VERSION 5.8 ;
BUSBITCHARS "[]" ;
DIVIDERCHAR "/" ;

SITE IOSite
  CLASS       PAD ;
  SYMMETRY    X Y R90 ;
  SIZE        0.001 BY 119.500 ;
END IOSite

SITE CornerSite
  CLASS       PAD ;
  SYMMETRY    X Y R90 ;
  SIZE        119.500 BY 119.500 ;
END CornerSite

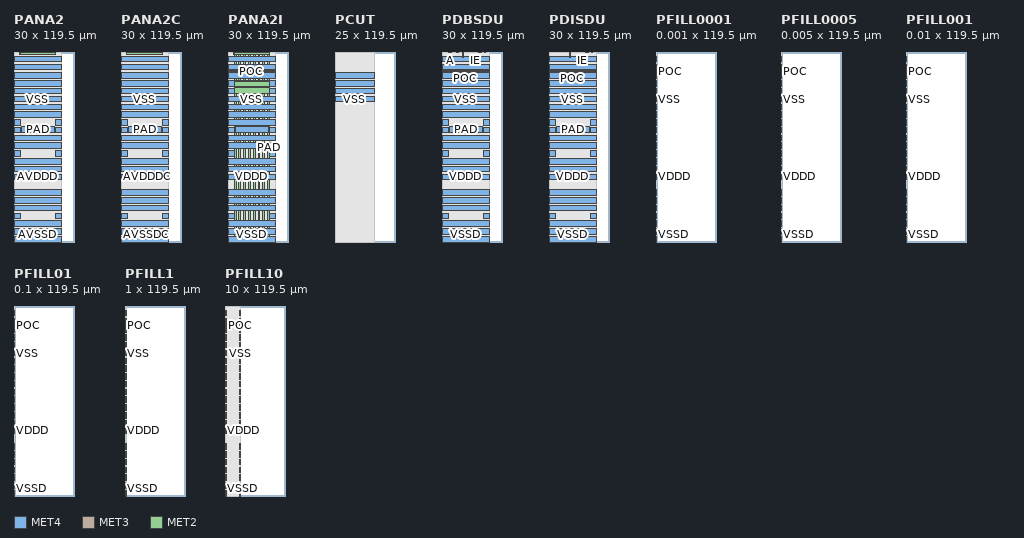
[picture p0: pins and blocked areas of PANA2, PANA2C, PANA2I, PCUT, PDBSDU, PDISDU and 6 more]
MACRO PANA2
  CLASS PAD ;
  ORIGIN 0 0 ;
  FOREIGN PANA2 0 0 ;
  SIZE 30 BY 119.5 ;
  SYMMETRY X Y R90 ;
  SITE IOSite ;
  PIN PAD
    DIRECTION INOUT ;
    USE SIGNAL ;
    ANTENNAPARTIALMETALAREA 1394.854 LAYER MET2 ;
    ANTENNAPARTIALMETALAREA 1394.854 LAYER MET3 ;
    ANTENNAPARTIALMETALAREA 319.515 LAYER MET4 ;
    ANTENNAPARTIALMETALSIDEAREA 395.8332 LAYER MET2 ;
    ANTENNAPARTIALMETALSIDEAREA 395.8332 LAYER MET3 ;
    ANTENNAPARTIALMETALSIDEAREA 41.6703 LAYER MET4 ;
    ANTENNAPARTIALCUTAREA 33.048 LAYER VIA3 ;
    ANTENNAPARTIALCUTAREA 249.2856 LAYER VIA2 ;
    ANTENNADIFFAREA 671.232 LAYER MET2 ;
    ANTENNADIFFAREA 671.232 LAYER MET3 ;
    ANTENNADIFFAREA 671.232 LAYER MET4 ;
    PORT
      LAYER MET4 ;
        RECT 3.76 117.8 26.24 119.5 ;
        RECT 4.5 68.6 25.5 72.415 ;
      LAYER MET3 ;
        RECT 3.79 117.8 26.21 119.5 ;
      LAYER MET2 ;
        RECT 3.79 117.8 26.21 119.5 ;
    END
  END PAD
  PIN AVDDD
    DIRECTION INOUT ;
    USE POWER ;
    PORT
      LAYER MET4 ;
        RECT 0 39.2 30 42.7 ;
        RECT 0 44.1 30 47.6 ;
        RECT 0 49 30 52.5 ;
        RECT 26 53.9 30 57.4 ;
        RECT 0 58.8 30 62.3 ;
        RECT 0 63.7 30 67.2 ;
        RECT 26 68.6 30 72.1 ;
        RECT 26 73.415 30 76.915 ;
        RECT 0 78.315 30 81.815 ;
        RECT 0 83.215 30 86.715 ;
        RECT 0 108.4 30 111.9 ;
        RECT 0 113.3 30 116.8 ;
        RECT 0 53.9 4 57.4 ;
        RECT 0 68.6 4 72.1 ;
        RECT 0 73.415 4 76.915 ;
    END
  END AVDDD
  PIN AVSSD
    DIRECTION INOUT ;
    USE GROUND ;
    PORT
      LAYER MET4 ;
        RECT 0 0 30 3.5 ;
        RECT 0 4.9 30 8.4 ;
        RECT 0 9.8 30 13.3 ;
        RECT 26 14.7 30 18.2 ;
        RECT 0 19.6 30 23.1 ;
        RECT 0 24.5 30 28 ;
        RECT 0 29.4 30 32.9 ;
        RECT 0 14.7 4 18.2 ;
    END
  END AVSSD
  PIN VSS
    DIRECTION INOUT ;
    USE GROUND ;
    PORT
      LAYER MET4 ;
        RECT 0 88.115 30 91.615 ;
        RECT 0 93.1 30 96.6 ;
        RECT 0 98 30 101.5 ;
        RECT 0 102.9 30 106.4 ;
    END
  END VSS
  OBS
    LAYER MET1 ;
      RECT 0 0 30 119.5 ;
    LAYER VIA1 ;
      RECT 0 0 30 119.5 ;
    LAYER MET2 ;
      RECT 0 0 30 119.5 ;
    LAYER VIA2 ;
      RECT 0 0 30 119.5 ;
    LAYER MET3 ;
      RECT 0 0 30 119.5 ;
    LAYER VIA3 ;
      RECT 0 0 30 119.5 ;
    LAYER MET4 ;
      RECT 0 0 30 119.5 ;
  END
END PANA2

MACRO PANA2C
  CLASS PAD ;
  ORIGIN 0 0 ;
  FOREIGN PANA2C 0 0 ;
  SIZE 30 BY 119.5 ;
  SYMMETRY X Y R90 ;
  SITE IOSite ;
  PIN PAD
    DIRECTION INOUT ;
    USE SIGNAL ;
    ANTENNAPARTIALMETALAREA 1394.752 LAYER MET2 ;
    ANTENNAPARTIALMETALAREA 1394.752 LAYER MET3 ;
    ANTENNAPARTIALMETALAREA 319.515 LAYER MET4 ;
    ANTENNAPARTIALMETALSIDEAREA 395.808 LAYER MET2 ;
    ANTENNAPARTIALMETALSIDEAREA 395.808 LAYER MET3 ;
    ANTENNAPARTIALMETALSIDEAREA 41.6703 LAYER MET4 ;
    ANTENNAPARTIALCUTAREA 33.048 LAYER VIA3 ;
    ANTENNAPARTIALCUTAREA 213.111 LAYER VIA2 ;
    ANTENNADIFFAREA 671.232 LAYER MET2 ;
    ANTENNADIFFAREA 671.232 LAYER MET3 ;
    ANTENNADIFFAREA 671.232 LAYER MET4 ;
    PORT
      LAYER MET4 ;
        RECT 3.76 117.8 26.24 119.5 ;
        RECT 4.5 68.6 25.5 72.415 ;
      LAYER MET3 ;
        RECT 3.76 117.8 26.24 119.5 ;
      LAYER MET2 ;
        RECT 3.76 117.8 26.24 119.5 ;
    END
  END PAD
  PIN AVDDDC
    DIRECTION INOUT ;
    USE POWER ;
    PORT
      LAYER MET4 ;
        RECT 0 39.2 30 42.7 ;
        RECT 0 44.1 30 47.6 ;
        RECT 0 49 30 52.5 ;
        RECT 26 53.9 30 57.4 ;
        RECT 0 58.8 30 62.3 ;
        RECT 0 63.7 30 67.2 ;
        RECT 26 68.6 30 72.1 ;
        RECT 26 73.415 30 76.915 ;
        RECT 0 78.315 30 81.815 ;
        RECT 0 83.215 30 86.715 ;
        RECT 0 108.4 30 111.9 ;
        RECT 0 113.3 30 116.8 ;
        RECT 0 53.9 4 57.4 ;
        RECT 0 68.6 4 72.1 ;
        RECT 0 73.415 4 76.915 ;
    END
  END AVDDDC
  PIN AVSSDC
    DIRECTION INOUT ;
    USE GROUND ;
    PORT
      LAYER MET4 ;
        RECT 0 0 30 3.5 ;
        RECT 0 4.9 30 8.4 ;
        RECT 0 9.8 30 13.3 ;
        RECT 26 14.7 30 18.2 ;
        RECT 0 19.6 30 23.1 ;
        RECT 0 24.5 30 28 ;
        RECT 0 29.4 30 32.9 ;
        RECT 0 14.7 4 18.2 ;
    END
  END AVSSDC
  PIN VSS
    DIRECTION INOUT ;
    USE GROUND ;
    PORT
      LAYER MET4 ;
        RECT 0 88.115 30 91.615 ;
        RECT 0 93.1 30 96.6 ;
        RECT 0 98 30 101.5 ;
        RECT 0 102.9 30 106.4 ;
    END
  END VSS
  OBS
    LAYER MET1 ;
      RECT 0 0 30 119.5 ;
    LAYER VIA1 ;
      RECT 0 0 30 119.5 ;
    LAYER MET2 ;
      RECT 0 0 30 119.5 ;
    LAYER VIA2 ;
      RECT 0 0 30 119.5 ;
    LAYER MET3 ;
      RECT 0 0 30 119.5 ;
    LAYER VIA3 ;
      RECT 0 0 30 119.5 ;
    LAYER MET4 ;
      RECT 0 0 30 119.5 ;
  END
END PANA2C

MACRO PANA2I
  CLASS PAD ;
  ORIGIN 0 0 ;
  FOREIGN PANA2I 0 0 ;
  SIZE 30 BY 119.5 ;
  SYMMETRY X Y R90 ;
  SITE IOSite ;
  PIN PAD
    DIRECTION INOUT ;
    USE SIGNAL ;
    ANTENNAPARTIALMETALAREA 250.628 LAYER MET2 ;
    ANTENNAPARTIALMETALAREA 250.152 LAYER MET3 ;
    ANTENNAPARTIALMETALAREA 319.515 LAYER MET4 ;
    ANTENNAPARTIALMETALSIDEAREA 41.6703 LAYER MET4 ;
    ANTENNAPARTIALCUTAREA 28.4634 LAYER VIA3 ;
    ANTENNAPARTIALCUTAREA 201.9897 LAYER VIA2 ;
    ANTENNADIFFAREA 671.232 LAYER MET2 ;
    ANTENNADIFFAREA 671.232 LAYER MET3 ;
    ANTENNADIFFAREA 671.232 LAYER MET4 ;
    PORT
      LAYER MET4 ;
        RECT 3.76 117.8 26.24 119.5 ;
        RECT 4.5 68.6 25.5 72.415 ;
      LAYER MET3 ;
        RECT 3.76 117.8 26.24 119.5 ;
        RECT 24.9 0 26.1 119.5 ;
        RECT 3.9 98 26.1 101 ;
        RECT 3.9 93.1 26.1 97.1 ;
        RECT 21.9 0 23.1 119.5 ;
        RECT 18.9 0 20.1 119.5 ;
        RECT 15.9 0 17.1 119.5 ;
        RECT 12.9 0 14.1 119.5 ;
        RECT 9.9 0 11.1 119.5 ;
        RECT 6.9 0 8.1 119.5 ;
        RECT 3.9 0 5.1 119.5 ;
      LAYER MET2 ;
        RECT 3.9 117.8 26.1 119.5 ;
        RECT 24.9 0 26.1 119.5 ;
        RECT 3.9 98 26.1 101 ;
        RECT 3.9 93.1 26.1 97.1 ;
        RECT 21.9 0 23.1 119.5 ;
        RECT 18.9 0 20.1 119.5 ;
        RECT 15.9 0 17.1 119.5 ;
        RECT 12.9 0 14.1 119.5 ;
        RECT 9.9 0 11.1 119.5 ;
        RECT 6.9 0 8.1 119.5 ;
        RECT 3.9 0 5.1 119.5 ;
    END
  END PAD
  PIN POC
    DIRECTION INOUT ;
    USE GROUND ;
    PORT
      LAYER MET4 ;
        RECT 0 107.15 30 107.65 ;
    END
  END POC
  PIN VDD
    DIRECTION INOUT ;
    USE POWER ;
    PORT
      CLASS CORE ;
      LAYER MET4 ;
        RECT 0 113.3 30 116.8 ;
    END
    PORT
      LAYER MET4 ;
        RECT 0 108.4 30 111.9 ;
    END
  END VDD
  PIN VDDD
    DIRECTION INOUT ;
    USE POWER ;
    PORT
      LAYER MET4 ;
        RECT 0 39.2 30 42.7 ;
        RECT 0 44.1 30 47.6 ;
        RECT 0 49 30 52.5 ;
        RECT 26 53.9 30 57.4 ;
        RECT 0 58.8 30 62.3 ;
        RECT 0 63.7 30 67.2 ;
        RECT 26 68.6 30 72.1 ;
        RECT 0 73.415 30 76.915 ;
        RECT 0 78.315 30 81.815 ;
        RECT 0 83.215 30 86.715 ;
        RECT 0 53.9 4 57.4 ;
        RECT 0 68.6 4 72.1 ;
    END
  END VDDD
  PIN VSS
    DIRECTION INOUT ;
    USE GROUND ;
    PORT
      LAYER MET4 ;
        RECT 0 88.115 30 91.615 ;
        RECT 0 93.1 30 96.6 ;
        RECT 0 98 30 101.5 ;
        RECT 0 102.9 30 106.4 ;
    END
  END VSS
  PIN VSSD
    DIRECTION INOUT ;
    USE GROUND ;
    PORT
      LAYER MET4 ;
        RECT 0 0 30 3.5 ;
        RECT 0 4.9 30 8.4 ;
        RECT 0 9.8 30 13.3 ;
        RECT 26 14.7 30 18.2 ;
        RECT 0 19.6 30 23.1 ;
        RECT 0 24.5 30 28 ;
        RECT 0 29.4 30 32.9 ;
        RECT 0 14.7 4 18.2 ;
    END
  END VSSD
  OBS
    LAYER MET1 ;
      RECT 0 0 30 119.5 ;
    LAYER VIA1 ;
      RECT 0 0 30 119.5 ;
    LAYER MET2 ;
      RECT 0 0 30 119.5 ;
    LAYER VIA2 ;
      RECT 0 0 30 119.5 ;
    LAYER MET3 ;
      RECT 0 0 30 119.5 ;
    LAYER VIA3 ;
      RECT 0 0 30 119.5 ;
    LAYER MET4 ;
      RECT 0 0 30 119.5 ;
  END
END PANA2I

MACRO PCUT
  CLASS PAD ;
  ORIGIN 0 0 ;
  FOREIGN PCUT 0 0 ;
  SIZE 25 BY 119.5 ;
  SYMMETRY X Y R90 ;
  SITE IOSite ;
  PIN VSS
    DIRECTION INOUT ;
    USE GROUND ;
    PORT
      LAYER MET4 ;
        RECT 0 88.115 25 91.615 ;
        RECT 0 93.1 25 96.6 ;
        RECT 0 98 25 101.5 ;
        RECT 0 102.9 25 106.4 ;
    END
  END VSS
  OBS
    LAYER MET1 ;
      RECT 0 0 25 119.5 ;
    LAYER VIA1 ;
      RECT 0 0 25 119.5 ;
    LAYER MET2 ;
      RECT 0 0 25 119.5 ;
    LAYER VIA2 ;
      RECT 0 0 25 119.5 ;
    LAYER MET3 ;
      RECT 0 0 25 119.5 ;
    LAYER VIA3 ;
      RECT 0 0 25 119.5 ;
    LAYER MET4 ;
      RECT 0 0 25 119.5 ;
  END
END PCUT

MACRO PDBSDU
  CLASS PAD ;
  ORIGIN 0 0 ;
  FOREIGN PDBSDU 0 0 ;
  SIZE 30 BY 119.5 ;
  SYMMETRY X Y R90 ;
  SITE IOSite ;
  PIN A
    DIRECTION INPUT ;
    USE SIGNAL ;
    ANTENNAPARTIALMETALAREA 1.66719 LAYER MET2 ;
    ANTENNAPARTIALMETALAREA 0.6384 LAYER MET3 ;
    ANTENNAPARTIALMETALSIDEAREA 4.11894 LAYER MET2 ;
    ANTENNAPARTIALMETALSIDEAREA 0.8652 LAYER MET3 ;
    ANTENNAPARTIALCUTAREA 0.0243 LAYER VIA3 ;
    ANTENNAPARTIALCUTAREA 0.0405 LAYER VIA2 ;
    ANTENNAMODEL OXIDE1 ;
      ANTENNAGATEAREA 0.333 LAYER MET2 ;
      ANTENNAGATEAREA 0.846 LAYER MET3 ;
      ANTENNAGATEAREA 0.846 LAYER MET4 ;
      ANTENNAMAXAREACAR 7.098407 LAYER MET2 ;
      ANTENNAMAXAREACAR 8.243407 LAYER MET3 ;
      ANTENNAMAXAREACAR 8.397071 LAYER MET4 ;
      ANTENNAMAXSIDEAREACAR 15.275072 LAYER MET2 ;
      ANTENNAMAXSIDEAREACAR 17.256325 LAYER MET3 ;
      ANTENNAMAXSIDEAREACAR 17.63363 LAYER MET4 ;
      ANTENNAMAXCUTCAR 0.256227 LAYER VIA3 ;
      ANTENNAMAXCUTCAR 0.227504 LAYER VIA2 ;
    PORT
      LAYER MET4 ;
        RECT 5.235 119.24 5.735 119.5 ;
      LAYER MET3 ;
        RECT 5.235 119.24 5.735 119.5 ;
      LAYER MET2 ;
        RECT 5.235 119.24 5.735 119.5 ;
    END
  END A
  PIN C
    DIRECTION OUTPUT ;
    USE SIGNAL ;
    ANTENNAPARTIALMETALAREA 10.04162 LAYER MET2 ;
    ANTENNAPARTIALMETALSIDEAREA 21.72282 LAYER MET2 ;
    ANTENNAPARTIALCUTAREA 0.0243 LAYER VIA3 ;
    ANTENNAPARTIALCUTAREA 0.0243 LAYER VIA2 ;
    ANTENNADIFFAREA 4.8 LAYER MET2 ;
    ANTENNADIFFAREA 4.8 LAYER MET3 ;
    ANTENNADIFFAREA 4.8 LAYER MET4 ;
    PORT
      LAYER MET4 ;
        RECT 13.025 119.24 13.525 119.5 ;
      LAYER MET3 ;
        RECT 13.025 119.24 13.525 119.5 ;
      LAYER MET2 ;
        RECT 13.025 116.277 13.525 119.5 ;
    END
  END C
  PIN IE
    DIRECTION INPUT ;
    USE SIGNAL ;
    ANTENNAPARTIALMETALAREA 1.83225 LAYER MET2 ;
    ANTENNAPARTIALMETALSIDEAREA 5.1303 LAYER MET2 ;
    ANTENNAPARTIALCUTAREA 0.0243 LAYER VIA3 ;
    ANTENNAPARTIALCUTAREA 0.0243 LAYER VIA2 ;
    ANTENNAMODEL OXIDE1 ;
      ANTENNAGATEAREA 0.468 LAYER MET2 ;
      ANTENNAGATEAREA 0.468 LAYER MET3 ;
      ANTENNAGATEAREA 0.468 LAYER MET4 ;
      ANTENNAMAXAREACAR 5.590342 LAYER MET2 ;
      ANTENNAMAXAREACAR 5.86812 LAYER MET3 ;
      ANTENNAMAXAREACAR 6.145897 LAYER MET4 ;
      ANTENNAMAXSIDEAREACAR 13.332179 LAYER MET2 ;
      ANTENNAMAXSIDEAREACAR 14.014231 LAYER MET3 ;
      ANTENNAMAXSIDEAREACAR 14.696282 LAYER MET4 ;
      ANTENNAMAXCUTCAR 0.193846 LAYER VIA3 ;
      ANTENNAMAXCUTCAR 0.141923 LAYER VIA2 ;
    PORT
      LAYER MET4 ;
        RECT 20.875 119.24 21.375 119.5 ;
      LAYER MET3 ;
        RECT 20.875 119.24 21.375 119.5 ;
      LAYER MET2 ;
        RECT 20.875 119.24 21.375 119.5 ;
    END
  END IE
  PIN OE
    DIRECTION INPUT ;
    USE SIGNAL ;
    ANTENNAPARTIALMETALAREA 1.66005 LAYER MET2 ;
    ANTENNAPARTIALMETALAREA 1.178 LAYER MET3 ;
    ANTENNAPARTIALMETALSIDEAREA 4.1013 LAYER MET2 ;
    ANTENNAPARTIALMETALSIDEAREA 1.4616 LAYER MET3 ;
    ANTENNAPARTIALCUTAREA 0.0243 LAYER VIA3 ;
    ANTENNAPARTIALCUTAREA 0.0405 LAYER VIA2 ;
    ANTENNAMODEL OXIDE1 ;
      ANTENNAGATEAREA 0.333 LAYER MET2 ;
      ANTENNAGATEAREA 0.801 LAYER MET3 ;
      ANTENNAGATEAREA 0.801 LAYER MET4 ;
      ANTENNAMAXAREACAR 5.212558 LAYER MET2 ;
      ANTENNAMAXAREACAR 7.07361 LAYER MET3 ;
      ANTENNAMAXAREACAR 7.235908 LAYER MET4 ;
      ANTENNAMAXSIDEAREACAR 10.956954 LAYER MET2 ;
      ANTENNAMAXSIDEAREACAR 13.740232 LAYER MET3 ;
      ANTENNAMAXSIDEAREACAR 14.138734 LAYER MET4 ;
      ANTENNAMAXCUTCAR 0.206876 LAYER VIA3 ;
      ANTENNAMAXCUTCAR 0.176538 LAYER VIA2 ;
    PORT
      LAYER MET4 ;
        RECT 4.085 119.24 4.585 119.5 ;
      LAYER MET3 ;
        RECT 4.085 119.24 4.585 119.5 ;
      LAYER MET2 ;
        RECT 4.085 119.24 4.585 119.5 ;
    END
  END OE
  PIN PD
    DIRECTION INPUT ;
    USE SIGNAL ;
    ANTENNAPARTIALMETALAREA 1.83225 LAYER MET2 ;
    ANTENNAPARTIALMETALAREA 0.4695 LAYER MET3 ;
    ANTENNAPARTIALMETALSIDEAREA 5.1303 LAYER MET2 ;
    ANTENNAPARTIALMETALSIDEAREA 1.3692 LAYER MET3 ;
    ANTENNAPARTIALCUTAREA 0.0243 LAYER VIA3 ;
    ANTENNAPARTIALCUTAREA 0.0405 LAYER VIA2 ;
    ANTENNADIFFAREA 0.39 LAYER MET2 ;
    ANTENNADIFFAREA 0.39 LAYER MET3 ;
    ANTENNADIFFAREA 0.39 LAYER MET4 ;
    ANTENNAMODEL OXIDE1 ;
      ANTENNAGATEAREA 0.468 LAYER MET2 ;
      ANTENNAGATEAREA 6.468 LAYER MET3 ;
      ANTENNAGATEAREA 6.468 LAYER MET4 ;
      ANTENNAMAXAREACAR 5.590342 LAYER MET2 ;
      ANTENNAMAXAREACAR 5.940708 LAYER MET3 ;
      ANTENNAMAXAREACAR 5.960807 LAYER MET4 ;
      ANTENNAMAXSIDEAREACAR 13.332179 LAYER MET2 ;
      ANTENNAMAXSIDEAREACAR 14.225919 LAYER MET3 ;
      ANTENNAMAXSIDEAREACAR 14.27527 LAYER MET4 ;
      ANTENNAMAXCUTCAR 0.180295 LAYER VIA3 ;
      ANTENNAMAXCUTCAR 0.176538 LAYER VIA2 ;
    PORT
      LAYER MET4 ;
        RECT 24.03 119.24 24.53 119.5 ;
      LAYER MET3 ;
        RECT 24.03 119.24 24.53 119.5 ;
      LAYER MET2 ;
        RECT 24.03 119.24 24.53 119.5 ;
    END
  END PD
  PIN PU
    DIRECTION INPUT ;
    USE SIGNAL ;
    ANTENNAPARTIALMETALAREA 2.28055 LAYER MET2 ;
    ANTENNAPARTIALMETALSIDEAREA 5.6343 LAYER MET2 ;
    ANTENNAPARTIALCUTAREA 0.0243 LAYER VIA3 ;
    ANTENNAPARTIALCUTAREA 0.0243 LAYER VIA2 ;
    ANTENNADIFFAREA 0.39 LAYER MET2 ;
    ANTENNADIFFAREA 0.39 LAYER MET3 ;
    ANTENNADIFFAREA 0.39 LAYER MET4 ;
    ANTENNAMODEL OXIDE1 ;
      ANTENNAGATEAREA 6.468 LAYER MET2 ;
      ANTENNAGATEAREA 6.468 LAYER MET3 ;
      ANTENNAGATEAREA 6.468 LAYER MET4 ;
      ANTENNAMAXAREACAR 2.11009 LAYER MET2 ;
      ANTENNAMAXAREACAR 2.130189 LAYER MET3 ;
      ANTENNAMAXAREACAR 2.150288 LAYER MET4 ;
      ANTENNAMAXSIDEAREACAR 3.321104 LAYER MET2 ;
      ANTENNAMAXSIDEAREACAR 3.370455 LAYER MET3 ;
      ANTENNAMAXSIDEAREACAR 3.419805 LAYER MET4 ;
      ANTENNAMAXCUTCAR 0.097514 LAYER VIA3 ;
      ANTENNAMAXCUTCAR 0.093757 LAYER VIA2 ;
    PORT
      LAYER MET4 ;
        RECT 26.71 119.24 27.21 119.5 ;
      LAYER MET3 ;
        RECT 26.71 119.24 27.21 119.5 ;
      LAYER MET2 ;
        RECT 26.71 119.24 27.21 119.5 ;
    END
  END PU
  PIN S0
    DIRECTION INPUT ;
    USE SIGNAL ;
    ANTENNAPARTIALMETALAREA 1.9601 LAYER MET2 ;
    ANTENNAPARTIALMETALAREA 0.159 LAYER MET3 ;
    ANTENNAPARTIALMETALSIDEAREA 4.8426 LAYER MET2 ;
    ANTENNAPARTIALMETALSIDEAREA 0.4914 LAYER MET3 ;
    ANTENNAPARTIALCUTAREA 0.0243 LAYER VIA3 ;
    ANTENNAPARTIALCUTAREA 0.0405 LAYER VIA2 ;
    ANTENNADIFFAREA 0.39 LAYER MET2 ;
    ANTENNADIFFAREA 0.39 LAYER MET3 ;
    ANTENNADIFFAREA 0.39 LAYER MET4 ;
    ANTENNAMODEL OXIDE1 ;
      ANTENNAGATEAREA 0.468 LAYER MET2 ;
      ANTENNAGATEAREA 6.468 LAYER MET3 ;
      ANTENNAGATEAREA 6.468 LAYER MET4 ;
      ANTENNAMAXAREACAR 5.945748 LAYER MET2 ;
      ANTENNAMAXAREACAR 6.248108 LAYER MET3 ;
      ANTENNAMAXAREACAR 6.268207 LAYER MET4 ;
      ANTENNAMAXSIDEAREACAR 12.797436 LAYER MET2 ;
      ANTENNAMAXSIDEAREACAR 13.555461 LAYER MET3 ;
      ANTENNAMAXSIDEAREACAR 13.604812 LAYER MET4 ;
      ANTENNAMAXCUTCAR 0.180295 LAYER VIA3 ;
      ANTENNAMAXCUTCAR 0.176538 LAYER VIA2 ;
    PORT
      LAYER MET4 ;
        RECT 8.195 119.24 8.695 119.5 ;
      LAYER MET3 ;
        RECT 8.195 119.24 8.695 119.5 ;
      LAYER MET2 ;
        RECT 8.195 119.24 8.695 119.5 ;
    END
  END S0
  PIN S1
    DIRECTION INPUT ;
    USE SIGNAL ;
    ANTENNAPARTIALMETALAREA 1.9397 LAYER MET2 ;
    ANTENNAPARTIALMETALAREA 0.24 LAYER MET3 ;
    ANTENNAPARTIALMETALSIDEAREA 4.7922 LAYER MET2 ;
    ANTENNAPARTIALMETALSIDEAREA 0.7182 LAYER MET3 ;
    ANTENNAPARTIALCUTAREA 0.0243 LAYER VIA3 ;
    ANTENNAPARTIALCUTAREA 0.0405 LAYER VIA2 ;
    ANTENNADIFFAREA 0.39 LAYER MET2 ;
    ANTENNADIFFAREA 0.39 LAYER MET3 ;
    ANTENNADIFFAREA 0.39 LAYER MET4 ;
    ANTENNAMODEL OXIDE1 ;
      ANTENNAGATEAREA 0.468 LAYER MET2 ;
      ANTENNAGATEAREA 6.468 LAYER MET3 ;
      ANTENNAGATEAREA 6.468 LAYER MET4 ;
      ANTENNAMAXAREACAR 6.148825 LAYER MET2 ;
      ANTENNAMAXAREACAR 6.463708 LAYER MET3 ;
      ANTENNAMAXAREACAR 6.483807 LAYER MET4 ;
      ANTENNAMAXSIDEAREACAR 12.929744 LAYER MET2 ;
      ANTENNAMAXSIDEAREACAR 13.722834 LAYER MET3 ;
      ANTENNAMAXSIDEAREACAR 13.772184 LAYER MET4 ;
      ANTENNAMAXCUTCAR 0.180295 LAYER VIA3 ;
      ANTENNAMAXCUTCAR 0.176538 LAYER VIA2 ;
    PORT
      LAYER MET4 ;
        RECT 9.115 119.24 9.615 119.5 ;
      LAYER MET3 ;
        RECT 9.115 119.24 9.615 119.5 ;
      LAYER MET2 ;
        RECT 9.115 119.24 9.615 119.5 ;
    END
  END S1
  PIN S2
    DIRECTION INPUT ;
    USE SIGNAL ;
    ANTENNAPARTIALMETALAREA 2.074 LAYER MET2 ;
    ANTENNAPARTIALMETALAREA 0.378 LAYER MET3 ;
    ANTENNAPARTIALMETALSIDEAREA 5.124 LAYER MET2 ;
    ANTENNAPARTIALMETALSIDEAREA 1.1046 LAYER MET3 ;
    ANTENNAPARTIALCUTAREA 0.0243 LAYER VIA3 ;
    ANTENNAPARTIALCUTAREA 0.0405 LAYER VIA2 ;
    ANTENNADIFFAREA 0.39 LAYER MET2 ;
    ANTENNADIFFAREA 0.39 LAYER MET3 ;
    ANTENNADIFFAREA 0.39 LAYER MET4 ;
    ANTENNAMODEL OXIDE1 ;
      ANTENNAGATEAREA 0.468 LAYER MET2 ;
      ANTENNAGATEAREA 6.468 LAYER MET3 ;
      ANTENNAGATEAREA 6.468 LAYER MET4 ;
      ANTENNAMAXAREACAR 6.168568 LAYER MET2 ;
      ANTENNAMAXAREACAR 6.504788 LAYER MET3 ;
      ANTENNAMAXAREACAR 6.524887 LAYER MET4 ;
      ANTENNAMAXSIDEAREACAR 13.378718 LAYER MET2 ;
      ANTENNAMAXSIDEAREACAR 14.231548 LAYER MET3 ;
      ANTENNAMAXSIDEAREACAR 14.280899 LAYER MET4 ;
      ANTENNAMAXCUTCAR 0.180295 LAYER VIA3 ;
      ANTENNAMAXCUTCAR 0.176538 LAYER VIA2 ;
    PORT
      LAYER MET4 ;
        RECT 10.035 119.24 10.535 119.5 ;
      LAYER MET3 ;
        RECT 10.035 119.24 10.535 119.5 ;
      LAYER MET2 ;
        RECT 10.035 119.24 10.535 119.5 ;
    END
  END S2
  PIN ST
    DIRECTION INPUT ;
    USE SIGNAL ;
    ANTENNAPARTIALMETALAREA 2.05695 LAYER MET2 ;
    ANTENNAPARTIALMETALSIDEAREA 5.75946 LAYER MET2 ;
    ANTENNAPARTIALCUTAREA 0.0243 LAYER VIA3 ;
    ANTENNAPARTIALCUTAREA 0.0243 LAYER VIA2 ;
    ANTENNAMODEL OXIDE1 ;
      ANTENNAGATEAREA 0.468 LAYER MET2 ;
      ANTENNAGATEAREA 0.468 LAYER MET3 ;
      ANTENNAGATEAREA 0.468 LAYER MET4 ;
      ANTENNAMAXAREACAR 5.455088 LAYER MET2 ;
      ANTENNAMAXAREACAR 5.732866 LAYER MET3 ;
      ANTENNAMAXAREACAR 6.010644 LAYER MET4 ;
      ANTENNAMAXSIDEAREACAR 13.956538 LAYER MET2 ;
      ANTENNAMAXSIDEAREACAR 14.63859 LAYER MET3 ;
      ANTENNAMAXSIDEAREACAR 15.320641 LAYER MET4 ;
      ANTENNAMAXCUTCAR 0.193846 LAYER VIA3 ;
      ANTENNAMAXCUTCAR 0.141923 LAYER VIA2 ;
    PORT
      LAYER MET4 ;
        RECT 22.94 119.24 23.44 119.5 ;
      LAYER MET3 ;
        RECT 22.94 119.24 23.44 119.5 ;
      LAYER MET2 ;
        RECT 22.94 119.24 23.44 119.5 ;
    END
  END ST
  PIN PAD
    DIRECTION INOUT ;
    USE SIGNAL ;
    ANTENNAPARTIALMETALAREA 239.4 LAYER MET4 ;
    ANTENNAPARTIALMETALSIDEAREA 31.248 LAYER MET4 ;
    ANTENNADIFFAREA 711.021 LAYER MET4 ;
    ANTENNAMODEL OXIDE1 ;
      ANTENNAGATEAREA 8.48 LAYER MET4 ;
      ANTENNAMAXAREACAR 85.18755 LAYER MET4 ;
      ANTENNAMAXSIDEAREACAR 24.939633 LAYER MET4 ;
    PORT
      LAYER MET4 ;
        RECT 4.5 68.6 25.5 72.415 ;
    END
  END PAD
  PIN POC
    DIRECTION INPUT ;
    USE GROUND ;
    PORT
      LAYER MET4 ;
        RECT 0 107.15 30 107.65 ;
    END
  END POC
  PIN VDD
    DIRECTION INOUT ;
    USE POWER ;
    PORT
      CLASS CORE ;
      LAYER MET4 ;
        RECT 0 113.3 30 116.8 ;
    END
    PORT
      LAYER MET4 ;
        RECT 0 108.4 30 111.9 ;
    END
  END VDD
  PIN VDDD
    DIRECTION INOUT ;
    USE POWER ;
    PORT
      LAYER MET4 ;
        RECT 0 39.2 30 42.7 ;
        RECT 0 44.1 30 47.6 ;
        RECT 0 49 30 52.5 ;
        RECT 26 53.9 30 57.4 ;
        RECT 0 58.8 30 62.3 ;
        RECT 0 63.7 30 67.2 ;
        RECT 26 68.6 30 72.1 ;
        RECT 26 73.415 30 76.915 ;
        RECT 0 78.315 30 81.815 ;
        RECT 0 83.215 30 86.715 ;
        RECT 0 53.9 4 57.4 ;
        RECT 0 68.6 4 72.1 ;
        RECT 0 73.415 4 76.915 ;
    END
  END VDDD
  PIN VSS
    DIRECTION INOUT ;
    USE GROUND ;
    PORT
      LAYER MET4 ;
        RECT 0 88.115 30 91.615 ;
        RECT 0 93.1 30 96.6 ;
        RECT 0 98 30 101.5 ;
        RECT 0 102.9 30 106.4 ;
    END
  END VSS
  PIN VSSD
    DIRECTION INOUT ;
    USE GROUND ;
    PORT
      LAYER MET4 ;
        RECT 0 0 30 3.5 ;
        RECT 0 4.9 30 8.4 ;
        RECT 0 9.8 30 13.3 ;
        RECT 26 14.7 30 18.2 ;
        RECT 0 19.6 30 23.1 ;
        RECT 0 24.5 30 28 ;
        RECT 0 29.4 30 32.9 ;
        RECT 0 14.7 4 18.2 ;
    END
  END VSSD
  OBS
    LAYER MET1 ;
      RECT 0 0 30 119.5 ;
    LAYER VIA1 ;
      RECT 0 0 30 119.5 ;
    LAYER MET2 ;
      RECT 0 0 30 119.5 ;
    LAYER VIA2 ;
      RECT 0 0 30 119.5 ;
    LAYER MET3 ;
      RECT 0 0 30 119.5 ;
    LAYER VIA3 ;
      RECT 0 0 30 119.5 ;
    LAYER MET4 ;
      RECT 0 0 30 119.5 ;
  END
END PDBSDU

MACRO PDISDU
  CLASS PAD ;
  ORIGIN 0 0 ;
  FOREIGN PDISDU 0 0 ;
  SIZE 30 BY 119.5 ;
  SYMMETRY X Y R90 ;
  SITE IOSite ;
  PIN C
    DIRECTION OUTPUT ;
    USE SIGNAL ;
    ANTENNAPARTIALMETALAREA 10.04162 LAYER MET2 ;
    ANTENNAPARTIALMETALSIDEAREA 21.72282 LAYER MET2 ;
    ANTENNAPARTIALCUTAREA 0.0243 LAYER VIA3 ;
    ANTENNAPARTIALCUTAREA 0.0243 LAYER VIA2 ;
    ANTENNADIFFAREA 4.8 LAYER MET2 ;
    ANTENNADIFFAREA 4.8 LAYER MET3 ;
    ANTENNADIFFAREA 4.8 LAYER MET4 ;
    PORT
      LAYER MET4 ;
        RECT 13.025 119.24 13.525 119.5 ;
      LAYER MET3 ;
        RECT 13.025 119.24 13.525 119.5 ;
      LAYER MET2 ;
        RECT 13.025 116.277 13.525 119.5 ;
    END
  END C
  PIN IE
    DIRECTION INPUT ;
    USE SIGNAL ;
    ANTENNAPARTIALMETALAREA 1.83225 LAYER MET2 ;
    ANTENNAPARTIALMETALSIDEAREA 5.1303 LAYER MET2 ;
    ANTENNAPARTIALCUTAREA 0.0243 LAYER VIA3 ;
    ANTENNAPARTIALCUTAREA 0.0243 LAYER VIA2 ;
    ANTENNAMODEL OXIDE1 ;
      ANTENNAGATEAREA 0.468 LAYER MET2 ;
      ANTENNAGATEAREA 0.468 LAYER MET3 ;
      ANTENNAGATEAREA 0.468 LAYER MET4 ;
      ANTENNAMAXAREACAR 5.590342 LAYER MET2 ;
      ANTENNAMAXAREACAR 5.86812 LAYER MET3 ;
      ANTENNAMAXAREACAR 6.145897 LAYER MET4 ;
      ANTENNAMAXSIDEAREACAR 13.332179 LAYER MET2 ;
      ANTENNAMAXSIDEAREACAR 14.014231 LAYER MET3 ;
      ANTENNAMAXSIDEAREACAR 14.696282 LAYER MET4 ;
      ANTENNAMAXCUTCAR 0.193846 LAYER VIA3 ;
      ANTENNAMAXCUTCAR 0.141923 LAYER VIA2 ;
    PORT
      LAYER MET4 ;
        RECT 20.875 119.24 21.375 119.5 ;
      LAYER MET3 ;
        RECT 20.875 119.24 21.375 119.5 ;
      LAYER MET2 ;
        RECT 20.875 119.24 21.375 119.5 ;
    END
  END IE
  PIN PD
    DIRECTION INPUT ;
    USE SIGNAL ;
    ANTENNAPARTIALMETALAREA 1.83225 LAYER MET2 ;
    ANTENNAPARTIALMETALAREA 0.4695 LAYER MET3 ;
    ANTENNAPARTIALMETALSIDEAREA 5.1303 LAYER MET2 ;
    ANTENNAPARTIALMETALSIDEAREA 1.3692 LAYER MET3 ;
    ANTENNAPARTIALCUTAREA 0.0243 LAYER VIA3 ;
    ANTENNAPARTIALCUTAREA 0.0405 LAYER VIA2 ;
    ANTENNADIFFAREA 0.39 LAYER MET2 ;
    ANTENNADIFFAREA 0.39 LAYER MET3 ;
    ANTENNADIFFAREA 0.39 LAYER MET4 ;
    ANTENNAMODEL OXIDE1 ;
      ANTENNAGATEAREA 0.468 LAYER MET2 ;
      ANTENNAGATEAREA 6.468 LAYER MET3 ;
      ANTENNAGATEAREA 6.468 LAYER MET4 ;
      ANTENNAMAXAREACAR 5.590342 LAYER MET2 ;
      ANTENNAMAXAREACAR 5.940708 LAYER MET3 ;
      ANTENNAMAXAREACAR 5.960807 LAYER MET4 ;
      ANTENNAMAXSIDEAREACAR 13.332179 LAYER MET2 ;
      ANTENNAMAXSIDEAREACAR 14.225919 LAYER MET3 ;
      ANTENNAMAXSIDEAREACAR 14.27527 LAYER MET4 ;
      ANTENNAMAXCUTCAR 0.180295 LAYER VIA3 ;
      ANTENNAMAXCUTCAR 0.176538 LAYER VIA2 ;
    PORT
      LAYER MET4 ;
        RECT 24.03 119.24 24.53 119.5 ;
      LAYER MET3 ;
        RECT 24.03 119.24 24.53 119.5 ;
      LAYER MET2 ;
        RECT 24.03 119.24 24.53 119.5 ;
    END
  END PD
  PIN PU
    DIRECTION INPUT ;
    USE SIGNAL ;
    ANTENNAPARTIALMETALAREA 2.28055 LAYER MET2 ;
    ANTENNAPARTIALMETALSIDEAREA 5.6343 LAYER MET2 ;
    ANTENNAPARTIALCUTAREA 0.0243 LAYER VIA3 ;
    ANTENNAPARTIALCUTAREA 0.0243 LAYER VIA2 ;
    ANTENNADIFFAREA 0.39 LAYER MET2 ;
    ANTENNADIFFAREA 0.39 LAYER MET3 ;
    ANTENNADIFFAREA 0.39 LAYER MET4 ;
    ANTENNAMODEL OXIDE1 ;
      ANTENNAGATEAREA 6.468 LAYER MET2 ;
      ANTENNAGATEAREA 6.468 LAYER MET3 ;
      ANTENNAGATEAREA 6.468 LAYER MET4 ;
      ANTENNAMAXAREACAR 2.11009 LAYER MET2 ;
      ANTENNAMAXAREACAR 2.130189 LAYER MET3 ;
      ANTENNAMAXAREACAR 2.150288 LAYER MET4 ;
      ANTENNAMAXSIDEAREACAR 3.321104 LAYER MET2 ;
      ANTENNAMAXSIDEAREACAR 3.370455 LAYER MET3 ;
      ANTENNAMAXSIDEAREACAR 3.419805 LAYER MET4 ;
      ANTENNAMAXCUTCAR 0.097514 LAYER VIA3 ;
      ANTENNAMAXCUTCAR 0.093757 LAYER VIA2 ;
    PORT
      LAYER MET4 ;
        RECT 26.71 119.24 27.21 119.5 ;
      LAYER MET3 ;
        RECT 26.71 119.24 27.21 119.5 ;
      LAYER MET2 ;
        RECT 26.71 119.24 27.21 119.5 ;
    END
  END PU
  PIN ST
    DIRECTION INPUT ;
    USE SIGNAL ;
    ANTENNAPARTIALMETALAREA 2.05695 LAYER MET2 ;
    ANTENNAPARTIALMETALSIDEAREA 5.75946 LAYER MET2 ;
    ANTENNAPARTIALCUTAREA 0.0243 LAYER VIA3 ;
    ANTENNAPARTIALCUTAREA 0.0243 LAYER VIA2 ;
    ANTENNAMODEL OXIDE1 ;
      ANTENNAGATEAREA 0.468 LAYER MET2 ;
      ANTENNAGATEAREA 0.468 LAYER MET3 ;
      ANTENNAGATEAREA 0.468 LAYER MET4 ;
      ANTENNAMAXAREACAR 5.455088 LAYER MET2 ;
      ANTENNAMAXAREACAR 5.732866 LAYER MET3 ;
      ANTENNAMAXAREACAR 6.010644 LAYER MET4 ;
      ANTENNAMAXSIDEAREACAR 13.956538 LAYER MET2 ;
      ANTENNAMAXSIDEAREACAR 14.63859 LAYER MET3 ;
      ANTENNAMAXSIDEAREACAR 15.320641 LAYER MET4 ;
      ANTENNAMAXCUTCAR 0.193846 LAYER VIA3 ;
      ANTENNAMAXCUTCAR 0.141923 LAYER VIA2 ;
    PORT
      LAYER MET4 ;
        RECT 22.94 119.24 23.44 119.5 ;
      LAYER MET3 ;
        RECT 22.94 119.24 23.44 119.5 ;
      LAYER MET2 ;
        RECT 22.94 119.24 23.44 119.5 ;
    END
  END ST
  PIN PAD
    DIRECTION INPUT ;
    USE SIGNAL ;
    ANTENNAPARTIALMETALAREA 239.4 LAYER MET4 ;
    ANTENNAPARTIALMETALSIDEAREA 31.248 LAYER MET4 ;
    ANTENNADIFFAREA 711.021 LAYER MET4 ;
    ANTENNAMODEL OXIDE1 ;
      ANTENNAGATEAREA 8.48 LAYER MET4 ;
      ANTENNAMAXAREACAR 85.18755 LAYER MET4 ;
      ANTENNAMAXSIDEAREACAR 24.939633 LAYER MET4 ;
    PORT
      LAYER MET4 ;
        RECT 4.5 68.6 25.5 72.415 ;
    END
  END PAD
  PIN POC
    DIRECTION INPUT ;
    USE GROUND ;
    PORT
      LAYER MET4 ;
        RECT 0 107.15 30 107.65 ;
    END
  END POC
  PIN VDD
    DIRECTION INOUT ;
    USE POWER ;
    PORT
      CLASS CORE ;
      LAYER MET4 ;
        RECT 0 113.3 30 116.8 ;
    END
    PORT
      LAYER MET4 ;
        RECT 0 108.4 30 111.9 ;
    END
  END VDD
  PIN VDDD
    DIRECTION INOUT ;
    USE POWER ;
    PORT
      LAYER MET4 ;
        RECT 0 39.2 30 42.7 ;
        RECT 0 44.1 30 47.6 ;
        RECT 0 49 30 52.5 ;
        RECT 26 53.9 30 57.4 ;
        RECT 0 58.8 30 62.3 ;
        RECT 0 63.7 30 67.2 ;
        RECT 26 68.6 30 72.1 ;
        RECT 26 73.415 30 76.915 ;
        RECT 0 78.315 30 81.815 ;
        RECT 0 83.215 30 86.715 ;
        RECT 0 53.9 4 57.4 ;
        RECT 0 68.6 4 72.1 ;
        RECT 0 73.415 4 76.915 ;
    END
  END VDDD
  PIN VSS
    DIRECTION INOUT ;
    USE GROUND ;
    PORT
      LAYER MET4 ;
        RECT 0 88.115 30 91.615 ;
        RECT 0 93.1 30 96.6 ;
        RECT 0 98 30 101.5 ;
        RECT 0 102.9 30 106.4 ;
    END
  END VSS
  PIN VSSD
    DIRECTION INOUT ;
    USE GROUND ;
    PORT
      LAYER MET4 ;
        RECT 0 0 30 3.5 ;
        RECT 0 4.9 30 8.4 ;
        RECT 0 9.8 30 13.3 ;
        RECT 26 14.7 30 18.2 ;
        RECT 0 19.6 30 23.1 ;
        RECT 0 24.5 30 28 ;
        RECT 0 29.4 30 32.9 ;
        RECT 0 14.7 4 18.2 ;
    END
  END VSSD
  OBS
    LAYER MET1 ;
      RECT 0 0 30 119.5 ;
    LAYER VIA1 ;
      RECT 0 0 30 119.5 ;
    LAYER MET2 ;
      RECT 0 0 30 119.5 ;
    LAYER VIA2 ;
      RECT 0 0 30 119.5 ;
    LAYER MET3 ;
      RECT 0 0 30 119.5 ;
    LAYER VIA3 ;
      RECT 0 0 30 119.5 ;
    LAYER MET4 ;
      RECT 0 0 30 119.5 ;
  END
END PDISDU

MACRO PFILL0001
  CLASS PAD SPACER ;
  ORIGIN 0 0 ;
  FOREIGN PFILL0001 0 0 ;
  SIZE 0.001 BY 119.5 ;
  SYMMETRY X Y R90 ;
  SITE IOSite ;
  PIN POC
    DIRECTION INOUT ;
    USE GROUND ;
    PORT
      LAYER MET4 ;
        RECT 0 107.15 0.001 107.65 ;
    END
  END POC
  PIN VDD
    DIRECTION INOUT ;
    USE POWER ;
    PORT
      CLASS CORE ;
      LAYER MET4 ;
        RECT 0 113.3 0.001 116.8 ;
    END
    PORT
      LAYER MET4 ;
        RECT 0 108.4 0.001 111.9 ;
    END
  END VDD
  PIN VDDD
    DIRECTION INOUT ;
    USE POWER ;
    PORT
      LAYER MET4 ;
        RECT 0 39.2 0.001 42.7 ;
        RECT 0 44.1 0.001 47.6 ;
        RECT 0 49 0.001 52.5 ;
        RECT 0 53.9 0.001 57.4 ;
        RECT 0 58.8 0.001 62.3 ;
        RECT 0 63.7 0.001 67.2 ;
        RECT 0 68.6 0.001 72.1 ;
        RECT 0 73.415 0.001 76.915 ;
        RECT 0 78.315 0.001 81.815 ;
        RECT 0 83.215 0.001 86.715 ;
    END
  END VDDD
  PIN VSS
    DIRECTION INOUT ;
    USE GROUND ;
    PORT
      LAYER MET4 ;
        RECT 0 88.115 0.001 91.615 ;
        RECT 0 93.1 0.001 96.6 ;
        RECT 0 98 0.001 101.5 ;
        RECT 0 102.9 0.001 106.4 ;
    END
  END VSS
  PIN VSSD
    DIRECTION INOUT ;
    USE GROUND ;
    PORT
      LAYER MET4 ;
        RECT 0 0 0.001 3.5 ;
        RECT 0 4.9 0.001 8.4 ;
        RECT 0 9.8 0.001 13.3 ;
        RECT 0 14.7 0.001 18.2 ;
        RECT 0 19.6 0.001 23.1 ;
        RECT 0 24.5 0.001 28 ;
        RECT 0 29.4 0.001 32.9 ;
    END
  END VSSD
  OBS
    LAYER MET1 ;
      RECT 0 0 0.001 119.5 ;
    LAYER VIA1 ;
      RECT 0 0 0.001 119.5 ;
    LAYER MET2 ;
      RECT 0 0 0.001 119.5 ;
    LAYER VIA2 ;
      RECT 0 0 0.001 119.5 ;
    LAYER MET3 ;
      RECT 0 0 0.001 119.5 ;
    LAYER VIA3 ;
      RECT 0 0 0.001 119.5 ;
    LAYER MET4 ;
      RECT 0 0 0.001 119.5 ;
  END
END PFILL0001

MACRO PFILL0005
  CLASS PAD SPACER ;
  ORIGIN 0 0 ;
  FOREIGN PFILL0005 0 0 ;
  SIZE 0.005 BY 119.5 ;
  SYMMETRY X Y R90 ;
  SITE IOSite ;
  PIN POC
    DIRECTION INOUT ;
    USE GROUND ;
    PORT
      LAYER MET4 ;
        RECT 0 107.15 0.005 107.65 ;
    END
  END POC
  PIN VDD
    DIRECTION INOUT ;
    USE POWER ;
    PORT
      CLASS CORE ;
      LAYER MET4 ;
        RECT 0 113.3 0.005 116.8 ;
    END
    PORT
      LAYER MET4 ;
        RECT 0 108.4 0.005 111.9 ;
    END
  END VDD
  PIN VDDD
    DIRECTION INOUT ;
    USE POWER ;
    PORT
      LAYER MET4 ;
        RECT 0 39.2 0.005 42.7 ;
        RECT 0 44.1 0.005 47.6 ;
        RECT 0 49 0.005 52.5 ;
        RECT 0 53.9 0.005 57.4 ;
        RECT 0 58.8 0.005 62.3 ;
        RECT 0 63.7 0.005 67.2 ;
        RECT 0 68.6 0.005 72.1 ;
        RECT 0 73.415 0.005 76.915 ;
        RECT 0 78.315 0.005 81.815 ;
        RECT 0 83.215 0.005 86.715 ;
    END
  END VDDD
  PIN VSS
    DIRECTION INOUT ;
    USE GROUND ;
    PORT
      LAYER MET4 ;
        RECT 0 88.115 0.005 91.615 ;
        RECT 0 93.1 0.005 96.6 ;
        RECT 0 98 0.005 101.5 ;
        RECT 0 102.9 0.005 106.4 ;
    END
  END VSS
  PIN VSSD
    DIRECTION INOUT ;
    USE GROUND ;
    PORT
      LAYER MET4 ;
        RECT 0 0 0.005 3.5 ;
        RECT 0 4.9 0.005 8.4 ;
        RECT 0 9.8 0.005 13.3 ;
        RECT 0 14.7 0.005 18.2 ;
        RECT 0 19.6 0.005 23.1 ;
        RECT 0 24.5 0.005 28 ;
        RECT 0 29.4 0.005 32.9 ;
    END
  END VSSD
  OBS
    LAYER MET1 ;
      RECT 0 0 0.005 119.5 ;
    LAYER VIA1 ;
      RECT 0 0 0.005 119.5 ;
    LAYER MET2 ;
      RECT 0 0 0.005 119.5 ;
    LAYER VIA2 ;
      RECT 0 0 0.005 119.5 ;
    LAYER MET3 ;
      RECT 0 0 0.005 119.5 ;
    LAYER VIA3 ;
      RECT 0 0 0.005 119.5 ;
    LAYER MET4 ;
      RECT 0 0 0.005 119.5 ;
  END
END PFILL0005

MACRO PFILL001
  CLASS PAD SPACER ;
  ORIGIN 0 0 ;
  FOREIGN PFILL001 0 0 ;
  SIZE 0.01 BY 119.5 ;
  SYMMETRY X Y R90 ;
  SITE IOSite ;
  PIN POC
    DIRECTION INOUT ;
    USE GROUND ;
    PORT
      LAYER MET4 ;
        RECT 0 107.15 0.01 107.65 ;
    END
  END POC
  PIN VDD
    DIRECTION INOUT ;
    USE POWER ;
    PORT
      CLASS CORE ;
      LAYER MET4 ;
        RECT 0 113.3 0.01 116.8 ;
    END
    PORT
      LAYER MET4 ;
        RECT 0 108.4 0.01 111.9 ;
    END
  END VDD
  PIN VDDD
    DIRECTION INOUT ;
    USE POWER ;
    PORT
      LAYER MET4 ;
        RECT 0 39.2 0.01 42.7 ;
        RECT 0 44.1 0.01 47.6 ;
        RECT 0 49 0.01 52.5 ;
        RECT 0 53.9 0.01 57.4 ;
        RECT 0 58.8 0.01 62.3 ;
        RECT 0 63.7 0.01 67.2 ;
        RECT 0 68.6 0.01 72.1 ;
        RECT 0 73.415 0.01 76.915 ;
        RECT 0 78.315 0.01 81.815 ;
        RECT 0 83.215 0.01 86.715 ;
    END
  END VDDD
  PIN VSS
    DIRECTION INOUT ;
    USE GROUND ;
    PORT
      LAYER MET4 ;
        RECT 0 88.115 0.01 91.615 ;
        RECT 0 93.1 0.01 96.6 ;
        RECT 0 98 0.01 101.5 ;
        RECT 0 102.9 0.01 106.4 ;
    END
  END VSS
  PIN VSSD
    DIRECTION INOUT ;
    USE GROUND ;
    PORT
      LAYER MET4 ;
        RECT 0 0 0.01 3.5 ;
        RECT 0 4.9 0.01 8.4 ;
        RECT 0 9.8 0.01 13.3 ;
        RECT 0 14.7 0.01 18.2 ;
        RECT 0 19.6 0.01 23.1 ;
        RECT 0 24.5 0.01 28 ;
        RECT 0 29.4 0.01 32.9 ;
    END
  END VSSD
  OBS
    LAYER MET1 ;
      RECT 0 0 0.01 119.5 ;
    LAYER VIA1 ;
      RECT 0 0 0.01 119.5 ;
    LAYER MET2 ;
      RECT 0 0 0.01 119.5 ;
    LAYER VIA2 ;
      RECT 0 0 0.01 119.5 ;
    LAYER MET3 ;
      RECT 0 0 0.01 119.5 ;
    LAYER VIA3 ;
      RECT 0 0 0.01 119.5 ;
    LAYER MET4 ;
      RECT 0 0 0.01 119.5 ;
  END
END PFILL001

MACRO PFILL01
  CLASS PAD SPACER ;
  ORIGIN 0 0 ;
  FOREIGN PFILL01 0 0 ;
  SIZE 0.1 BY 119.5 ;
  SYMMETRY X Y R90 ;
  SITE IOSite ;
  PIN POC
    DIRECTION INOUT ;
    USE GROUND ;
    PORT
      LAYER MET4 ;
        RECT 0 107.15 0.1 107.65 ;
    END
  END POC
  PIN VDD
    DIRECTION INOUT ;
    USE POWER ;
    PORT
      CLASS CORE ;
      LAYER MET4 ;
        RECT 0 113.3 0.1 116.8 ;
    END
    PORT
      LAYER MET4 ;
        RECT 0 108.4 0.1 111.9 ;
    END
  END VDD
  PIN VDDD
    DIRECTION INOUT ;
    USE POWER ;
    PORT
      LAYER MET4 ;
        RECT 0 39.2 0.1 42.7 ;
        RECT 0 44.1 0.1 47.6 ;
        RECT 0 49 0.1 52.5 ;
        RECT 0 53.9 0.1 57.4 ;
        RECT 0 58.8 0.1 62.3 ;
        RECT 0 63.7 0.1 67.2 ;
        RECT 0 68.6 0.1 72.1 ;
        RECT 0 73.415 0.1 76.915 ;
        RECT 0 78.315 0.1 81.815 ;
        RECT 0 83.215 0.1 86.715 ;
    END
  END VDDD
  PIN VSS
    DIRECTION INOUT ;
    USE GROUND ;
    PORT
      LAYER MET4 ;
        RECT 0 88.115 0.1 91.615 ;
        RECT 0 93.1 0.1 96.6 ;
        RECT 0 98 0.1 101.5 ;
        RECT 0 102.9 0.1 106.4 ;
    END
  END VSS
  PIN VSSD
    DIRECTION INOUT ;
    USE GROUND ;
    PORT
      LAYER MET4 ;
        RECT 0 0 0.1 3.5 ;
        RECT 0 4.9 0.1 8.4 ;
        RECT 0 9.8 0.1 13.3 ;
        RECT 0 14.7 0.1 18.2 ;
        RECT 0 19.6 0.1 23.1 ;
        RECT 0 24.5 0.1 28 ;
        RECT 0 29.4 0.1 32.9 ;
    END
  END VSSD
  OBS
    LAYER MET1 ;
      RECT 0 0 0.1 119.5 ;
    LAYER VIA1 ;
      RECT 0 0 0.1 119.5 ;
    LAYER MET2 ;
      RECT 0 0 0.1 119.5 ;
    LAYER VIA2 ;
      RECT 0 0 0.1 119.5 ;
    LAYER MET3 ;
      RECT 0 0 0.1 119.5 ;
    LAYER VIA3 ;
      RECT 0 0 0.1 119.5 ;
    LAYER MET4 ;
      RECT 0 0 0.1 119.5 ;
  END
END PFILL01

MACRO PFILL1
  CLASS PAD SPACER ;
  ORIGIN 0 0 ;
  FOREIGN PFILL1 0 0 ;
  SIZE 1 BY 119.5 ;
  SYMMETRY X Y R90 ;
  SITE IOSite ;
  PIN POC
    DIRECTION INOUT ;
    USE GROUND ;
    PORT
      LAYER MET4 ;
        RECT 0 107.15 1 107.65 ;
    END
  END POC
  PIN VDD
    DIRECTION INOUT ;
    USE POWER ;
    PORT
      CLASS CORE ;
      LAYER MET4 ;
        RECT 0 113.3 1 116.8 ;
    END
    PORT
      LAYER MET4 ;
        RECT 0 108.4 1 111.9 ;
    END
  END VDD
  PIN VDDD
    DIRECTION INOUT ;
    USE POWER ;
    PORT
      LAYER MET4 ;
        RECT 0 39.2 1 42.7 ;
        RECT 0 44.1 1 47.6 ;
        RECT 0 49 1 52.5 ;
        RECT 0 53.9 1 57.4 ;
        RECT 0 58.8 1 62.3 ;
        RECT 0 63.7 1 67.2 ;
        RECT 0 68.6 1 72.1 ;
        RECT 0 73.415 1 76.915 ;
        RECT 0 78.315 1 81.815 ;
        RECT 0 83.215 1 86.715 ;
    END
  END VDDD
  PIN VSS
    DIRECTION INOUT ;
    USE GROUND ;
    PORT
      LAYER MET4 ;
        RECT 0 88.115 1 91.615 ;
        RECT 0 93.1 1 96.6 ;
        RECT 0 98 1 101.5 ;
        RECT 0 102.9 1 106.4 ;
    END
  END VSS
  PIN VSSD
    DIRECTION INOUT ;
    USE GROUND ;
    PORT
      LAYER MET4 ;
        RECT 0 0 1 3.5 ;
        RECT 0 4.9 1 8.4 ;
        RECT 0 9.8 1 13.3 ;
        RECT 0 14.7 1 18.2 ;
        RECT 0 19.6 1 23.1 ;
        RECT 0 24.5 1 28 ;
        RECT 0 29.4 1 32.9 ;
    END
  END VSSD
  OBS
    LAYER MET1 ;
      RECT 0 0 1 119.5 ;
    LAYER VIA1 ;
      RECT 0 0 1 119.5 ;
    LAYER MET2 ;
      RECT 0 0 1 119.5 ;
    LAYER VIA2 ;
      RECT 0 0 1 119.5 ;
    LAYER MET3 ;
      RECT 0 0 1 119.5 ;
    LAYER VIA3 ;
      RECT 0 0 1 119.5 ;
    LAYER MET4 ;
      RECT 0 0 1 119.5 ;
  END
END PFILL1

MACRO PFILL10
  CLASS PAD SPACER ;
  ORIGIN 0 0 ;
  FOREIGN PFILL10 0 0 ;
  SIZE 10 BY 119.5 ;
  SYMMETRY X Y R90 ;
  SITE IOSite ;
  PIN POC
    DIRECTION INOUT ;
    USE GROUND ;
    PORT
      LAYER MET4 ;
        RECT 9 107.15 10 107.65 ;
        RECT 0 107.15 1 107.65 ;
    END
  END POC
  PIN VDD
    DIRECTION INOUT ;
    USE POWER ;
    PORT
      CLASS CORE ;
      LAYER MET4 ;
        RECT 9 113.3 10 116.8 ;
        RECT 0 113.3 1 116.8 ;
    END
    PORT
      LAYER MET4 ;
        RECT 9 108.4 10 111.9 ;
        RECT 0 108.4 1 111.9 ;
    END
  END VDD
  PIN VDDD
    DIRECTION INOUT ;
    USE POWER ;
    PORT
      LAYER MET4 ;
        RECT 9 39.2 10 42.7 ;
        RECT 9 44.1 10 47.6 ;
        RECT 9 49 10 52.5 ;
        RECT 9 53.9 10 57.4 ;
        RECT 9 58.8 10 62.3 ;
        RECT 9 63.7 10 67.2 ;
        RECT 9 68.6 10 72.1 ;
        RECT 9 73.415 10 76.915 ;
        RECT 9 78.315 10 81.815 ;
        RECT 9 83.215 10 86.715 ;
        RECT 0 39.2 1 42.7 ;
        RECT 0 44.1 1 47.6 ;
        RECT 0 49 1 52.5 ;
        RECT 0 53.9 1 57.4 ;
        RECT 0 58.8 1 62.3 ;
        RECT 0 63.7 1 67.2 ;
        RECT 0 68.6 1 72.1 ;
        RECT 0 73.415 1 76.915 ;
        RECT 0 78.315 1 81.815 ;
        RECT 0 83.215 1 86.715 ;
    END
  END VDDD
  PIN VSS
    DIRECTION INOUT ;
    USE GROUND ;
    PORT
      LAYER MET4 ;
        RECT 9 88.115 10 91.615 ;
        RECT 9 93.1 10 96.6 ;
        RECT 9 98 10 101.5 ;
        RECT 9 102.9 10 106.4 ;
        RECT 0 88.115 1 91.615 ;
        RECT 0 93.1 1 96.6 ;
        RECT 0 98 1 101.5 ;
        RECT 0 102.9 1 106.4 ;
    END
  END VSS
  PIN VSSD
    DIRECTION INOUT ;
    USE GROUND ;
    PORT
      LAYER MET4 ;
        RECT 9 0 10 3.5 ;
        RECT 9 4.9 10 8.4 ;
        RECT 9 9.8 10 13.3 ;
        RECT 9 14.7 10 18.2 ;
        RECT 9 19.6 10 23.1 ;
        RECT 9 24.5 10 28 ;
        RECT 9 29.4 10 32.9 ;
        RECT 0 0 1 3.5 ;
        RECT 0 4.9 1 8.4 ;
        RECT 0 9.8 1 13.3 ;
        RECT 0 14.7 1 18.2 ;
        RECT 0 19.6 1 23.1 ;
        RECT 0 24.5 1 28 ;
        RECT 0 29.4 1 32.9 ;
    END
  END VSSD
  OBS
    LAYER MET1 ;
      RECT 0 0 10 119.5 ;
    LAYER VIA1 ;
      RECT 0 0 10 119.5 ;
    LAYER MET2 ;
      RECT 0 0 10 119.5 ;
    LAYER VIA2 ;
      RECT 0 0 10 119.5 ;
    LAYER MET3 ;
      RECT 0 0 10 119.5 ;
    LAYER VIA3 ;
      RECT 0 0 10 119.5 ;
    LAYER MET4 ;
      RECT 0 0 10 119.5 ;
  END
END PFILL10

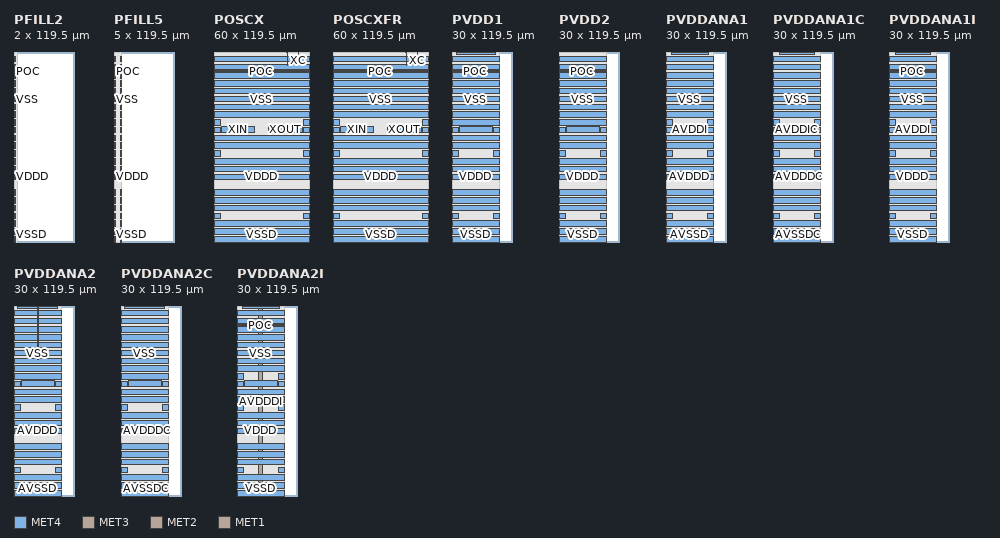
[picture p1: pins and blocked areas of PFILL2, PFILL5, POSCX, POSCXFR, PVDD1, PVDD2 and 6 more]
MACRO PFILL2
  CLASS PAD SPACER ;
  ORIGIN 0 0 ;
  FOREIGN PFILL2 0 0 ;
  SIZE 2 BY 119.5 ;
  SYMMETRY X Y R90 ;
  SITE IOSite ;
  PIN POC
    DIRECTION INOUT ;
    USE GROUND ;
    PORT
      LAYER MET4 ;
        RECT 0 107.15 1 107.65 ;
    END
  END POC
  PIN VDD
    DIRECTION INOUT ;
    USE POWER ;
    PORT
      CLASS CORE ;
      LAYER MET4 ;
        RECT 0 113.3 1 116.8 ;
    END
    PORT
      LAYER MET4 ;
        RECT 0 108.4 1 111.9 ;
    END
  END VDD
  PIN VDDD
    DIRECTION INOUT ;
    USE POWER ;
    PORT
      LAYER MET4 ;
        RECT 0 39.2 1 42.7 ;
        RECT 0 44.1 1 47.6 ;
        RECT 0 49 1 52.5 ;
        RECT 0 53.9 1 57.4 ;
        RECT 0 58.8 1 62.3 ;
        RECT 0 63.7 1 67.2 ;
        RECT 0 68.6 1 72.1 ;
        RECT 0 73.415 1 76.915 ;
        RECT 0 78.315 1 81.815 ;
        RECT 0 83.215 1 86.715 ;
    END
  END VDDD
  PIN VSS
    DIRECTION INOUT ;
    USE GROUND ;
    PORT
      LAYER MET4 ;
        RECT 0 88.115 1 91.615 ;
        RECT 0 93.1 1 96.6 ;
        RECT 0 98 1 101.5 ;
        RECT 0 102.9 1 106.4 ;
    END
  END VSS
  PIN VSSD
    DIRECTION INOUT ;
    USE GROUND ;
    PORT
      LAYER MET4 ;
        RECT 0 0 1 3.5 ;
        RECT 0 4.9 1 8.4 ;
        RECT 0 9.8 1 13.3 ;
        RECT 0 14.7 1 18.2 ;
        RECT 0 19.6 1 23.1 ;
        RECT 0 24.5 1 28 ;
        RECT 0 29.4 1 32.9 ;
    END
  END VSSD
  OBS
    LAYER MET1 ;
      RECT 0 0 2 119.5 ;
    LAYER VIA1 ;
      RECT 0 0 2 119.5 ;
    LAYER MET2 ;
      RECT 0 0 2 119.5 ;
    LAYER VIA2 ;
      RECT 0 0 2 119.5 ;
    LAYER MET3 ;
      RECT 0 0 2 119.5 ;
    LAYER VIA3 ;
      RECT 0 0 2 119.5 ;
    LAYER MET4 ;
      RECT 0 0 2 119.5 ;
  END
END PFILL2

MACRO PFILL5
  CLASS PAD SPACER ;
  ORIGIN 0 0 ;
  FOREIGN PFILL5 0 0 ;
  SIZE 5 BY 119.5 ;
  SYMMETRY X Y R90 ;
  SITE IOSite ;
  PIN POC
    DIRECTION INOUT ;
    USE GROUND ;
    PORT
      LAYER MET4 ;
        RECT 4 107.15 5 107.65 ;
        RECT 0 107.15 1 107.65 ;
    END
  END POC
  PIN VDD
    DIRECTION INOUT ;
    USE POWER ;
    PORT
      CLASS CORE ;
      LAYER MET4 ;
        RECT 4 113.3 5 116.8 ;
        RECT 0 113.3 1 116.8 ;
    END
    PORT
      LAYER MET4 ;
        RECT 4 108.4 5 111.9 ;
        RECT 0 108.4 1 111.9 ;
    END
  END VDD
  PIN VDDD
    DIRECTION INOUT ;
    USE POWER ;
    PORT
      LAYER MET4 ;
        RECT 4 39.2 5 42.7 ;
        RECT 4 44.1 5 47.6 ;
        RECT 4 49 5 52.5 ;
        RECT 4 53.9 5 57.4 ;
        RECT 4 58.8 5 62.3 ;
        RECT 4 63.7 5 67.2 ;
        RECT 4 68.6 5 72.1 ;
        RECT 4 73.415 5 76.915 ;
        RECT 4 78.315 5 81.815 ;
        RECT 4 83.215 5 86.715 ;
        RECT 0 39.2 1 42.7 ;
        RECT 0 44.1 1 47.6 ;
        RECT 0 49 1 52.5 ;
        RECT 0 53.9 1 57.4 ;
        RECT 0 58.8 1 62.3 ;
        RECT 0 63.7 1 67.2 ;
        RECT 0 68.6 1 72.1 ;
        RECT 0 73.415 1 76.915 ;
        RECT 0 78.315 1 81.815 ;
        RECT 0 83.215 1 86.715 ;
    END
  END VDDD
  PIN VSS
    DIRECTION INOUT ;
    USE GROUND ;
    PORT
      LAYER MET4 ;
        RECT 4 88.115 5 91.615 ;
        RECT 4 93.1 5 96.6 ;
        RECT 4 98 5 101.5 ;
        RECT 4 102.9 5 106.4 ;
        RECT 0 88.115 1 91.615 ;
        RECT 0 93.1 1 96.6 ;
        RECT 0 98 1 101.5 ;
        RECT 0 102.9 1 106.4 ;
    END
  END VSS
  PIN VSSD
    DIRECTION INOUT ;
    USE GROUND ;
    PORT
      LAYER MET4 ;
        RECT 4 0 5 3.5 ;
        RECT 4 4.9 5 8.4 ;
        RECT 4 9.8 5 13.3 ;
        RECT 4 14.7 5 18.2 ;
        RECT 4 19.6 5 23.1 ;
        RECT 4 24.5 5 28 ;
        RECT 4 29.4 5 32.9 ;
        RECT 0 0 1 3.5 ;
        RECT 0 4.9 1 8.4 ;
        RECT 0 9.8 1 13.3 ;
        RECT 0 14.7 1 18.2 ;
        RECT 0 19.6 1 23.1 ;
        RECT 0 24.5 1 28 ;
        RECT 0 29.4 1 32.9 ;
    END
  END VSSD
  OBS
    LAYER MET1 ;
      RECT 0 0 5 119.5 ;
    LAYER VIA1 ;
      RECT 0 0 5 119.5 ;
    LAYER MET2 ;
      RECT 0 0 5 119.5 ;
    LAYER VIA2 ;
      RECT 0 0 5 119.5 ;
    LAYER MET3 ;
      RECT 0 0 5 119.5 ;
    LAYER VIA3 ;
      RECT 0 0 5 119.5 ;
    LAYER MET4 ;
      RECT 0 0 5 119.5 ;
  END
END PFILL5

MACRO POSCX
  CLASS PAD ;
  ORIGIN 0 0 ;
  FOREIGN POSCX 0 0 ;
  SIZE 60 BY 119.5 ;
  SYMMETRY X Y R90 ;
  SITE IOSite ;
  PIN E
    DIRECTION INPUT ;
    USE SIGNAL ;
    ANTENNAPARTIALMETALSIDEAREA 0.1764 LAYER MET1 ;
    ANTENNAPARTIALCUTAREA 0.0162 LAYER VIA3 ;
    ANTENNAPARTIALCUTAREA 0.0162 LAYER VIA2 ;
    ANTENNAPARTIALCUTAREA 0.0162 LAYER VIA1 ;
    ANTENNAMODEL OXIDE1 ;
      ANTENNAGATEAREA 0.468 LAYER MET2 ;
      ANTENNAGATEAREA 0.468 LAYER MET3 ;
      ANTENNAGATEAREA 0.18 LAYER MET1 ;
      ANTENNAGATEAREA 0.468 LAYER MET4 ;
      ANTENNAMAXAREACAR 0.545 LAYER MET2 ;
      ANTENNAMAXAREACAR 5.989444 LAYER MET3 ;
      ANTENNAMAXAREACAR 6.267222 LAYER MET4 ;
      ANTENNAMAXSIDEAREACAR 2.36 LAYER MET2 ;
      ANTENNAMAXSIDEAREACAR 10.275385 LAYER MET3 ;
      ANTENNAMAXSIDEAREACAR 0.84 LAYER MET1 ;
      ANTENNAMAXSIDEAREACAR 10.957436 LAYER MET4 ;
      ANTENNAMAXCUTCAR 0.159231 LAYER VIA3 ;
      ANTENNAMAXCUTCAR 0.124615 LAYER VIA2 ;
      ANTENNAMAXCUTCAR 0.09 LAYER VIA1 ;
    PORT
      LAYER MET4 ;
        RECT 45.805 119.24 46.305 119.5 ;
      LAYER MET3 ;
        RECT 45.805 119.24 46.305 119.5 ;
      LAYER MET2 ;
        RECT 45.805 119.24 46.305 119.5 ;
        RECT 46.005 111.18 46.305 119.5 ;
      LAYER MET1 ;
        RECT 45.805 119.24 46.305 119.5 ;
    END
  END E
  PIN XC
    DIRECTION OUTPUT ;
    USE SIGNAL ;
    ANTENNAPARTIALMETALAREA 0.3145 LAYER MET1 ;
    ANTENNAPARTIALMETALAREA 9.3481 LAYER MET2 ;
    ANTENNAPARTIALMETALSIDEAREA 0.7272 LAYER MET1 ;
    ANTENNAPARTIALMETALSIDEAREA 21 LAYER MET2 ;
    ANTENNAPARTIALCUTAREA 0.0162 LAYER VIA3 ;
    ANTENNAPARTIALCUTAREA 0.0162 LAYER VIA2 ;
    ANTENNAPARTIALCUTAREA 0.0729 LAYER VIA1 ;
    ANTENNADIFFAREA 3.54 LAYER MET2 ;
    ANTENNADIFFAREA 3.54 LAYER MET3 ;
    ANTENNADIFFAREA 0.23 LAYER MET1 ;
    ANTENNADIFFAREA 3.54 LAYER MET4 ;
    PORT
      LAYER MET4 ;
        RECT 52.86 119.24 53.36 119.5 ;
      LAYER MET3 ;
        RECT 52.86 119.24 53.36 119.5 ;
      LAYER MET2 ;
        RECT 52.86 117.75 53.36 119.5 ;
      LAYER MET1 ;
        RECT 52.86 119.24 53.36 119.5 ;
    END
  END XC
  PIN POC
    DIRECTION INPUT ;
    USE GROUND ;
    PORT
      LAYER MET4 ;
        RECT 0 107.15 60 107.65 ;
    END
  END POC
  PIN VDD
    DIRECTION INOUT ;
    USE POWER ;
    PORT
      CLASS CORE ;
      LAYER MET4 ;
        RECT 0 113.3 60 116.8 ;
    END
    PORT
      LAYER MET4 ;
        RECT 0 108.4 60 111.9 ;
    END
  END VDD
  PIN VDDD
    DIRECTION INOUT ;
    USE POWER ;
    PORT
      LAYER MET4 ;
        RECT 0 39.2 60 42.7 ;
        RECT 0 44.1 60 47.6 ;
        RECT 0 49 60 52.5 ;
        RECT 56 53.9 60 57.4 ;
        RECT 0 58.8 60 62.3 ;
        RECT 0 63.7 60 67.2 ;
        RECT 56 68.6 60 72.1 ;
        RECT 56 73.415 60 76.915 ;
        RECT 0 78.315 60 81.815 ;
        RECT 0 83.215 60 86.715 ;
        RECT 0 53.9 4 57.4 ;
        RECT 0 68.6 4 72.1 ;
        RECT 0 73.415 4 76.915 ;
    END
  END VDDD
  PIN VSS
    DIRECTION INOUT ;
    USE GROUND ;
    PORT
      LAYER MET4 ;
        RECT 0 88.115 60 91.615 ;
        RECT 0 93.1 60 96.6 ;
        RECT 0 98 60 101.5 ;
        RECT 0 102.9 60 106.4 ;
    END
  END VSS
  PIN VSSD
    DIRECTION INOUT ;
    USE GROUND ;
    PORT
      LAYER MET4 ;
        RECT 0 0 60 3.5 ;
        RECT 0 4.9 60 8.4 ;
        RECT 0 9.8 60 13.3 ;
        RECT 56 14.7 60 18.2 ;
        RECT 0 19.6 60 23.1 ;
        RECT 0 24.5 60 28 ;
        RECT 0 29.4 60 32.9 ;
        RECT 0 14.7 4 18.2 ;
    END
  END VSSD
  PIN XIN
    DIRECTION INPUT ;
    USE SIGNAL ;
    ANTENNAPARTIALMETALAREA 239.4 LAYER MET4 ;
    ANTENNAPARTIALMETALSIDEAREA 31.248 LAYER MET4 ;
    ANTENNADIFFAREA 763.128 LAYER MET4 ;
    ANTENNAMODEL OXIDE1 ;
      ANTENNAGATEAREA 52 LAYER MET4 ;
      ANTENNAMAXAREACAR 13.278265 LAYER MET4 ;
      ANTENNAMAXSIDEAREACAR 3.208058 LAYER MET4 ;
    PORT
      LAYER MET4 ;
        RECT 4.5 68.6 25.5 72.415 ;
    END
  END XIN
  PIN XOUT
    DIRECTION OUTPUT ;
    USE SIGNAL ;
    ANTENNAPARTIALMETALAREA 239.4 LAYER MET4 ;
    ANTENNAPARTIALMETALSIDEAREA 31.248 LAYER MET4 ;
    ANTENNADIFFAREA 815.44 LAYER MET4 ;
    ANTENNAMODEL OXIDE1 ;
      ANTENNAGATEAREA 14.56 LAYER MET4 ;
      ANTENNAMAXAREACAR 45.913997 LAYER MET4 ;
      ANTENNAMAXSIDEAREACAR 10.422449 LAYER MET4 ;
    PORT
      LAYER MET4 ;
        RECT 34.5 68.6 55.5 72.415 ;
    END
  END XOUT
  OBS
    LAYER MET1 ;
      RECT 0 0 60 119.5 ;
    LAYER VIA1 ;
      RECT 0 0 60 119.5 ;
    LAYER MET2 ;
      RECT 0 0 60 119.5 ;
    LAYER VIA2 ;
      RECT 0 0 60 119.5 ;
    LAYER MET3 ;
      RECT 0 0 60 119.5 ;
    LAYER VIA3 ;
      RECT 0 0 60 119.5 ;
    LAYER MET4 ;
      RECT 0 0 60 119.5 ;
  END
END POSCX

MACRO POSCXFR
  CLASS PAD ;
  ORIGIN 0 0 ;
  FOREIGN POSCXFR 0 0 ;
  SIZE 60 BY 119.5 ;
  SYMMETRY X Y R90 ;
  SITE IOSite ;
  PIN E
    DIRECTION INPUT ;
    USE SIGNAL ;
    ANTENNAPARTIALMETALSIDEAREA 0.1764 LAYER MET1 ;
    ANTENNAPARTIALCUTAREA 0.0162 LAYER VIA3 ;
    ANTENNAPARTIALCUTAREA 0.0162 LAYER VIA2 ;
    ANTENNAPARTIALCUTAREA 0.0162 LAYER VIA1 ;
    ANTENNAMODEL OXIDE1 ;
      ANTENNAGATEAREA 0.468 LAYER MET2 ;
      ANTENNAGATEAREA 0.468 LAYER MET3 ;
      ANTENNAGATEAREA 0.18 LAYER MET1 ;
      ANTENNAGATEAREA 0.468 LAYER MET4 ;
      ANTENNAMAXAREACAR 0.545 LAYER MET2 ;
      ANTENNAMAXAREACAR 5.989444 LAYER MET3 ;
      ANTENNAMAXAREACAR 6.267222 LAYER MET4 ;
      ANTENNAMAXSIDEAREACAR 2.36 LAYER MET2 ;
      ANTENNAMAXSIDEAREACAR 10.275385 LAYER MET3 ;
      ANTENNAMAXSIDEAREACAR 0.84 LAYER MET1 ;
      ANTENNAMAXSIDEAREACAR 10.957436 LAYER MET4 ;
      ANTENNAMAXCUTCAR 0.159231 LAYER VIA3 ;
      ANTENNAMAXCUTCAR 0.124615 LAYER VIA2 ;
      ANTENNAMAXCUTCAR 0.09 LAYER VIA1 ;
    PORT
      LAYER MET4 ;
        RECT 45.805 119.24 46.305 119.5 ;
      LAYER MET3 ;
        RECT 45.805 119.24 46.305 119.5 ;
      LAYER MET2 ;
        RECT 45.805 119.24 46.305 119.5 ;
        RECT 46.005 111.18 46.305 119.5 ;
      LAYER MET1 ;
        RECT 45.805 119.24 46.305 119.5 ;
    END
  END E
  PIN XC
    DIRECTION OUTPUT ;
    USE SIGNAL ;
    ANTENNAPARTIALMETALAREA 0.3145 LAYER MET1 ;
    ANTENNAPARTIALMETALAREA 9.3481 LAYER MET2 ;
    ANTENNAPARTIALMETALSIDEAREA 0.7272 LAYER MET1 ;
    ANTENNAPARTIALMETALSIDEAREA 21 LAYER MET2 ;
    ANTENNAPARTIALCUTAREA 0.0162 LAYER VIA3 ;
    ANTENNAPARTIALCUTAREA 0.0162 LAYER VIA2 ;
    ANTENNAPARTIALCUTAREA 0.0729 LAYER VIA1 ;
    ANTENNADIFFAREA 3.54 LAYER MET2 ;
    ANTENNADIFFAREA 3.54 LAYER MET3 ;
    ANTENNADIFFAREA 0.23 LAYER MET1 ;
    ANTENNADIFFAREA 3.54 LAYER MET4 ;
    PORT
      LAYER MET4 ;
        RECT 52.86 119.24 53.36 119.5 ;
      LAYER MET3 ;
        RECT 52.86 119.24 53.36 119.5 ;
      LAYER MET2 ;
        RECT 52.86 117.75 53.36 119.5 ;
      LAYER MET1 ;
        RECT 52.86 119.24 53.36 119.5 ;
    END
  END XC
  PIN POC
    DIRECTION INPUT ;
    USE GROUND ;
    PORT
      LAYER MET4 ;
        RECT 0 107.15 60 107.65 ;
    END
  END POC
  PIN VDD
    DIRECTION INOUT ;
    USE POWER ;
    PORT
      CLASS CORE ;
      LAYER MET4 ;
        RECT 0 113.3 60 116.8 ;
    END
    PORT
      LAYER MET4 ;
        RECT 0 108.4 60 111.9 ;
    END
  END VDD
  PIN VDDD
    DIRECTION INOUT ;
    USE POWER ;
    PORT
      LAYER MET4 ;
        RECT 0 39.2 60 42.7 ;
        RECT 0 44.1 60 47.6 ;
        RECT 0 49 60 52.5 ;
        RECT 56 53.9 60 57.4 ;
        RECT 0 58.8 60 62.3 ;
        RECT 0 63.7 60 67.2 ;
        RECT 56 68.6 60 72.1 ;
        RECT 56 73.415 60 76.915 ;
        RECT 0 78.315 60 81.815 ;
        RECT 0 83.215 60 86.715 ;
        RECT 0 53.9 4 57.4 ;
        RECT 0 68.6 4 72.1 ;
        RECT 0 73.415 4 76.915 ;
    END
  END VDDD
  PIN VSS
    DIRECTION INOUT ;
    USE GROUND ;
    PORT
      LAYER MET4 ;
        RECT 0 88.115 60 91.615 ;
        RECT 0 93.1 60 96.6 ;
        RECT 0 98 60 101.5 ;
        RECT 0 102.9 60 106.4 ;
    END
  END VSS
  PIN VSSD
    DIRECTION INOUT ;
    USE GROUND ;
    PORT
      LAYER MET4 ;
        RECT 0 0 60 3.5 ;
        RECT 0 4.9 60 8.4 ;
        RECT 0 9.8 60 13.3 ;
        RECT 56 14.7 60 18.2 ;
        RECT 0 19.6 60 23.1 ;
        RECT 0 24.5 60 28 ;
        RECT 0 29.4 60 32.9 ;
        RECT 0 14.7 4 18.2 ;
    END
  END VSSD
  PIN XIN
    DIRECTION INPUT ;
    USE SIGNAL ;
    ANTENNAPARTIALMETALAREA 558.915 LAYER MET4 ;
    ANTENNAPARTIALMETALSIDEAREA 72.9183 LAYER MET4 ;
    ANTENNADIFFAREA 1578.568 LAYER MET4 ;
    ANTENNAMODEL OXIDE1 ;
      ANTENNAGATEAREA 66.56 LAYER MET4 ;
      ANTENNAMAXAREACAR 26.018404 LAYER MET4 ;
      ANTENNAMAXSIDEAREACAR 6.323411 LAYER MET4 ;
    PORT
      LAYER MET4 ;
        RECT 4.5 68.6 25.5 72.415 ;
    END
  END XIN
  PIN XOUT
    DIRECTION OUTPUT ;
    USE SIGNAL ;
    ANTENNAPARTIALMETALAREA 558.915 LAYER MET4 ;
    ANTENNAPARTIALMETALSIDEAREA 72.9183 LAYER MET4 ;
    ANTENNADIFFAREA 1578.568 LAYER MET4 ;
    ANTENNAMODEL OXIDE1 ;
      ANTENNAGATEAREA 66.56 LAYER MET4 ;
      ANTENNAMAXAREACAR 22.491619 LAYER MET4 ;
      ANTENNAMAXSIDEAREACAR 5.275872 LAYER MET4 ;
    PORT
      LAYER MET4 ;
        RECT 34.5 68.6 55.5 72.415 ;
    END
  END XOUT
  OBS
    LAYER MET1 ;
      RECT 0 0 60 119.5 ;
    LAYER VIA1 ;
      RECT 0 0 60 119.5 ;
    LAYER MET2 ;
      RECT 0 0 60 119.5 ;
    LAYER VIA2 ;
      RECT 0 0 60 119.5 ;
    LAYER MET3 ;
      RECT 0 0 60 119.5 ;
    LAYER VIA3 ;
      RECT 0 0 60 119.5 ;
    LAYER MET4 ;
      RECT 0 0 60 119.5 ;
  END
END POSCXFR

MACRO PVDD1
  CLASS PAD ;
  ORIGIN 0 0 ;
  FOREIGN PVDD1 0 0 ;
  SIZE 30 BY 119.5 ;
  SYMMETRY X Y R90 ;
  SITE IOSite ;
  PIN VDD
    DIRECTION INOUT ;
    USE POWER ;
    PORT
      LAYER MET4 ;
        RECT 0 108.4 30 111.9 ;
        RECT 0 113.3 30 116.8 ;
        RECT 4.5 68.6 25.5 72.415 ;
    END
    PORT
      CLASS CORE ;
      LAYER MET2 ;
        RECT 2.6 117.8 27.4 119.5 ;
      LAYER MET3 ;
        RECT 2.6 117.8 27.4 119.5 ;
      LAYER MET4 ;
        RECT 2.6 117.8 27.4 119.5 ;
    END
  END VDD
  PIN POC
    DIRECTION INOUT ;
    USE GROUND ;
    PORT
      LAYER MET4 ;
        RECT 0 107.15 30 107.65 ;
    END
  END POC
  PIN VDDD
    DIRECTION INOUT ;
    USE POWER ;
    PORT
      LAYER MET4 ;
        RECT 0 39.2 30 42.7 ;
        RECT 0 44.1 30 47.6 ;
        RECT 0 49 30 52.5 ;
        RECT 26 53.9 30 57.4 ;
        RECT 0 58.8 30 62.3 ;
        RECT 0 63.7 30 67.2 ;
        RECT 26 68.6 30 72.1 ;
        RECT 0 73.415 30 76.915 ;
        RECT 0 78.315 30 81.815 ;
        RECT 0 83.215 30 86.715 ;
        RECT 0 53.9 4 57.4 ;
        RECT 0 68.6 4 72.1 ;
    END
  END VDDD
  PIN VSS
    DIRECTION INOUT ;
    USE GROUND ;
    PORT
      LAYER MET4 ;
        RECT 0 88.115 30 91.615 ;
        RECT 0 93.1 30 96.6 ;
        RECT 0 98 30 101.5 ;
        RECT 0 102.9 30 106.4 ;
    END
  END VSS
  PIN VSSD
    DIRECTION INOUT ;
    USE GROUND ;
    PORT
      LAYER MET4 ;
        RECT 0 0 30 3.5 ;
        RECT 0 4.9 30 8.4 ;
        RECT 0 9.8 30 13.3 ;
        RECT 26 14.7 30 18.2 ;
        RECT 0 19.6 30 23.1 ;
        RECT 0 24.5 30 28 ;
        RECT 0 29.4 30 32.9 ;
        RECT 0 14.7 4 18.2 ;
    END
  END VSSD
  OBS
    LAYER MET1 ;
      RECT 0 0 30 119.5 ;
    LAYER VIA1 ;
      RECT 0 0 30 119.5 ;
    LAYER MET2 ;
      RECT 0 0 30 119.5 ;
    LAYER VIA2 ;
      RECT 0 0 30 119.5 ;
    LAYER MET3 ;
      RECT 0 0 30 119.5 ;
    LAYER VIA3 ;
      RECT 0 0 30 119.5 ;
    LAYER MET4 ;
      RECT 0 0 30 119.5 ;
  END
END PVDD1

MACRO PVDD2
  CLASS PAD ;
  ORIGIN 0 0 ;
  FOREIGN PVDD2 0 0 ;
  SIZE 30 BY 119.5 ;
  SYMMETRY X Y R90 ;
  SITE IOSite ;
  PIN POC
    DIRECTION INOUT ;
    USE GROUND ;
    PORT
      LAYER MET4 ;
        RECT 0 107.15 30 107.65 ;
    END
  END POC
  PIN VDD
    DIRECTION INOUT ;
    USE POWER ;
    PORT
      CLASS CORE ;
      LAYER MET4 ;
        RECT 0 113.3 30 116.8 ;
    END
    PORT
      LAYER MET4 ;
        RECT 0 108.4 30 111.9 ;
    END
  END VDD
  PIN VDDD
    DIRECTION INOUT ;
    USE POWER ;
    PORT
      LAYER MET4 ;
        RECT 0 39.2 30 42.7 ;
        RECT 0 44.1 30 47.6 ;
        RECT 0 49 30 52.5 ;
        RECT 26 53.9 30 57.4 ;
        RECT 0 58.8 30 62.3 ;
        RECT 0 63.7 30 67.2 ;
        RECT 26 68.6 30 72.1 ;
        RECT 0 73.415 30 76.915 ;
        RECT 0 78.315 30 81.815 ;
        RECT 0 83.215 30 86.715 ;
        RECT 4.5 68.6 25.5 72.415 ;
        RECT 0 53.9 4 57.4 ;
        RECT 0 68.6 4 72.1 ;
    END
  END VDDD
  PIN VSS
    DIRECTION INOUT ;
    USE GROUND ;
    PORT
      LAYER MET4 ;
        RECT 0 88.115 30 91.615 ;
        RECT 0 93.1 30 96.6 ;
        RECT 0 98 30 101.5 ;
        RECT 0 102.9 30 106.4 ;
    END
  END VSS
  PIN VSSD
    DIRECTION INOUT ;
    USE GROUND ;
    PORT
      LAYER MET4 ;
        RECT 0 0 30 3.5 ;
        RECT 0 4.9 30 8.4 ;
        RECT 0 9.8 30 13.3 ;
        RECT 26 14.7 30 18.2 ;
        RECT 0 19.6 30 23.1 ;
        RECT 0 24.5 30 28 ;
        RECT 0 29.4 30 32.9 ;
        RECT 0 14.7 4 18.2 ;
    END
  END VSSD
  OBS
    LAYER MET1 ;
      RECT 0 0 30 119.5 ;
    LAYER VIA1 ;
      RECT 0 0 30 119.5 ;
    LAYER MET2 ;
      RECT 0 0 30 119.5 ;
    LAYER VIA2 ;
      RECT 0 0 30 119.5 ;
    LAYER MET3 ;
      RECT 0 0 30 119.5 ;
    LAYER VIA3 ;
      RECT 0 0 30 119.5 ;
    LAYER MET4 ;
      RECT 0 0 30 119.5 ;
  END
END PVDD2

MACRO PVDDANA1
  CLASS PAD ;
  ORIGIN 0 0 ;
  FOREIGN PVDDANA1 0 0 ;
  SIZE 30 BY 119.5 ;
  SYMMETRY X Y R90 ;
  SITE IOSite ;
  PIN AVDDI
    DIRECTION INOUT ;
    USE POWER ;
    PORT
      LAYER MET2 ;
        RECT 3.3 117.8 26.7 119.5 ;
      LAYER MET3 ;
        RECT 3.3 117.8 26.7 119.5 ;
      LAYER MET4 ;
        RECT 3.3 117.8 26.7 119.5 ;
        RECT 4.5 68.6 25.5 72.415 ;
    END
  END AVDDI
  PIN AVDDD
    DIRECTION INOUT ;
    USE POWER ;
    PORT
      LAYER MET4 ;
        RECT 0 39.2 30 42.7 ;
        RECT 0 44.1 30 47.6 ;
        RECT 0 49 30 52.5 ;
        RECT 26 53.9 30 57.4 ;
        RECT 0 58.8 30 62.3 ;
        RECT 0 63.7 30 67.2 ;
        RECT 26 68.6 30 72.1 ;
        RECT 26 73.415 30 76.915 ;
        RECT 0 78.315 30 81.815 ;
        RECT 0 83.215 30 86.715 ;
        RECT 0 108.4 30 111.9 ;
        RECT 0 113.3 30 116.8 ;
        RECT 0 53.9 4 57.4 ;
        RECT 0 68.6 4 72.1 ;
        RECT 0 73.415 4 76.915 ;
    END
  END AVDDD
  PIN AVSSD
    DIRECTION INOUT ;
    USE GROUND ;
    PORT
      LAYER MET4 ;
        RECT 0 0 30 3.5 ;
        RECT 0 4.9 30 8.4 ;
        RECT 0 9.8 30 13.3 ;
        RECT 26 14.7 30 18.2 ;
        RECT 0 19.6 30 23.1 ;
        RECT 0 24.5 30 28 ;
        RECT 0 29.4 30 32.9 ;
        RECT 0 14.7 4 18.2 ;
    END
  END AVSSD
  PIN VSS
    DIRECTION INOUT ;
    USE GROUND ;
    PORT
      LAYER MET4 ;
        RECT 0 88.115 30 91.615 ;
        RECT 0 93.1 30 96.6 ;
        RECT 0 98 30 101.5 ;
        RECT 0 102.9 30 106.4 ;
    END
  END VSS
  OBS
    LAYER MET1 ;
      RECT 0 0 30 119.5 ;
    LAYER VIA1 ;
      RECT 0 0 30 119.5 ;
    LAYER MET2 ;
      RECT 0 0 30 119.5 ;
    LAYER VIA2 ;
      RECT 0 0 30 119.5 ;
    LAYER MET3 ;
      RECT 0 0 30 119.5 ;
    LAYER VIA3 ;
      RECT 0 0 30 119.5 ;
    LAYER MET4 ;
      RECT 0 0 30 119.5 ;
  END
END PVDDANA1

MACRO PVDDANA1C
  CLASS PAD ;
  ORIGIN 0 0 ;
  FOREIGN PVDDANA1C 0 0 ;
  SIZE 30 BY 119.5 ;
  SYMMETRY X Y R90 ;
  SITE IOSite ;
  PIN AVDDIC
    DIRECTION INOUT ;
    USE POWER ;
    PORT
      LAYER MET2 ;
        RECT 3.79 117.8 26.21 119.5 ;
      LAYER MET3 ;
        RECT 3.79 117.8 26.21 119.5 ;
      LAYER MET4 ;
        RECT 3.79 117.8 26.21 119.5 ;
        RECT 4.5 68.6 25.5 72.415 ;
    END
  END AVDDIC
  PIN AVDDDC
    DIRECTION INOUT ;
    USE POWER ;
    PORT
      LAYER MET4 ;
        RECT 0 39.2 30 42.7 ;
        RECT 0 44.1 30 47.6 ;
        RECT 0 49 30 52.5 ;
        RECT 26 53.9 30 57.4 ;
        RECT 0 58.8 30 62.3 ;
        RECT 0 63.7 30 67.2 ;
        RECT 26 68.6 30 72.1 ;
        RECT 26 73.415 30 76.915 ;
        RECT 0 78.315 30 81.815 ;
        RECT 0 83.215 30 86.715 ;
        RECT 0 108.4 30 111.9 ;
        RECT 0 113.3 30 116.8 ;
        RECT 0 53.9 4 57.4 ;
        RECT 0 68.6 4 72.1 ;
        RECT 0 73.415 4 76.915 ;
    END
  END AVDDDC
  PIN AVSSDC
    DIRECTION INOUT ;
    USE GROUND ;
    PORT
      LAYER MET4 ;
        RECT 0 0 30 3.5 ;
        RECT 0 4.9 30 8.4 ;
        RECT 0 9.8 30 13.3 ;
        RECT 26 14.7 30 18.2 ;
        RECT 0 19.6 30 23.1 ;
        RECT 0 24.5 30 28 ;
        RECT 0 29.4 30 32.9 ;
        RECT 0 14.7 4 18.2 ;
    END
  END AVSSDC
  PIN VSS
    DIRECTION INOUT ;
    USE GROUND ;
    PORT
      LAYER MET4 ;
        RECT 0 88.115 30 91.615 ;
        RECT 0 93.1 30 96.6 ;
        RECT 0 98 30 101.5 ;
        RECT 0 102.9 30 106.4 ;
    END
  END VSS
  OBS
    LAYER MET1 ;
      RECT 0 0 30 119.5 ;
    LAYER VIA1 ;
      RECT 0 0 30 119.5 ;
    LAYER MET2 ;
      RECT 0 0 30 119.5 ;
    LAYER VIA2 ;
      RECT 0 0 30 119.5 ;
    LAYER MET3 ;
      RECT 0 0 30 119.5 ;
    LAYER VIA3 ;
      RECT 0 0 30 119.5 ;
    LAYER MET4 ;
      RECT 0 0 30 119.5 ;
  END
END PVDDANA1C

MACRO PVDDANA1I
  CLASS PAD ;
  ORIGIN 0 0 ;
  FOREIGN PVDDANA1I 0 0 ;
  SIZE 30 BY 119.5 ;
  SYMMETRY X Y R90 ;
  SITE IOSite ;
  PIN AVDDI
    DIRECTION INOUT ;
    USE POWER ;
    PORT
      LAYER MET2 ;
        RECT 3.79 117.8 26.21 119.5 ;
      LAYER MET3 ;
        RECT 3.79 117.8 26.21 119.5 ;
      LAYER MET4 ;
        RECT 3.79 117.8 26.21 119.5 ;
        RECT 4.5 68.6 25.5 72.415 ;
    END
  END AVDDI
  PIN POC
    DIRECTION INOUT ;
    USE GROUND ;
    PORT
      LAYER MET4 ;
        RECT 0 107.15 30 107.65 ;
    END
  END POC
  PIN VDD
    DIRECTION INOUT ;
    USE POWER ;
    PORT
      CLASS CORE ;
      LAYER MET4 ;
        RECT 0 113.3 30 116.8 ;
    END
    PORT
      LAYER MET4 ;
        RECT 0 108.4 30 111.9 ;
    END
  END VDD
  PIN VDDD
    DIRECTION INOUT ;
    USE POWER ;
    PORT
      LAYER MET4 ;
        RECT 0 39.2 30 42.7 ;
        RECT 0 44.1 30 47.6 ;
        RECT 0 49 30 52.5 ;
        RECT 26 53.9 30 57.4 ;
        RECT 0 58.8 30 62.3 ;
        RECT 0 63.7 30 67.2 ;
        RECT 26 68.6 30 72.1 ;
        RECT 26 73.415 30 76.915 ;
        RECT 0 78.315 30 81.815 ;
        RECT 0 83.215 30 86.715 ;
        RECT 0 53.9 4 57.4 ;
        RECT 0 68.6 4 72.1 ;
        RECT 0 73.415 4 76.915 ;
    END
  END VDDD
  PIN VSS
    DIRECTION INOUT ;
    USE GROUND ;
    PORT
      LAYER MET4 ;
        RECT 0 88.115 30 91.615 ;
        RECT 0 93.1 30 96.6 ;
        RECT 0 98 30 101.5 ;
        RECT 0 102.9 30 106.4 ;
    END
  END VSS
  PIN VSSD
    DIRECTION INOUT ;
    USE GROUND ;
    PORT
      LAYER MET4 ;
        RECT 0 0 30 3.5 ;
        RECT 0 4.9 30 8.4 ;
        RECT 0 9.8 30 13.3 ;
        RECT 26 14.7 30 18.2 ;
        RECT 0 19.6 30 23.1 ;
        RECT 0 24.5 30 28 ;
        RECT 0 29.4 30 32.9 ;
        RECT 0 14.7 4 18.2 ;
    END
  END VSSD
  OBS
    LAYER MET1 ;
      RECT 0 0 30 119.5 ;
    LAYER VIA1 ;
      RECT 0 0 30 119.5 ;
    LAYER MET2 ;
      RECT 0 0 30 119.5 ;
    LAYER VIA2 ;
      RECT 0 0 30 119.5 ;
    LAYER MET3 ;
      RECT 0 0 30 119.5 ;
    LAYER VIA3 ;
      RECT 0 0 30 119.5 ;
    LAYER MET4 ;
      RECT 0 0 30 119.5 ;
  END
END PVDDANA1I

MACRO PVDDANA2
  CLASS PAD ;
  ORIGIN 0 0 ;
  FOREIGN PVDDANA2 0 0 ;
  SIZE 30 BY 119.5 ;
  SYMMETRY X Y R90 ;
  SITE IOSite ;
  PIN AVDDD
    DIRECTION INOUT ;
    USE POWER ;
    PORT
      LAYER MET2 ;
        RECT 2.5 117.8 27.5 119.5 ;
      LAYER MET3 ;
        RECT 2.5 117.8 27.5 119.5 ;
        RECT 14.5 85.6 15.5 119.5 ;
      LAYER MET4 ;
        RECT 0 39.2 30 42.7 ;
        RECT 0 44.1 30 47.6 ;
        RECT 0 49 30 52.5 ;
        RECT 26 53.9 30 57.4 ;
        RECT 0 58.8 30 62.3 ;
        RECT 0 63.7 30 67.2 ;
        RECT 26 68.6 30 72.1 ;
        RECT 0 73.415 30 76.915 ;
        RECT 0 78.315 30 81.815 ;
        RECT 0 83.215 30 86.715 ;
        RECT 0 108.4 30 111.9 ;
        RECT 0 113.3 30 116.8 ;
        RECT 2.5 117.8 27.5 119.5 ;
        RECT 4.5 68.6 25.5 72.415 ;
        RECT 0 53.9 4 57.4 ;
        RECT 0 68.6 4 72.1 ;
    END
  END AVDDD
  PIN AVSSD
    DIRECTION INOUT ;
    USE GROUND ;
    PORT
      LAYER MET4 ;
        RECT 0 0 30 3.5 ;
        RECT 0 4.9 30 8.4 ;
        RECT 0 9.8 30 13.3 ;
        RECT 26 14.7 30 18.2 ;
        RECT 0 19.6 30 23.1 ;
        RECT 0 24.5 30 28 ;
        RECT 0 29.4 30 32.9 ;
        RECT 0 14.7 4 18.2 ;
    END
  END AVSSD
  PIN VSS
    DIRECTION INOUT ;
    USE GROUND ;
    PORT
      LAYER MET4 ;
        RECT 0 88.115 30 91.615 ;
        RECT 0 93.1 30 96.6 ;
        RECT 0 98 30 101.5 ;
        RECT 0 102.9 30 106.4 ;
    END
  END VSS
  OBS
    LAYER MET1 ;
      RECT 0 0 30 119.5 ;
    LAYER VIA1 ;
      RECT 0 0 30 119.5 ;
    LAYER MET2 ;
      RECT 0 0 30 119.5 ;
    LAYER VIA2 ;
      RECT 0 0 30 119.5 ;
    LAYER MET3 ;
      RECT 0 0 30 119.5 ;
    LAYER VIA3 ;
      RECT 0 0 30 119.5 ;
    LAYER MET4 ;
      RECT 0 0 30 119.5 ;
  END
END PVDDANA2

MACRO PVDDANA2C
  CLASS PAD ;
  ORIGIN 0 0 ;
  FOREIGN PVDDANA2C 0 0 ;
  SIZE 30 BY 119.5 ;
  SYMMETRY X Y R90 ;
  SITE IOSite ;
  PIN AVDDDC
    DIRECTION INOUT ;
    USE POWER ;
    PORT
      LAYER MET2 ;
        RECT 2.5 117.8 27.5 119.5 ;
      LAYER MET3 ;
        RECT 2.5 117.8 27.5 119.5 ;
      LAYER MET4 ;
        RECT 0 39.2 30 42.7 ;
        RECT 0 44.1 30 47.6 ;
        RECT 0 49 30 52.5 ;
        RECT 26 53.9 30 57.4 ;
        RECT 0 58.8 30 62.3 ;
        RECT 0 63.7 30 67.2 ;
        RECT 26 68.6 30 72.1 ;
        RECT 0 73.415 30 76.915 ;
        RECT 0 78.315 30 81.815 ;
        RECT 0 83.215 30 86.715 ;
        RECT 0 108.4 30 111.9 ;
        RECT 0 113.3 30 116.8 ;
        RECT 2.5 117.8 27.5 119.5 ;
        RECT 4.5 68.6 25.5 72.415 ;
        RECT 0 53.9 4 57.4 ;
        RECT 0 68.6 4 72.1 ;
    END
  END AVDDDC
  PIN AVSSDC
    DIRECTION INOUT ;
    USE GROUND ;
    PORT
      LAYER MET4 ;
        RECT 0 0 30 3.5 ;
        RECT 0 4.9 30 8.4 ;
        RECT 0 9.8 30 13.3 ;
        RECT 26 14.7 30 18.2 ;
        RECT 0 19.6 30 23.1 ;
        RECT 0 24.5 30 28 ;
        RECT 0 29.4 30 32.9 ;
        RECT 0 14.7 4 18.2 ;
    END
  END AVSSDC
  PIN VSS
    DIRECTION INOUT ;
    USE GROUND ;
    PORT
      LAYER MET4 ;
        RECT 0 88.115 30 91.615 ;
        RECT 0 93.1 30 96.6 ;
        RECT 0 98 30 101.5 ;
        RECT 0 102.9 30 106.4 ;
    END
  END VSS
  OBS
    LAYER MET1 ;
      RECT 0 0 30 119.5 ;
    LAYER VIA1 ;
      RECT 0 0 30 119.5 ;
    LAYER MET2 ;
      RECT 0 0 30 119.5 ;
    LAYER VIA2 ;
      RECT 0 0 30 119.5 ;
    LAYER MET3 ;
      RECT 0 0 30 119.5 ;
    LAYER VIA3 ;
      RECT 0 0 30 119.5 ;
    LAYER MET4 ;
      RECT 0 0 30 119.5 ;
  END
END PVDDANA2C

MACRO PVDDANA2I
  CLASS PAD ;
  ORIGIN 0 0 ;
  FOREIGN PVDDANA2I 0 0 ;
  SIZE 30 BY 119.5 ;
  SYMMETRY X Y R90 ;
  SITE IOSite ;
  PIN AVDDDI
    DIRECTION INOUT ;
    USE POWER ;
    PORT
      LAYER MET2 ;
        RECT 3.3 117.8 26.7 119.5 ;
      LAYER MET3 ;
        RECT 3.3 117.8 26.7 119.5 ;
        RECT 13.75 0 16.25 119.5 ;
      LAYER MET4 ;
        RECT 3.3 117.8 26.7 119.5 ;
        RECT 4.5 68.6 25.5 72.415 ;
    END
  END AVDDDI
  PIN POC
    DIRECTION INOUT ;
    USE GROUND ;
    PORT
      LAYER MET4 ;
        RECT 0 107.15 30 107.65 ;
    END
  END POC
  PIN VDD
    DIRECTION INOUT ;
    USE POWER ;
    PORT
      CLASS CORE ;
      LAYER MET4 ;
        RECT 0 113.3 30 116.8 ;
    END
    PORT
      LAYER MET4 ;
        RECT 0 108.4 30 111.9 ;
    END
  END VDD
  PIN VDDD
    DIRECTION INOUT ;
    USE POWER ;
    PORT
      LAYER MET4 ;
        RECT 0 39.2 30 42.7 ;
        RECT 0 44.1 30 47.6 ;
        RECT 0 49 30 52.5 ;
        RECT 26 53.9 30 57.4 ;
        RECT 0 58.8 30 62.3 ;
        RECT 0 63.7 30 67.2 ;
        RECT 26 68.6 30 72.1 ;
        RECT 26 73.415 30 76.915 ;
        RECT 0 78.315 30 81.815 ;
        RECT 0 83.215 30 86.715 ;
        RECT 0 53.9 4 57.4 ;
        RECT 0 68.6 4 72.1 ;
        RECT 0 73.415 4 76.915 ;
    END
  END VDDD
  PIN VSS
    DIRECTION INOUT ;
    USE GROUND ;
    PORT
      LAYER MET4 ;
        RECT 0 88.115 30 91.615 ;
        RECT 0 93.1 30 96.6 ;
        RECT 0 98 30 101.5 ;
        RECT 0 102.9 30 106.4 ;
    END
  END VSS
  PIN VSSD
    DIRECTION INOUT ;
    USE GROUND ;
    PORT
      LAYER MET4 ;
        RECT 0 0 30 3.5 ;
        RECT 0 4.9 30 8.4 ;
        RECT 0 9.8 30 13.3 ;
        RECT 26 14.7 30 18.2 ;
        RECT 0 19.6 30 23.1 ;
        RECT 0 24.5 30 28 ;
        RECT 0 29.4 30 32.9 ;
        RECT 0 14.7 4 18.2 ;
    END
  END VSSD
  OBS
    LAYER MET1 ;
      RECT 0 0 30 119.5 ;
    LAYER VIA1 ;
      RECT 0 0 30 119.5 ;
    LAYER MET2 ;
      RECT 0 0 30 119.5 ;
    LAYER VIA2 ;
      RECT 0 0 30 119.5 ;
    LAYER MET3 ;
      RECT 0 0 30 119.5 ;
    LAYER VIA3 ;
      RECT 0 0 30 119.5 ;
    LAYER MET4 ;
      RECT 0 0 30 119.5 ;
  END
END PVDDANA2I

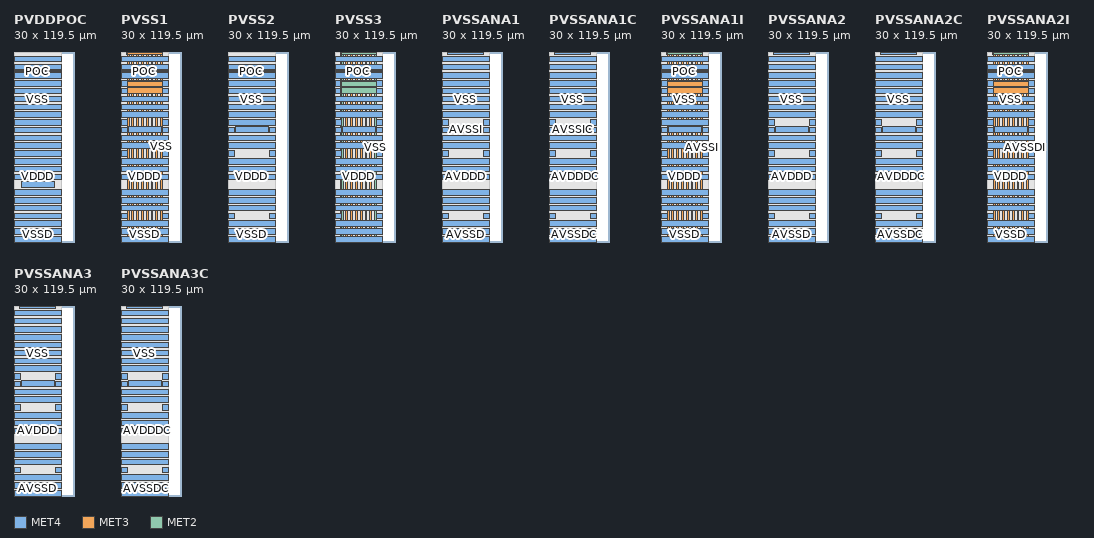
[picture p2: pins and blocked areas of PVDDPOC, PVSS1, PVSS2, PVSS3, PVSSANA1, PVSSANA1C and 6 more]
MACRO PVDDPOC
  CLASS PAD ;
  ORIGIN 0 0 ;
  FOREIGN PVDDPOC 0 0 ;
  SIZE 30 BY 119.5 ;
  SYMMETRY X Y R90 ;
  SITE IOSite ;
  PIN POC
    DIRECTION OUTPUT ;
    USE GROUND ;
    PORT
      LAYER MET4 ;
        RECT 0 107.15 30 107.65 ;
    END
  END POC
  PIN VDD
    DIRECTION INOUT ;
    USE POWER ;
    PORT
      CLASS CORE ;
      LAYER MET4 ;
        RECT 0 113.3 30 116.8 ;
    END
    PORT
      LAYER MET4 ;
        RECT 0 108.4 30 111.9 ;
    END
  END VDD
  PIN VDDD
    DIRECTION INOUT ;
    USE POWER ;
    PORT
      LAYER MET4 ;
        RECT 0 39.2 30 42.7 ;
        RECT 0 44.1 30 47.6 ;
        RECT 0 49 30 52.5 ;
        RECT 0 53.9 30 57.4 ;
        RECT 0 58.8 30 62.3 ;
        RECT 0 63.7 30 67.2 ;
        RECT 0 68.6 30 72.1 ;
        RECT 0 73.415 30 76.915 ;
        RECT 0 78.315 30 81.815 ;
        RECT 0 83.215 30 86.715 ;
    END
  END VDDD
  PIN VSS
    DIRECTION INOUT ;
    USE GROUND ;
    PORT
      LAYER MET4 ;
        RECT 0 88.115 30 91.615 ;
        RECT 0 93.1 30 96.6 ;
        RECT 0 98 30 101.5 ;
        RECT 0 102.9 30 106.4 ;
    END
  END VSS
  PIN VSSD
    DIRECTION INOUT ;
    USE GROUND ;
    PORT
      LAYER MET4 ;
        RECT 0 0 30 3.5 ;
        RECT 0 4.9 30 8.4 ;
        RECT 0 9.8 30 13.3 ;
        RECT 0 14.7 30 18.2 ;
        RECT 0 19.6 30 23.1 ;
        RECT 0 24.5 30 28 ;
        RECT 0 29.4 30 32.9 ;
        RECT 4.5 34.4 25.5 38.2 ;
    END
  END VSSD
  OBS
    LAYER MET1 ;
      RECT 0 0 30 119.5 ;
    LAYER VIA1 ;
      RECT 0 0 30 119.5 ;
    LAYER MET2 ;
      RECT 0 0 30 119.5 ;
    LAYER VIA2 ;
      RECT 0 0 30 119.5 ;
    LAYER MET3 ;
      RECT 0 0 30 119.5 ;
    LAYER VIA3 ;
      RECT 0 0 30 119.5 ;
    LAYER MET4 ;
      RECT 0 0 30 119.5 ;
  END
END PVDDPOC

MACRO PVSS1
  CLASS PAD ;
  ORIGIN 0 0 ;
  FOREIGN PVSS1 0 0 ;
  SIZE 30 BY 119.5 ;
  SYMMETRY X Y R90 ;
  SITE IOSite ;
  PIN VSS
    DIRECTION INOUT ;
    USE GROUND ;
    PORT
      LAYER MET2 ;
        RECT 3.9 117.8 26.1 119.5 ;
        RECT 24.9 0.001 26.1 119.5 ;
        RECT 3.9 98 26.1 101 ;
        RECT 3.9 93.1 26.1 97.1 ;
        RECT 21.9 0.001 23.1 119.5 ;
        RECT 18.9 0.001 20.1 119.5 ;
        RECT 15.9 0.001 17.1 119.5 ;
        RECT 12.9 0.001 14.1 119.5 ;
        RECT 9.9 0.001 11.1 119.5 ;
        RECT 6.9 0.001 8.1 119.5 ;
        RECT 3.9 0.001 5.1 119.5 ;
      LAYER MET3 ;
        RECT 3.9 117.8 26.1 119.5 ;
        RECT 24.9 0.001 26.1 119.5 ;
        RECT 3.9 98 26.1 101 ;
        RECT 3.9 93.1 26.1 97.1 ;
        RECT 21.9 0.001 23.1 119.5 ;
        RECT 18.9 0.001 20.1 119.5 ;
        RECT 15.9 0.001 17.1 119.5 ;
        RECT 12.9 0.001 14.1 119.5 ;
        RECT 9.9 0.001 11.1 119.5 ;
        RECT 6.9 0.001 8.1 119.5 ;
        RECT 3.9 0.001 5.1 119.5 ;
      LAYER MET4 ;
        RECT 0 88.115 30 91.615 ;
        RECT 0 93.1 30 96.6 ;
        RECT 0 98 30 101.5 ;
        RECT 0 102.9 30 106.4 ;
        RECT 3.76 117.8 26.24 119.5 ;
        RECT 4.5 68.6 25.5 72.415 ;
    END
  END VSS
  PIN POC
    DIRECTION INOUT ;
    USE GROUND ;
    PORT
      LAYER MET4 ;
        RECT 0 107.15 30 107.65 ;
    END
  END POC
  PIN VDD
    DIRECTION INOUT ;
    USE POWER ;
    PORT
      CLASS CORE ;
      LAYER MET4 ;
        RECT 0 113.3 30 116.8 ;
    END
    PORT
      LAYER MET4 ;
        RECT 0 108.4 30 111.9 ;
    END
  END VDD
  PIN VDDD
    DIRECTION INOUT ;
    USE POWER ;
    PORT
      LAYER MET4 ;
        RECT 0 39.2 30 42.7 ;
        RECT 0 44.1 30 47.6 ;
        RECT 0 49 30 52.5 ;
        RECT 26 53.9 30 57.4 ;
        RECT 0 58.8 30 62.3 ;
        RECT 0 63.7 30 67.2 ;
        RECT 26 68.6 30 72.1 ;
        RECT 26 73.415 30 76.915 ;
        RECT 0 78.315 30 81.815 ;
        RECT 0 83.215 30 86.715 ;
        RECT 0 53.9 4 57.4 ;
        RECT 0 68.6 4 72.1 ;
        RECT 0 73.415 4 76.915 ;
    END
  END VDDD
  PIN VSSD
    DIRECTION INOUT ;
    USE GROUND ;
    PORT
      LAYER MET4 ;
        RECT 0 0 30 3.5 ;
        RECT 0 4.9 30 8.4 ;
        RECT 0 9.8 30 13.3 ;
        RECT 26 14.7 30 18.2 ;
        RECT 0 19.6 30 23.1 ;
        RECT 0 24.5 30 28 ;
        RECT 0 29.4 30 32.9 ;
        RECT 0 14.7 4 18.2 ;
    END
  END VSSD
  OBS
    LAYER MET1 ;
      RECT 0 0 30 119.5 ;
    LAYER VIA1 ;
      RECT 0 0 30 119.5 ;
    LAYER MET2 ;
      RECT 0 0 30 119.5 ;
    LAYER VIA2 ;
      RECT 0 0 30 119.5 ;
    LAYER MET3 ;
      RECT 0 0 30 119.5 ;
    LAYER VIA3 ;
      RECT 0 0 30 119.5 ;
    LAYER MET4 ;
      RECT 0 0 30 119.5 ;
  END
END PVSS1

MACRO PVSS2
  CLASS PAD ;
  ORIGIN 0 0 ;
  FOREIGN PVSS2 0 0 ;
  SIZE 30 BY 119.5 ;
  SYMMETRY X Y R90 ;
  SITE IOSite ;
  PIN POC
    DIRECTION INOUT ;
    USE GROUND ;
    PORT
      LAYER MET4 ;
        RECT 0 107.15 30 107.65 ;
    END
  END POC
  PIN VDD
    DIRECTION INOUT ;
    USE POWER ;
    PORT
      CLASS CORE ;
      LAYER MET4 ;
        RECT 0 113.3 30 116.8 ;
    END
    PORT
      LAYER MET4 ;
        RECT 0 108.4 30 111.9 ;
    END
  END VDD
  PIN VDDD
    DIRECTION INOUT ;
    USE POWER ;
    PORT
      LAYER MET4 ;
        RECT 0 39.2 30 42.7 ;
        RECT 0 44.1 30 47.6 ;
        RECT 0 49 30 52.5 ;
        RECT 26 53.9 30 57.4 ;
        RECT 0 58.8 30 62.3 ;
        RECT 0 63.7 30 67.2 ;
        RECT 26 68.6 30 72.1 ;
        RECT 0 73.415 30 76.915 ;
        RECT 0 78.315 30 81.815 ;
        RECT 0 83.215 30 86.715 ;
        RECT 0 53.9 4 57.4 ;
        RECT 0 68.6 4 72.1 ;
    END
  END VDDD
  PIN VSS
    DIRECTION INOUT ;
    USE GROUND ;
    PORT
      LAYER MET4 ;
        RECT 0 88.115 30 91.615 ;
        RECT 0 93.1 30 96.6 ;
        RECT 0 98 30 101.5 ;
        RECT 0 102.9 30 106.4 ;
    END
  END VSS
  PIN VSSD
    DIRECTION INOUT ;
    USE GROUND ;
    PORT
      LAYER MET4 ;
        RECT 0 0 30 3.5 ;
        RECT 0 4.9 30 8.4 ;
        RECT 0 9.8 30 13.3 ;
        RECT 26 14.7 30 18.2 ;
        RECT 0 19.6 30 23.1 ;
        RECT 0 24.5 30 28 ;
        RECT 0 29.4 30 32.9 ;
        RECT 4.5 68.6 25.5 72.415 ;
        RECT 0 14.7 4 18.2 ;
    END
  END VSSD
  OBS
    LAYER MET1 ;
      RECT 0 0 30 119.5 ;
    LAYER VIA1 ;
      RECT 0 0 30 119.5 ;
    LAYER MET2 ;
      RECT 0 0 30 119.5 ;
    LAYER VIA2 ;
      RECT 0 0 30 119.5 ;
    LAYER MET3 ;
      RECT 0 0 30 119.5 ;
    LAYER VIA3 ;
      RECT 0 0 30 119.5 ;
    LAYER MET4 ;
      RECT 0 0 30 119.5 ;
  END
END PVSS2

MACRO PVSS3
  CLASS PAD ;
  ORIGIN 0 0 ;
  FOREIGN PVSS3 0 0 ;
  SIZE 30 BY 119.5 ;
  SYMMETRY X Y R90 ;
  SITE IOSite ;
  PIN VSS
    DIRECTION INOUT ;
    USE GROUND ;
    PORT
      LAYER MET2 ;
        RECT 3.9 117.8 26.1 119.5 ;
        RECT 24.9 0 26.1 119.5 ;
        RECT 3.9 98 26.1 101 ;
        RECT 3.9 93.1 26.1 97.1 ;
        RECT 21.9 0 23.1 119.5 ;
        RECT 18.9 0 20.1 119.5 ;
        RECT 15.9 0 17.1 119.5 ;
        RECT 12.9 0 14.1 119.5 ;
        RECT 9.9 0 11.1 119.5 ;
        RECT 6.9 0 8.1 119.5 ;
        RECT 3.9 0 5.1 119.5 ;
      LAYER MET3 ;
        RECT 3.76 117.8 26.24 119.5 ;
        RECT 24.9 0 26.24 119.5 ;
        RECT 3.76 98 26.24 101 ;
        RECT 3.76 93.1 26.24 97.1 ;
        RECT 21.9 0 23.1 119.5 ;
        RECT 18.9 0 20.1 119.5 ;
        RECT 15.9 0 17.1 119.5 ;
        RECT 12.9 0 14.1 119.5 ;
        RECT 9.9 0 11.1 119.5 ;
        RECT 6.9 0 8.1 119.5 ;
        RECT 3.76 0 5.1 119.5 ;
      LAYER MET4 ;
        RECT 0 0 30 3.5 ;
        RECT 0 4.9 30 8.4 ;
        RECT 0 9.8 30 13.3 ;
        RECT 26 14.7 30 18.2 ;
        RECT 0 19.6 30 23.1 ;
        RECT 0 24.5 30 28 ;
        RECT 0 29.4 30 32.9 ;
        RECT 0 88.115 30 91.615 ;
        RECT 0 93.1 30 96.6 ;
        RECT 0 98 30 101.5 ;
        RECT 0 102.9 30 106.4 ;
        RECT 3.76 117.8 26.24 119.5 ;
        RECT 4.5 68.6 25.5 72.415 ;
        RECT 0 14.7 4 18.2 ;
    END
  END VSS
  PIN POC
    DIRECTION INOUT ;
    USE GROUND ;
    PORT
      LAYER MET4 ;
        RECT 0 107.15 30 107.65 ;
    END
  END POC
  PIN VDD
    DIRECTION INOUT ;
    USE POWER ;
    PORT
      CLASS CORE ;
      LAYER MET4 ;
        RECT 0 113.3 30 116.8 ;
    END
    PORT
      LAYER MET4 ;
        RECT 0 108.4 30 111.9 ;
    END
  END VDD
  PIN VDDD
    DIRECTION INOUT ;
    USE POWER ;
    PORT
      LAYER MET4 ;
        RECT 0 39.2 30 42.7 ;
        RECT 0 44.1 30 47.6 ;
        RECT 0 49 30 52.5 ;
        RECT 26 53.9 30 57.4 ;
        RECT 0 58.8 30 62.3 ;
        RECT 0 63.7 30 67.2 ;
        RECT 26 68.6 30 72.1 ;
        RECT 26 73.415 30 76.915 ;
        RECT 0 78.315 30 81.815 ;
        RECT 0 83.215 30 86.715 ;
        RECT 0 53.9 4 57.4 ;
        RECT 0 68.6 4 72.1 ;
        RECT 0 73.415 4 76.915 ;
    END
  END VDDD
  OBS
    LAYER MET1 ;
      RECT 0 0 30 119.5 ;
    LAYER VIA1 ;
      RECT 0 0 30 119.5 ;
    LAYER MET2 ;
      RECT 0 0 30 119.5 ;
    LAYER VIA2 ;
      RECT 0 0 30 119.5 ;
    LAYER MET3 ;
      RECT 0 0 30 119.5 ;
    LAYER VIA3 ;
      RECT 0 0 30 119.5 ;
    LAYER MET4 ;
      RECT 0 0 30 119.5 ;
  END
END PVSS3

MACRO PVSSANA1
  CLASS PAD ;
  ORIGIN 0 0 ;
  FOREIGN PVSSANA1 0 0 ;
  SIZE 30 BY 119.5 ;
  SYMMETRY X Y R90 ;
  SITE IOSite ;
  PIN AVSSI
    DIRECTION INOUT ;
    USE GROUND ;
    PORT
      LAYER MET2 ;
        RECT 3.76 117.8 26.24 119.5 ;
      LAYER MET3 ;
        RECT 3.76 117.8 26.24 119.5 ;
      LAYER MET4 ;
        RECT 3.76 117.8 26.24 119.5 ;
        RECT 4.5 68.6 25.5 72.415 ;
    END
  END AVSSI
  PIN AVDDD
    DIRECTION INOUT ;
    USE POWER ;
    PORT
      LAYER MET4 ;
        RECT 0 39.2 30 42.7 ;
        RECT 0 44.1 30 47.6 ;
        RECT 0 49 30 52.5 ;
        RECT 26 53.9 30 57.4 ;
        RECT 0 58.8 30 62.3 ;
        RECT 0 63.7 30 67.2 ;
        RECT 26 68.6 30 72.1 ;
        RECT 26 73.415 30 76.915 ;
        RECT 0 78.315 30 81.815 ;
        RECT 0 83.215 30 86.715 ;
        RECT 0 108.4 30 111.9 ;
        RECT 0 113.3 30 116.8 ;
        RECT 0 53.9 4 57.4 ;
        RECT 0 68.6 4 72.1 ;
        RECT 0 73.415 4 76.915 ;
    END
  END AVDDD
  PIN AVSSD
    DIRECTION INOUT ;
    USE GROUND ;
    PORT
      LAYER MET4 ;
        RECT 0 0 30 3.5 ;
        RECT 0 4.9 30 8.4 ;
        RECT 0 9.8 30 13.3 ;
        RECT 26 14.7 30 18.2 ;
        RECT 0 19.6 30 23.1 ;
        RECT 0 24.5 30 28 ;
        RECT 0 29.4 30 32.9 ;
        RECT 0 14.7 4 18.2 ;
    END
  END AVSSD
  PIN VSS
    DIRECTION INOUT ;
    USE GROUND ;
    PORT
      LAYER MET4 ;
        RECT 0 88.115 30 91.615 ;
        RECT 0 93.1 30 96.6 ;
        RECT 0 98 30 101.5 ;
        RECT 0 102.9 30 106.4 ;
    END
  END VSS
  OBS
    LAYER MET1 ;
      RECT 0 0 30 119.5 ;
    LAYER VIA1 ;
      RECT 0 0 30 119.5 ;
    LAYER MET2 ;
      RECT 0 0 30 119.5 ;
    LAYER VIA2 ;
      RECT 0 0 30 119.5 ;
    LAYER MET3 ;
      RECT 0 0 30 119.5 ;
    LAYER VIA3 ;
      RECT 0 0 30 119.5 ;
    LAYER MET4 ;
      RECT 0 0 30 119.5 ;
  END
END PVSSANA1

MACRO PVSSANA1C
  CLASS PAD ;
  ORIGIN 0 0 ;
  FOREIGN PVSSANA1C 0 0 ;
  SIZE 30 BY 119.5 ;
  SYMMETRY X Y R90 ;
  SITE IOSite ;
  PIN AVSSIC
    DIRECTION INOUT ;
    USE GROUND ;
    PORT
      LAYER MET2 ;
        RECT 3.76 117.8 26.24 119.5 ;
      LAYER MET3 ;
        RECT 3.76 117.8 26.24 119.5 ;
      LAYER MET4 ;
        RECT 3.76 117.8 26.24 119.5 ;
        RECT 4.5 68.6 25.5 72.415 ;
    END
  END AVSSIC
  PIN AVDDDC
    DIRECTION INOUT ;
    USE POWER ;
    PORT
      LAYER MET4 ;
        RECT 0 39.2 30 42.7 ;
        RECT 0 44.1 30 47.6 ;
        RECT 0 49 30 52.5 ;
        RECT 26 53.9 30 57.4 ;
        RECT 0 58.8 30 62.3 ;
        RECT 0 63.7 30 67.2 ;
        RECT 26 68.6 30 72.1 ;
        RECT 26 73.415 30 76.915 ;
        RECT 0 78.315 30 81.815 ;
        RECT 0 83.215 30 86.715 ;
        RECT 0 108.4 30 111.9 ;
        RECT 0 113.3 30 116.8 ;
        RECT 0 53.9 4 57.4 ;
        RECT 0 68.6 4 72.1 ;
        RECT 0 73.415 4 76.915 ;
    END
  END AVDDDC
  PIN AVSSDC
    DIRECTION INOUT ;
    USE GROUND ;
    PORT
      LAYER MET4 ;
        RECT 0 0 30 3.5 ;
        RECT 0 4.9 30 8.4 ;
        RECT 0 9.8 30 13.3 ;
        RECT 26 14.7 30 18.2 ;
        RECT 0 19.6 30 23.1 ;
        RECT 0 24.5 30 28 ;
        RECT 0 29.4 30 32.9 ;
        RECT 0 14.7 4 18.2 ;
    END
  END AVSSDC
  PIN VSS
    DIRECTION INOUT ;
    USE GROUND ;
    PORT
      LAYER MET4 ;
        RECT 0 88.115 30 91.615 ;
        RECT 0 93.1 30 96.6 ;
        RECT 0 98 30 101.5 ;
        RECT 0 102.9 30 106.4 ;
    END
  END VSS
  OBS
    LAYER MET1 ;
      RECT 0 0 30 119.5 ;
    LAYER VIA1 ;
      RECT 0 0 30 119.5 ;
    LAYER MET2 ;
      RECT 0 0 30 119.5 ;
    LAYER VIA2 ;
      RECT 0 0 30 119.5 ;
    LAYER MET3 ;
      RECT 0 0 30 119.5 ;
    LAYER VIA3 ;
      RECT 0 0 30 119.5 ;
    LAYER MET4 ;
      RECT 0 0 30 119.5 ;
  END
END PVSSANA1C

MACRO PVSSANA1I
  CLASS PAD ;
  ORIGIN 0 0 ;
  FOREIGN PVSSANA1I 0 0 ;
  SIZE 30 BY 119.5 ;
  SYMMETRY X Y R90 ;
  SITE IOSite ;
  PIN AVSSI
    DIRECTION INOUT ;
    USE GROUND ;
    PORT
      LAYER MET2 ;
        RECT 3.9 117.8 26.1 119.5 ;
        RECT 24.9 0 26.1 119.5 ;
        RECT 3.9 98 26.1 101 ;
        RECT 3.9 93.1 26.1 97.1 ;
        RECT 21.9 0 23.1 119.5 ;
        RECT 18.9 0 20.1 119.5 ;
        RECT 15.9 0 17.1 119.5 ;
        RECT 12.9 0 14.1 119.5 ;
        RECT 9.9 0 11.1 119.5 ;
        RECT 6.9 0 8.1 119.5 ;
        RECT 3.9 0 5.1 119.5 ;
      LAYER MET3 ;
        RECT 3.76 117.8 26.24 119.5 ;
        RECT 24.9 0 26.1 119.5 ;
        RECT 3.9 98 26.1 101 ;
        RECT 3.9 93.1 26.1 97.1 ;
        RECT 21.9 0 23.1 119.5 ;
        RECT 18.9 0 20.1 119.5 ;
        RECT 15.9 0 17.1 119.5 ;
        RECT 12.9 0 14.1 119.5 ;
        RECT 9.9 0 11.1 119.5 ;
        RECT 6.9 0 8.1 119.5 ;
        RECT 3.9 0 5.1 119.5 ;
      LAYER MET4 ;
        RECT 3.76 117.8 26.24 119.5 ;
        RECT 4.5 68.6 25.5 72.415 ;
    END
  END AVSSI
  PIN POC
    DIRECTION INOUT ;
    USE GROUND ;
    PORT
      LAYER MET4 ;
        RECT 0 107.15 30 107.65 ;
    END
  END POC
  PIN VDD
    DIRECTION INOUT ;
    USE POWER ;
    PORT
      CLASS CORE ;
      LAYER MET4 ;
        RECT 0 113.3 30 116.8 ;
    END
    PORT
      LAYER MET4 ;
        RECT 0 108.4 30 111.9 ;
    END
  END VDD
  PIN VDDD
    DIRECTION INOUT ;
    USE POWER ;
    PORT
      LAYER MET4 ;
        RECT 0 39.2 30 42.7 ;
        RECT 0 44.1 30 47.6 ;
        RECT 0 49 30 52.5 ;
        RECT 26 53.9 30 57.4 ;
        RECT 0 58.8 30 62.3 ;
        RECT 0 63.7 30 67.2 ;
        RECT 26 68.6 30 72.1 ;
        RECT 0 73.415 30 76.915 ;
        RECT 0 78.315 30 81.815 ;
        RECT 0 83.215 30 86.715 ;
        RECT 0 53.9 4 57.4 ;
        RECT 0 68.6 4 72.101 ;
    END
  END VDDD
  PIN VSS
    DIRECTION INOUT ;
    USE GROUND ;
    PORT
      LAYER MET4 ;
        RECT 0 88.115 30 91.615 ;
        RECT 0 93.1 30 96.6 ;
        RECT 0 98 30 101.5 ;
        RECT 0 102.9 30 106.4 ;
    END
  END VSS
  PIN VSSD
    DIRECTION INOUT ;
    USE GROUND ;
    PORT
      LAYER MET4 ;
        RECT 0 0 30 3.5 ;
        RECT 0 4.9 30 8.4 ;
        RECT 0 9.8 30 13.3 ;
        RECT 26 14.7 30 18.2 ;
        RECT 0 19.6 30 23.1 ;
        RECT 0 24.5 30 28 ;
        RECT 0 29.4 30 32.9 ;
        RECT 0 14.7 4 18.2 ;
    END
  END VSSD
  OBS
    LAYER MET1 ;
      RECT 0 0 30 119.5 ;
    LAYER VIA1 ;
      RECT 0 0 30 119.5 ;
    LAYER MET2 ;
      RECT 0 0 30 119.5 ;
    LAYER VIA2 ;
      RECT 0 0 30 119.5 ;
    LAYER MET3 ;
      RECT 0 0 30 119.5 ;
    LAYER VIA3 ;
      RECT 0 0 30 119.5 ;
    LAYER MET4 ;
      RECT 0 0 30 119.5 ;
  END
END PVSSANA1I

MACRO PVSSANA2
  CLASS PAD ;
  ORIGIN 0 0 ;
  FOREIGN PVSSANA2 0 0 ;
  SIZE 30 BY 119.5 ;
  SYMMETRY X Y R90 ;
  SITE IOSite ;
  PIN AVSSD
    DIRECTION INOUT ;
    USE GROUND ;
    PORT
      LAYER MET2 ;
        RECT 3.76 117.8 26.24 119.5 ;
      LAYER MET3 ;
        RECT 3.76 117.8 26.24 119.5 ;
      LAYER MET4 ;
        RECT 0 0 30 3.5 ;
        RECT 0 4.9 30 8.4 ;
        RECT 0 9.8 30 13.3 ;
        RECT 26 14.7 30 18.2 ;
        RECT 0 19.6 30 23.1 ;
        RECT 0 24.5 30 28 ;
        RECT 0 29.4 30 32.9 ;
        RECT 3.76 117.8 26.24 119.5 ;
        RECT 4.5 68.6 25.5 72.415 ;
        RECT 0 14.7 4 18.2 ;
    END
  END AVSSD
  PIN AVDDD
    DIRECTION INOUT ;
    USE POWER ;
    PORT
      LAYER MET4 ;
        RECT 0 39.2 30 42.7 ;
        RECT 0 44.1 30 47.6 ;
        RECT 0 49 30 52.5 ;
        RECT 26 53.9 30 57.4 ;
        RECT 0 58.8 30 62.3 ;
        RECT 0 63.7 30 67.2 ;
        RECT 26 68.6 30 72.1 ;
        RECT 26 73.415 30 76.915 ;
        RECT 0 78.315 30 81.815 ;
        RECT 0 83.215 30 86.715 ;
        RECT 0 108.4 30 111.9 ;
        RECT 0 113.3 30 116.8 ;
        RECT 0 53.9 4 57.4 ;
        RECT 0 68.6 4 72.1 ;
        RECT 0 73.415 4 76.915 ;
    END
  END AVDDD
  PIN VSS
    DIRECTION INOUT ;
    USE GROUND ;
    PORT
      LAYER MET4 ;
        RECT 0 88.115 30 91.615 ;
        RECT 0 93.1 30 96.6 ;
        RECT 0 98 30 101.5 ;
        RECT 0 102.9 30 106.4 ;
    END
  END VSS
  OBS
    LAYER MET1 ;
      RECT 0 0 30 119.5 ;
    LAYER VIA1 ;
      RECT 0 0 30 119.5 ;
    LAYER MET2 ;
      RECT 0 0 30 119.5 ;
    LAYER VIA2 ;
      RECT 0 0 30 119.5 ;
    LAYER MET3 ;
      RECT 0 0 30 119.5 ;
    LAYER VIA3 ;
      RECT 0 0 30 119.5 ;
    LAYER MET4 ;
      RECT 0 0 30 119.5 ;
  END
END PVSSANA2

MACRO PVSSANA2C
  CLASS PAD ;
  ORIGIN 0 0 ;
  FOREIGN PVSSANA2C 0 0 ;
  SIZE 30 BY 119.5 ;
  SYMMETRY X Y R90 ;
  SITE IOSite ;
  PIN AVSSDC
    DIRECTION INOUT ;
    USE GROUND ;
    PORT
      LAYER MET2 ;
        RECT 3.76 117.8 26.24 119.5 ;
      LAYER MET3 ;
        RECT 3.76 117.8 26.24 119.5 ;
      LAYER MET4 ;
        RECT 0 0 30 3.5 ;
        RECT 0 4.9 30 8.4 ;
        RECT 0 9.8 30 13.3 ;
        RECT 26 14.7 30 18.2 ;
        RECT 0 19.6 30 23.1 ;
        RECT 0 24.5 30 28 ;
        RECT 0 29.4 30 32.9 ;
        RECT 3.76 117.8 26.24 119.5 ;
        RECT 4.5 68.6 25.5 72.415 ;
        RECT 0 14.7 4 18.2 ;
    END
  END AVSSDC
  PIN AVDDDC
    DIRECTION INOUT ;
    USE POWER ;
    PORT
      LAYER MET4 ;
        RECT 0 39.2 30 42.7 ;
        RECT 0 44.1 30 47.6 ;
        RECT 0 49 30 52.5 ;
        RECT 26 53.9 30 57.4 ;
        RECT 0 58.8 30 62.3 ;
        RECT 0 63.7 30 67.2 ;
        RECT 26 68.6 30 72.1 ;
        RECT 26 73.415 30 76.915 ;
        RECT 0 78.315 30 81.815 ;
        RECT 0 83.215 30 86.715 ;
        RECT 0 108.4 30 111.9 ;
        RECT 0 113.3 30 116.8 ;
        RECT 0 53.9 4 57.4 ;
        RECT 0 68.6 4 72.1 ;
        RECT 0 73.415 4 76.915 ;
    END
  END AVDDDC
  PIN VSS
    DIRECTION INOUT ;
    USE GROUND ;
    PORT
      LAYER MET4 ;
        RECT 0 88.115 30 91.615 ;
        RECT 0 93.1 30 96.6 ;
        RECT 0 98 30 101.5 ;
        RECT 0 102.9 30 106.4 ;
    END
  END VSS
  OBS
    LAYER MET1 ;
      RECT 0 0 30 119.5 ;
    LAYER VIA1 ;
      RECT 0 0 30 119.5 ;
    LAYER MET2 ;
      RECT 0 0 30 119.5 ;
    LAYER VIA2 ;
      RECT 0 0 30 119.5 ;
    LAYER MET3 ;
      RECT 0 0 30 119.5 ;
    LAYER VIA3 ;
      RECT 0 0 30 119.5 ;
    LAYER MET4 ;
      RECT 0 0 30 119.5 ;
  END
END PVSSANA2C

MACRO PVSSANA2I
  CLASS PAD ;
  ORIGIN 0 0 ;
  FOREIGN PVSSANA2I 0 0 ;
  SIZE 30 BY 119.5 ;
  SYMMETRY X Y R90 ;
  SITE IOSite ;
  PIN AVSSDI
    DIRECTION INOUT ;
    USE GROUND ;
    PORT
      LAYER MET2 ;
        RECT 3.9 117.8 26.1 119.5 ;
        RECT 24.9 0 26.1 119.5 ;
        RECT 3.9 98 26.1 101 ;
        RECT 3.9 93.1 26.1 97.1 ;
        RECT 21.9 0 23.1 119.5 ;
        RECT 18.9 0 20.1 119.5 ;
        RECT 15.9 0 17.1 119.5 ;
        RECT 12.9 0 14.1 119.5 ;
        RECT 9.9 0 11.1 119.5 ;
        RECT 6.9 0 8.1 119.5 ;
        RECT 3.9 0 5.1 119.5 ;
      LAYER MET3 ;
        RECT 3.76 117.8 26.24 119.5 ;
        RECT 24.9 0 26.1 119.5 ;
        RECT 3.9 98 26.1 101 ;
        RECT 3.9 93.1 26.1 97.1 ;
        RECT 21.9 0 23.1 119.5 ;
        RECT 18.9 0 20.1 119.5 ;
        RECT 15.9 0 17.1 119.5 ;
        RECT 12.9 0 14.1 119.5 ;
        RECT 9.9 0 11.1 119.5 ;
        RECT 6.9 0 8.1 119.5 ;
        RECT 3.9 0 5.1 119.5 ;
      LAYER MET4 ;
        RECT 3.76 117.8 26.24 119.5 ;
        RECT 4.5 68.6 25.5 72.415 ;
    END
  END AVSSDI
  PIN POC
    DIRECTION INOUT ;
    USE GROUND ;
    PORT
      LAYER MET4 ;
        RECT 0 107.15 30 107.65 ;
    END
  END POC
  PIN VDD
    DIRECTION INOUT ;
    USE POWER ;
    PORT
      CLASS CORE ;
      LAYER MET4 ;
        RECT 0 113.3 30 116.8 ;
    END
    PORT
      LAYER MET4 ;
        RECT 0 108.4 30 111.9 ;
    END
  END VDD
  PIN VDDD
    DIRECTION INOUT ;
    USE POWER ;
    PORT
      LAYER MET4 ;
        RECT 0 39.2 30 42.7 ;
        RECT 0 44.1 30 47.6 ;
        RECT 0 49 30 52.5 ;
        RECT 26 53.9 30 57.4 ;
        RECT 0 58.8 30 62.3 ;
        RECT 0 63.7 30 67.2 ;
        RECT 26 68.6 30 72.1 ;
        RECT 26 73.415 30 76.915 ;
        RECT 0 78.315 30 81.815 ;
        RECT 0 83.215 30 86.715 ;
        RECT 0 53.9 4 57.4 ;
        RECT 0 68.6 4 72.1 ;
        RECT 0 73.415 4 76.915 ;
    END
  END VDDD
  PIN VSS
    DIRECTION INOUT ;
    USE GROUND ;
    PORT
      LAYER MET4 ;
        RECT 0 88.115 30 91.615 ;
        RECT 0 93.1 30 96.6 ;
        RECT 0 98 30 101.5 ;
        RECT 0 102.9 30 106.4 ;
    END
  END VSS
  PIN VSSD
    DIRECTION INOUT ;
    USE GROUND ;
    PORT
      LAYER MET4 ;
        RECT 0 0 30 3.5 ;
        RECT 0 4.9 30 8.4 ;
        RECT 0 9.8 30 13.3 ;
        RECT 26 14.7 30 18.2 ;
        RECT 0 19.6 30 23.1 ;
        RECT 0 24.5 30 28 ;
        RECT 0 29.4 30 32.9 ;
        RECT 0 14.7 4 18.2 ;
    END
  END VSSD
  OBS
    LAYER MET1 ;
      RECT 0 0 30 119.5 ;
    LAYER VIA1 ;
      RECT 0 0 30 119.5 ;
    LAYER MET2 ;
      RECT 0 0 30 119.5 ;
    LAYER VIA2 ;
      RECT 0 0 30 119.5 ;
    LAYER MET3 ;
      RECT 0 0 30 119.5 ;
    LAYER VIA3 ;
      RECT 0 0 30 119.5 ;
    LAYER MET4 ;
      RECT 0 0 30 119.5 ;
  END
END PVSSANA2I

MACRO PVSSANA3
  CLASS PAD ;
  ORIGIN 0 0 ;
  FOREIGN PVSSANA3 0 0 ;
  SIZE 30 BY 119.5 ;
  SYMMETRY X Y R90 ;
  SITE IOSite ;
  PIN VSS
    DIRECTION INOUT ;
    USE GROUND ;
    PORT
      LAYER MET2 ;
        RECT 3.76 117.8 26.24 119.5 ;
      LAYER MET3 ;
        RECT 3.76 117.8 26.24 119.5 ;
      LAYER MET4 ;
        RECT 0 88.115 30 91.615 ;
        RECT 0 93.1 30 96.6 ;
        RECT 0 98 30 101.5 ;
        RECT 0 102.9 30 106.4 ;
        RECT 3.76 117.8 26.24 119.5 ;
        RECT 4.5 68.6 25.5 72.415 ;
    END
  END VSS
  PIN AVDDD
    DIRECTION INOUT ;
    USE POWER ;
    PORT
      LAYER MET4 ;
        RECT 0 39.2 30 42.7 ;
        RECT 0 44.1 30 47.6 ;
        RECT 0 49 30 52.5 ;
        RECT 26 53.9 30 57.4 ;
        RECT 0 58.8 30 62.3 ;
        RECT 0 63.7 30 67.2 ;
        RECT 26 68.6 30 72.1 ;
        RECT 26 73.415 30 76.915 ;
        RECT 0 78.315 30 81.815 ;
        RECT 0 83.215 30 86.715 ;
        RECT 0 108.4 30 111.9 ;
        RECT 0 113.3 30 116.8 ;
        RECT 0 53.9 4 57.4 ;
        RECT 0 68.6 4 72.1 ;
        RECT 0 73.415 4 76.915 ;
    END
  END AVDDD
  PIN AVSSD
    DIRECTION INOUT ;
    USE GROUND ;
    PORT
      LAYER MET4 ;
        RECT 0 0 30 3.5 ;
        RECT 0 4.9 30 8.4 ;
        RECT 0 9.8 30 13.3 ;
        RECT 26 14.7 30 18.2 ;
        RECT 0 19.6 30 23.1 ;
        RECT 0 24.5 30 28 ;
        RECT 0 29.4 30 32.9 ;
        RECT 0 14.7 4 18.2 ;
    END
  END AVSSD
  OBS
    LAYER MET1 ;
      RECT 0 0 30 119.5 ;
    LAYER VIA1 ;
      RECT 0 0 30 119.5 ;
    LAYER MET2 ;
      RECT 0 0 30 119.5 ;
    LAYER VIA2 ;
      RECT 0 0 30 119.5 ;
    LAYER MET3 ;
      RECT 0 0 30 119.5 ;
    LAYER VIA3 ;
      RECT 0 0 30 119.5 ;
    LAYER MET4 ;
      RECT 0 0 30 119.5 ;
  END
END PVSSANA3

MACRO PVSSANA3C
  CLASS PAD ;
  ORIGIN 0 0 ;
  FOREIGN PVSSANA3C 0 0 ;
  SIZE 30 BY 119.5 ;
  SYMMETRY X Y R90 ;
  SITE IOSite ;
  PIN VSS
    DIRECTION INOUT ;
    USE GROUND ;
    PORT
      LAYER MET2 ;
        RECT 3.76 117.8 26.24 119.5 ;
      LAYER MET3 ;
        RECT 3.76 117.8 26.24 119.5 ;
      LAYER MET4 ;
        RECT 0 88.115 30 91.615 ;
        RECT 0 93.1 30 96.6 ;
        RECT 0 98 30 101.5 ;
        RECT 0 102.9 30 106.4 ;
        RECT 3.76 117.8 26.24 119.5 ;
        RECT 4.5 68.6 25.5 72.415 ;
    END
  END VSS
  PIN AVDDDC
    DIRECTION INOUT ;
    USE POWER ;
    PORT
      LAYER MET4 ;
        RECT 0 39.2 30 42.7 ;
        RECT 0 44.1 30 47.6 ;
        RECT 0 49 30 52.5 ;
        RECT 26 53.9 30 57.4 ;
        RECT 0 58.8 30 62.3 ;
        RECT 0 63.7 30 67.2 ;
        RECT 26 68.6 30 72.1 ;
        RECT 26 73.415 30 76.915 ;
        RECT 0 78.315 30 81.815 ;
        RECT 0 83.215 30 86.715 ;
        RECT 0 108.4 30 111.9 ;
        RECT 0 113.3 30 116.8 ;
        RECT 0 53.9 4 57.4 ;
        RECT 0 68.6 4 72.1 ;
        RECT 0 73.415 4 76.915 ;
    END
  END AVDDDC
  PIN AVSSDC
    DIRECTION INOUT ;
    USE GROUND ;
    PORT
      LAYER MET4 ;
        RECT 0 0 30 3.5 ;
        RECT 0 4.9 30 8.4 ;
        RECT 0 9.8 30 13.3 ;
        RECT 26 14.7 30 18.2 ;
        RECT 0 19.6 30 23.1 ;
        RECT 0 24.5 30 28 ;
        RECT 0 29.4 30 32.9 ;
        RECT 0 14.7 4 18.2 ;
    END
  END AVSSDC
  OBS
    LAYER MET1 ;
      RECT 0 0 30 119.5 ;
    LAYER VIA1 ;
      RECT 0 0 30 119.5 ;
    LAYER MET2 ;
      RECT 0 0 30 119.5 ;
    LAYER VIA2 ;
      RECT 0 0 30 119.5 ;
    LAYER MET3 ;
      RECT 0 0 30 119.5 ;
    LAYER VIA3 ;
      RECT 0 0 30 119.5 ;
    LAYER MET4 ;
      RECT 0 0 30 119.5 ;
  END
END PVSSANA3C

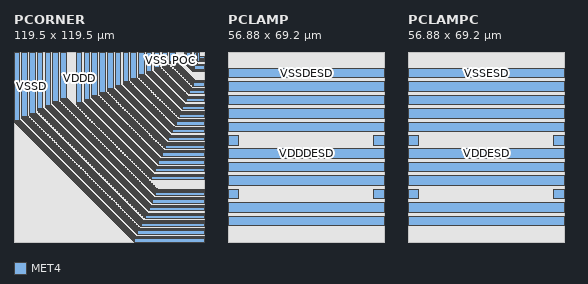
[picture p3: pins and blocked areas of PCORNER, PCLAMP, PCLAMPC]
MACRO PCORNER
  CLASS ENDCAP BOTTOMLEFT ;
  ORIGIN 0 0 ;
  FOREIGN PCORNER 0 0 ;
  SIZE 119.5 BY 119.5 ;
  SYMMETRY X Y R90 ;
  SITE CornerSite ;
  PIN POC
    DIRECTION INOUT ;
    USE GROUND ;
    PORT
      LAYER MET4 ;
        RECT 112.611 107.15 119.5 107.65 ;
        RECT 112.15 107.486 112.819 107.754 ;
        RECT 112.4 107.255 112.611 107.964 ;
        RECT 111.9 107.736 112.4 108.194 ;
        RECT 111.65 107.986 112.15 108.444 ;
        RECT 111.4 108.236 111.9 108.694 ;
        RECT 111.15 108.486 111.65 108.944 ;
        RECT 110.9 108.736 111.4 109.194 ;
        RECT 110.65 108.986 111.15 109.444 ;
        RECT 110.4 109.236 110.9 109.694 ;
        RECT 110.15 109.486 110.65 109.944 ;
        RECT 109.9 109.736 110.4 110.194 ;
        RECT 109.65 109.986 110.15 110.444 ;
        RECT 109.4 110.236 109.9 110.694 ;
        RECT 109.15 110.486 109.65 110.944 ;
        RECT 108.9 110.736 109.4 111.194 ;
        RECT 108.65 110.986 109.15 111.444 ;
        RECT 108.4 111.236 108.9 111.694 ;
        RECT 108.15 111.486 108.65 111.944 ;
        RECT 107.9 111.736 108.4 112.194 ;
        RECT 107.65 111.986 108.15 112.444 ;
        RECT 107.191 112.445 107.9 112.694 ;
        RECT 107.441 112.215 107.9 112.694 ;
        RECT 107.15 112.57 107.65 119.5 ;
    END
  END POC
  PIN VDD
    DIRECTION INOUT ;
    USE POWER ;
    PORT
      LAYER MET4 ;
        RECT 113.491 108.4 119.5 111.9 ;
        RECT 109.9 111.866 115.647 111.978 ;
        RECT 108.4 113.366 113.991 113.681 ;
        RECT 108.4 113.366 113.741 113.931 ;
        RECT 108.65 113.116 114.241 113.431 ;
        RECT 113.4 108.445 113.491 114.102 ;
        RECT 108.9 112.866 114.491 113.181 ;
        RECT 113.15 108.616 113.4 114.272 ;
        RECT 109.15 112.616 114.741 112.931 ;
        RECT 112.9 108.866 113.15 114.522 ;
        RECT 109.4 112.366 114.991 112.681 ;
        RECT 112.65 109.116 112.9 114.772 ;
        RECT 109.65 112.116 115.241 112.431 ;
        RECT 112.4 109.366 112.65 115.022 ;
        RECT 109.9 111.866 115.491 112.181 ;
        RECT 112.15 109.616 112.4 115.272 ;
        RECT 110.15 111.616 119.5 111.9 ;
        RECT 111.9 109.866 112.15 115.522 ;
        RECT 108.4 113.366 111.9 119.5 ;
        RECT 110.4 111.366 119.5 111.9 ;
        RECT 111.65 110.116 111.9 119.5 ;
        RECT 110.65 111.116 119.5 111.9 ;
        RECT 111.4 110.366 111.9 119.5 ;
        RECT 110.9 110.866 119.5 111.9 ;
        RECT 111.15 110.616 111.9 119.5 ;
        RECT 115.667 113.3 119.5 116.8 ;
        RECT 113.3 115.542 116.8 119.5 ;
        RECT 113.55 115.292 119.5 116.8 ;
        RECT 115.55 113.358 116.8 119.5 ;
        RECT 113.8 115.042 119.5 116.8 ;
        RECT 115.3 113.542 116.8 119.5 ;
        RECT 114.05 114.792 119.5 116.8 ;
        RECT 115.05 113.792 116.8 119.5 ;
        RECT 114.3 114.542 119.5 116.8 ;
        RECT 114.8 114.042 116.8 119.5 ;
        RECT 114.55 114.292 119.5 116.8 ;
    END
  END VDD
  PIN VDDD
    DIRECTION INOUT ;
    USE POWER ;
    PORT
      LAYER MET4 ;
        RECT 64.95 96.084 69.45 96.49 ;
        RECT 64.7 96.334 69.2 96.74 ;
        RECT 64.45 96.584 68.95 96.99 ;
        RECT 64.2 96.834 68.7 97.24 ;
        RECT 63.95 97.084 68.45 97.49 ;
        RECT 63.7 97.334 68.2 97.74 ;
        RECT 63.7 97.334 67.95 97.99 ;
        RECT 63.7 97.334 67.7 98.24 ;
        RECT 63.7 97.334 67.45 98.49 ;
        RECT 63.7 97.334 67.2 119.5 ;
        RECT 99.639 68.6 119.5 72.1 ;
        RECT 96.1 72.014 100.795 72.178 ;
        RECT 95.1 73.014 99.639 73.276 ;
        RECT 95.35 72.764 99.889 73.131 ;
        RECT 99.6 68.619 99.639 73.276 ;
        RECT 95.6 72.514 100.139 72.881 ;
        RECT 99.35 68.764 99.6 73.42 ;
        RECT 94.85 73.264 99.35 73.67 ;
        RECT 95.85 72.264 100.389 72.631 ;
        RECT 99.1 69.014 99.35 73.67 ;
        RECT 94.6 73.514 99.1 73.92 ;
        RECT 96.1 72.014 100.639 72.381 ;
        RECT 98.85 69.264 99.1 73.92 ;
        RECT 94.35 73.764 98.85 74.17 ;
        RECT 96.35 71.764 119.5 72.1 ;
        RECT 98.6 69.514 98.85 74.17 ;
        RECT 94.1 74.014 98.6 74.42 ;
        RECT 96.6 71.514 119.5 72.1 ;
        RECT 98.35 69.764 98.6 74.42 ;
        RECT 93.85 74.264 98.35 74.67 ;
        RECT 96.85 71.264 119.5 72.1 ;
        RECT 98.1 70.014 98.35 74.67 ;
        RECT 93.6 74.514 98.1 74.92 ;
        RECT 97.1 71.014 119.5 72.1 ;
        RECT 97.85 70.264 98.1 74.92 ;
        RECT 93.35 74.764 97.85 75.17 ;
        RECT 97.35 70.764 119.5 72.1 ;
        RECT 97.6 70.514 97.85 75.17 ;
        RECT 93.1 75.014 97.6 75.42 ;
        RECT 92.85 75.264 97.35 75.67 ;
        RECT 92.6 75.514 97.1 75.92 ;
        RECT 92.35 75.764 96.85 76.17 ;
        RECT 92.1 76.014 96.6 76.42 ;
        RECT 91.85 76.264 96.35 76.67 ;
        RECT 91.6 76.514 96.1 76.92 ;
        RECT 91.35 76.764 95.85 77.17 ;
        RECT 91.1 77.014 95.6 77.42 ;
        RECT 90.85 77.264 95.35 77.67 ;
        RECT 90.6 77.514 95.1 77.92 ;
        RECT 90.35 77.764 94.85 78.17 ;
        RECT 90.1 78.014 94.6 78.42 ;
        RECT 89.85 78.264 94.35 78.67 ;
        RECT 89.6 78.514 94.1 78.92 ;
        RECT 89.35 78.764 93.85 79.17 ;
        RECT 89.1 79.014 93.6 79.42 ;
        RECT 88.85 79.264 93.35 79.67 ;
        RECT 88.6 79.514 93.1 79.92 ;
        RECT 88.35 79.764 92.85 80.17 ;
        RECT 88.1 80.014 92.6 80.42 ;
        RECT 87.85 80.264 92.35 80.67 ;
        RECT 87.6 80.514 92.1 80.92 ;
        RECT 87.35 80.764 91.85 81.17 ;
        RECT 87.1 81.014 91.6 81.42 ;
        RECT 86.85 81.264 91.35 81.67 ;
        RECT 86.6 81.514 91.1 81.92 ;
        RECT 86.35 81.764 90.85 82.17 ;
        RECT 86.1 82.014 90.6 82.42 ;
        RECT 85.85 82.264 90.35 82.67 ;
        RECT 85.6 82.514 90.1 82.92 ;
        RECT 85.35 82.764 89.85 83.17 ;
        RECT 85.1 83.014 89.6 83.42 ;
        RECT 84.85 83.264 89.35 83.67 ;
        RECT 84.6 83.514 89.1 83.92 ;
        RECT 84.35 83.764 88.85 84.17 ;
        RECT 84.1 84.014 88.6 84.42 ;
        RECT 83.85 84.264 88.35 84.67 ;
        RECT 83.6 84.514 88.1 84.92 ;
        RECT 83.35 84.764 87.85 85.17 ;
        RECT 83.1 85.014 87.6 85.42 ;
        RECT 82.85 85.264 87.35 85.67 ;
        RECT 82.6 85.514 87.1 85.92 ;
        RECT 82.35 85.764 86.85 86.17 ;
        RECT 82.1 86.014 86.6 86.42 ;
        RECT 81.85 86.264 86.35 86.67 ;
        RECT 81.6 86.514 86.1 86.92 ;
        RECT 81.35 86.764 85.85 87.17 ;
        RECT 81.1 87.014 85.6 87.42 ;
        RECT 80.85 87.264 85.35 87.67 ;
        RECT 80.6 87.514 85.1 87.92 ;
        RECT 80.35 87.764 84.85 88.17 ;
        RECT 80.1 88.014 84.6 88.42 ;
        RECT 79.85 88.264 84.35 88.67 ;
        RECT 79.6 88.514 84.1 88.92 ;
        RECT 79.35 88.764 83.85 89.17 ;
        RECT 79.1 89.014 83.6 89.42 ;
        RECT 78.85 89.264 83.35 89.67 ;
        RECT 78.6 89.514 83.1 89.92 ;
        RECT 78.35 89.764 82.85 90.17 ;
        RECT 78.1 90.014 82.6 90.42 ;
        RECT 77.85 90.264 82.35 90.67 ;
        RECT 77.6 90.514 82.1 90.92 ;
        RECT 77.35 90.764 81.85 91.17 ;
        RECT 77.1 91.014 81.6 91.42 ;
        RECT 76.85 91.264 81.35 91.67 ;
        RECT 76.6 91.514 81.1 91.92 ;
        RECT 76.35 91.764 80.85 92.17 ;
        RECT 76.1 92.014 80.6 92.42 ;
        RECT 75.85 92.264 80.35 92.67 ;
        RECT 75.6 92.514 80.1 92.92 ;
        RECT 75.35 92.764 79.85 93.17 ;
        RECT 75.1 93.014 79.6 93.42 ;
        RECT 74.85 93.264 79.35 93.67 ;
        RECT 74.6 93.514 79.1 93.92 ;
        RECT 74.35 93.764 78.85 94.17 ;
        RECT 74.1 94.014 78.6 94.42 ;
        RECT 73.85 94.264 78.35 94.67 ;
        RECT 73.6 94.514 78.1 94.92 ;
        RECT 73.35 94.764 77.85 95.17 ;
        RECT 73.1 95.014 77.6 95.42 ;
        RECT 72.85 95.264 77.35 95.67 ;
        RECT 72.6 95.514 77.1 95.92 ;
        RECT 72.35 95.764 76.85 96.17 ;
        RECT 72.1 96.014 76.6 96.42 ;
        RECT 71.85 96.264 76.35 96.67 ;
        RECT 71.6 96.514 76.1 96.92 ;
        RECT 71.35 96.764 75.85 97.17 ;
        RECT 71.1 97.014 75.6 97.42 ;
        RECT 70.85 97.264 75.35 97.67 ;
        RECT 70.6 97.514 75.1 97.92 ;
        RECT 70.35 97.764 74.85 98.17 ;
        RECT 70.1 98.014 74.6 98.42 ;
        RECT 69.85 98.264 74.35 98.67 ;
        RECT 69.6 98.514 74.1 98.92 ;
        RECT 69.35 98.764 73.85 99.17 ;
        RECT 69.1 99.014 73.6 99.42 ;
        RECT 68.85 99.264 73.35 99.67 ;
        RECT 68.6 99.514 73.1 99.92 ;
        RECT 68.6 99.514 72.85 100.17 ;
        RECT 68.6 99.514 72.6 100.42 ;
        RECT 68.6 99.514 72.35 100.67 ;
        RECT 68.6 99.514 72.1 119.5 ;
        RECT 101.899 73.415 119.5 76.915 ;
        RECT 98.415 76.774 103.055 76.993 ;
        RECT 97.415 77.774 101.899 78.188 ;
        RECT 97.665 77.524 102.149 77.946 ;
        RECT 101.665 73.532 101.899 78.188 ;
        RECT 97.165 78.024 101.665 78.43 ;
        RECT 97.915 77.274 102.399 77.696 ;
        RECT 101.415 73.774 101.665 78.43 ;
        RECT 96.915 78.274 101.415 78.68 ;
        RECT 98.165 77.024 102.649 77.446 ;
        RECT 101.165 74.024 101.415 78.68 ;
        RECT 96.665 78.524 101.165 78.93 ;
        RECT 98.415 76.774 102.899 77.196 ;
        RECT 100.915 74.274 101.165 78.93 ;
        RECT 96.415 78.774 100.915 79.18 ;
        RECT 98.665 76.524 119.5 76.915 ;
        RECT 100.665 74.524 100.915 79.18 ;
        RECT 96.165 79.024 100.665 79.43 ;
        RECT 98.915 76.274 119.5 76.915 ;
        RECT 100.415 74.774 100.665 79.43 ;
        RECT 95.915 79.274 100.415 79.68 ;
        RECT 99.165 76.024 119.5 76.915 ;
        RECT 100.165 75.024 100.415 79.68 ;
        RECT 95.665 79.524 100.165 79.93 ;
        RECT 99.415 75.774 119.5 76.915 ;
        RECT 99.915 75.274 100.165 79.93 ;
        RECT 95.415 79.774 99.915 80.18 ;
        RECT 99.665 75.524 119.5 76.915 ;
        RECT 95.165 80.024 99.665 80.43 ;
        RECT 94.915 80.274 99.415 80.68 ;
        RECT 94.665 80.524 99.165 80.93 ;
        RECT 94.415 80.774 98.915 81.18 ;
        RECT 94.165 81.024 98.665 81.43 ;
        RECT 93.915 81.274 98.415 81.68 ;
        RECT 93.665 81.524 98.165 81.93 ;
        RECT 93.415 81.774 97.915 82.18 ;
        RECT 93.165 82.024 97.665 82.43 ;
        RECT 92.915 82.274 97.415 82.68 ;
        RECT 92.665 82.524 97.165 82.93 ;
        RECT 92.415 82.774 96.915 83.18 ;
        RECT 92.165 83.024 96.665 83.43 ;
        RECT 91.915 83.274 96.415 83.68 ;
        RECT 91.665 83.524 96.165 83.93 ;
        RECT 91.415 83.774 95.915 84.18 ;
        RECT 91.165 84.024 95.665 84.43 ;
        RECT 90.915 84.274 95.415 84.68 ;
        RECT 90.665 84.524 95.165 84.93 ;
        RECT 90.415 84.774 94.915 85.18 ;
        RECT 90.165 85.024 94.665 85.43 ;
        RECT 89.915 85.274 94.415 85.68 ;
        RECT 89.665 85.524 94.165 85.93 ;
        RECT 89.415 85.774 93.915 86.18 ;
        RECT 89.165 86.024 93.665 86.43 ;
        RECT 88.915 86.274 93.415 86.68 ;
        RECT 88.665 86.524 93.165 86.93 ;
        RECT 88.415 86.774 92.915 87.18 ;
        RECT 88.165 87.024 92.665 87.43 ;
        RECT 87.915 87.274 92.415 87.68 ;
        RECT 87.665 87.524 92.165 87.93 ;
        RECT 87.415 87.774 91.915 88.18 ;
        RECT 87.165 88.024 91.665 88.43 ;
        RECT 86.915 88.274 91.415 88.68 ;
        RECT 86.665 88.524 91.165 88.93 ;
        RECT 86.415 88.774 90.915 89.18 ;
        RECT 86.165 89.024 90.665 89.43 ;
        RECT 85.915 89.274 90.415 89.68 ;
        RECT 85.665 89.524 90.165 89.93 ;
        RECT 85.415 89.774 89.915 90.18 ;
        RECT 85.165 90.024 89.665 90.43 ;
        RECT 84.915 90.274 89.415 90.68 ;
        RECT 84.665 90.524 89.165 90.93 ;
        RECT 84.415 90.774 88.915 91.18 ;
        RECT 84.165 91.024 88.665 91.43 ;
        RECT 83.915 91.274 88.415 91.68 ;
        RECT 83.665 91.524 88.165 91.93 ;
        RECT 83.415 91.774 87.915 92.18 ;
        RECT 83.165 92.024 87.665 92.43 ;
        RECT 82.915 92.274 87.415 92.68 ;
        RECT 82.665 92.524 87.165 92.93 ;
        RECT 82.415 92.774 86.915 93.18 ;
        RECT 82.165 93.024 86.665 93.43 ;
        RECT 81.915 93.274 86.415 93.68 ;
        RECT 81.665 93.524 86.165 93.93 ;
        RECT 81.415 93.774 85.915 94.18 ;
        RECT 81.165 94.024 85.665 94.43 ;
        RECT 80.915 94.274 85.415 94.68 ;
        RECT 80.665 94.524 85.165 94.93 ;
        RECT 80.415 94.774 84.915 95.18 ;
        RECT 80.165 95.024 84.665 95.43 ;
        RECT 79.915 95.274 84.415 95.68 ;
        RECT 79.665 95.524 84.165 95.93 ;
        RECT 79.415 95.774 83.915 96.18 ;
        RECT 79.165 96.024 83.665 96.43 ;
        RECT 78.915 96.274 83.415 96.68 ;
        RECT 78.665 96.524 83.165 96.93 ;
        RECT 78.415 96.774 82.915 97.18 ;
        RECT 78.165 97.024 82.665 97.43 ;
        RECT 77.915 97.274 82.415 97.68 ;
        RECT 77.665 97.524 82.165 97.93 ;
        RECT 77.415 97.774 81.915 98.18 ;
        RECT 77.165 98.024 81.665 98.43 ;
        RECT 76.915 98.274 81.415 98.68 ;
        RECT 76.665 98.524 81.165 98.93 ;
        RECT 76.415 98.774 80.915 99.18 ;
        RECT 76.165 99.024 80.665 99.43 ;
        RECT 75.915 99.274 80.415 99.68 ;
        RECT 75.665 99.524 80.165 99.93 ;
        RECT 75.415 99.774 79.915 100.18 ;
        RECT 75.165 100.024 79.665 100.43 ;
        RECT 74.915 100.274 79.415 100.68 ;
        RECT 74.665 100.524 79.165 100.93 ;
        RECT 74.415 100.774 78.915 101.18 ;
        RECT 74.165 101.024 78.665 101.43 ;
        RECT 73.915 101.274 78.415 101.68 ;
        RECT 73.665 101.524 78.165 101.93 ;
        RECT 73.415 101.774 77.915 102.18 ;
        RECT 73.415 101.774 77.665 102.43 ;
        RECT 73.415 101.774 77.415 102.68 ;
        RECT 73.415 101.774 77.165 102.93 ;
        RECT 73.415 101.774 76.915 119.5 ;
        RECT 104.079 78.315 119.5 81.815 ;
        RECT 100.565 81.704 105.235 81.893 ;
        RECT 99.565 82.704 104.079 82.978 ;
        RECT 99.815 82.454 104.329 82.846 ;
        RECT 104.065 78.322 104.079 82.978 ;
        RECT 100.065 82.204 104.579 82.596 ;
        RECT 103.815 78.454 104.065 83.11 ;
        RECT 99.315 82.954 103.815 83.36 ;
        RECT 100.315 81.954 104.829 82.346 ;
        RECT 103.565 78.704 103.815 83.36 ;
        RECT 99.065 83.204 103.565 83.61 ;
        RECT 100.565 81.704 105.079 82.096 ;
        RECT 103.315 78.954 103.565 83.61 ;
        RECT 98.815 83.454 103.315 83.86 ;
        RECT 100.815 81.454 119.5 81.815 ;
        RECT 103.065 79.204 103.315 83.86 ;
        RECT 98.565 83.704 103.065 84.11 ;
        RECT 101.065 81.204 119.5 81.815 ;
        RECT 102.815 79.454 103.065 84.11 ;
        RECT 98.315 83.954 102.815 84.36 ;
        RECT 101.315 80.954 119.5 81.815 ;
        RECT 102.565 79.704 102.815 84.36 ;
        RECT 98.065 84.204 102.565 84.61 ;
        RECT 101.565 80.704 119.5 81.815 ;
        RECT 102.315 79.954 102.565 84.61 ;
        RECT 97.815 84.454 102.315 84.86 ;
        RECT 101.815 80.454 119.5 81.815 ;
        RECT 102.065 80.204 102.315 84.86 ;
        RECT 97.565 84.704 102.065 85.11 ;
        RECT 97.315 84.954 101.815 85.36 ;
        RECT 97.065 85.204 101.565 85.61 ;
        RECT 96.815 85.454 101.315 85.86 ;
        RECT 96.565 85.704 101.065 86.11 ;
        RECT 96.315 85.954 100.815 86.36 ;
        RECT 96.065 86.204 100.565 86.61 ;
        RECT 95.815 86.454 100.315 86.86 ;
        RECT 95.565 86.704 100.065 87.11 ;
        RECT 95.315 86.954 99.815 87.36 ;
        RECT 95.065 87.204 99.565 87.61 ;
        RECT 94.815 87.454 99.315 87.86 ;
        RECT 94.565 87.704 99.065 88.11 ;
        RECT 94.315 87.954 98.815 88.36 ;
        RECT 94.065 88.204 98.565 88.61 ;
        RECT 93.815 88.454 98.315 88.86 ;
        RECT 93.565 88.704 98.065 89.11 ;
        RECT 93.315 88.954 97.815 89.36 ;
        RECT 93.065 89.204 97.565 89.61 ;
        RECT 92.815 89.454 97.315 89.86 ;
        RECT 92.565 89.704 97.065 90.11 ;
        RECT 92.315 89.954 96.815 90.36 ;
        RECT 92.065 90.204 96.565 90.61 ;
        RECT 91.815 90.454 96.315 90.86 ;
        RECT 91.565 90.704 96.065 91.11 ;
        RECT 91.315 90.954 95.815 91.36 ;
        RECT 91.065 91.204 95.565 91.61 ;
        RECT 90.815 91.454 95.315 91.86 ;
        RECT 90.565 91.704 95.065 92.11 ;
        RECT 90.315 91.954 94.815 92.36 ;
        RECT 90.065 92.204 94.565 92.61 ;
        RECT 89.815 92.454 94.315 92.86 ;
        RECT 89.565 92.704 94.065 93.11 ;
        RECT 89.315 92.954 93.815 93.36 ;
        RECT 89.065 93.204 93.565 93.61 ;
        RECT 88.815 93.454 93.315 93.86 ;
        RECT 88.565 93.704 93.065 94.11 ;
        RECT 88.315 93.954 92.815 94.36 ;
        RECT 88.065 94.204 92.565 94.61 ;
        RECT 87.815 94.454 92.315 94.86 ;
        RECT 87.565 94.704 92.065 95.11 ;
        RECT 87.315 94.954 91.815 95.36 ;
        RECT 87.065 95.204 91.565 95.61 ;
        RECT 86.815 95.454 91.315 95.86 ;
        RECT 86.565 95.704 91.065 96.11 ;
        RECT 86.315 95.954 90.815 96.36 ;
        RECT 86.065 96.204 90.565 96.61 ;
        RECT 85.815 96.454 90.315 96.86 ;
        RECT 85.565 96.704 90.065 97.11 ;
        RECT 85.315 96.954 89.815 97.36 ;
        RECT 85.065 97.204 89.565 97.61 ;
        RECT 84.815 97.454 89.315 97.86 ;
        RECT 84.565 97.704 89.065 98.11 ;
        RECT 84.315 97.954 88.815 98.36 ;
        RECT 84.065 98.204 88.565 98.61 ;
        RECT 83.815 98.454 88.315 98.86 ;
        RECT 83.565 98.704 88.065 99.11 ;
        RECT 83.315 98.954 87.815 99.36 ;
        RECT 83.065 99.204 87.565 99.61 ;
        RECT 82.815 99.454 87.315 99.86 ;
        RECT 82.565 99.704 87.065 100.11 ;
        RECT 82.315 99.954 86.815 100.36 ;
        RECT 82.065 100.204 86.565 100.61 ;
        RECT 81.815 100.454 86.315 100.86 ;
        RECT 81.565 100.704 86.065 101.11 ;
        RECT 81.315 100.954 85.815 101.36 ;
        RECT 81.065 101.204 85.565 101.61 ;
        RECT 80.815 101.454 85.315 101.86 ;
        RECT 80.565 101.704 85.065 102.11 ;
        RECT 80.315 101.954 84.815 102.36 ;
        RECT 80.065 102.204 84.565 102.61 ;
        RECT 79.815 102.454 84.315 102.86 ;
        RECT 79.565 102.704 84.065 103.11 ;
        RECT 79.315 102.954 83.815 103.36 ;
        RECT 79.065 103.204 83.565 103.61 ;
        RECT 78.815 103.454 83.315 103.86 ;
        RECT 78.565 103.704 83.065 104.11 ;
        RECT 78.315 103.954 82.815 104.36 ;
        RECT 78.315 103.954 82.565 104.61 ;
        RECT 78.315 103.954 82.315 104.86 ;
        RECT 78.315 103.954 82.065 105.11 ;
        RECT 78.315 103.954 81.815 119.5 ;
        RECT 106.254 83.215 119.5 86.715 ;
        RECT 102.715 86.629 107.41 86.793 ;
        RECT 101.715 87.629 106.254 87.891 ;
        RECT 101.965 87.379 106.504 87.746 ;
        RECT 106.215 83.234 106.254 87.891 ;
        RECT 102.215 87.129 106.754 87.496 ;
        RECT 105.965 83.379 106.215 88.035 ;
        RECT 101.465 87.879 105.965 88.285 ;
        RECT 102.465 86.879 107.004 87.246 ;
        RECT 105.715 83.629 105.965 88.285 ;
        RECT 101.215 88.129 105.715 88.535 ;
        RECT 102.715 86.629 107.254 86.996 ;
        RECT 105.465 83.879 105.715 88.535 ;
        RECT 100.965 88.379 105.465 88.785 ;
        RECT 102.965 86.379 119.5 86.715 ;
        RECT 105.215 84.129 105.465 88.785 ;
        RECT 100.715 88.629 105.215 89.035 ;
        RECT 103.215 86.129 119.5 86.715 ;
        RECT 104.965 84.379 105.215 89.035 ;
        RECT 100.465 88.879 104.965 89.285 ;
        RECT 103.465 85.879 119.5 86.715 ;
        RECT 104.715 84.629 104.965 89.285 ;
        RECT 100.215 89.129 104.715 89.535 ;
        RECT 103.715 85.629 119.5 86.715 ;
        RECT 104.465 84.879 104.715 89.535 ;
        RECT 99.965 89.379 104.465 89.785 ;
        RECT 103.965 85.379 119.5 86.715 ;
        RECT 104.215 85.129 104.465 89.785 ;
        RECT 99.715 89.629 104.215 90.035 ;
        RECT 99.465 89.879 103.965 90.285 ;
        RECT 99.215 90.129 103.715 90.535 ;
        RECT 98.965 90.379 103.465 90.785 ;
        RECT 98.715 90.629 103.215 91.035 ;
        RECT 98.465 90.879 102.965 91.285 ;
        RECT 98.215 91.129 102.715 91.535 ;
        RECT 97.965 91.379 102.465 91.785 ;
        RECT 97.715 91.629 102.215 92.035 ;
        RECT 97.465 91.879 101.965 92.285 ;
        RECT 97.215 92.129 101.715 92.535 ;
        RECT 96.965 92.379 101.465 92.785 ;
        RECT 96.715 92.629 101.215 93.035 ;
        RECT 96.465 92.879 100.965 93.285 ;
        RECT 96.215 93.129 100.715 93.535 ;
        RECT 95.965 93.379 100.465 93.785 ;
        RECT 95.715 93.629 100.215 94.035 ;
        RECT 95.465 93.879 99.965 94.285 ;
        RECT 95.215 94.129 99.715 94.535 ;
        RECT 94.965 94.379 99.465 94.785 ;
        RECT 94.715 94.629 99.215 95.035 ;
        RECT 94.465 94.879 98.965 95.285 ;
        RECT 94.215 95.129 98.715 95.535 ;
        RECT 93.965 95.379 98.465 95.785 ;
        RECT 93.715 95.629 98.215 96.035 ;
        RECT 93.465 95.879 97.965 96.285 ;
        RECT 93.215 96.129 97.715 96.535 ;
        RECT 92.965 96.379 97.465 96.785 ;
        RECT 92.715 96.629 97.215 97.035 ;
        RECT 92.465 96.879 96.965 97.285 ;
        RECT 92.215 97.129 96.715 97.535 ;
        RECT 91.965 97.379 96.465 97.785 ;
        RECT 91.715 97.629 96.215 98.035 ;
        RECT 91.465 97.879 95.965 98.285 ;
        RECT 91.215 98.129 95.715 98.535 ;
        RECT 90.965 98.379 95.465 98.785 ;
        RECT 90.715 98.629 95.215 99.035 ;
        RECT 90.465 98.879 94.965 99.285 ;
        RECT 90.215 99.129 94.715 99.535 ;
        RECT 89.965 99.379 94.465 99.785 ;
        RECT 89.715 99.629 94.215 100.035 ;
        RECT 89.465 99.879 93.965 100.285 ;
        RECT 89.215 100.129 93.715 100.535 ;
        RECT 88.965 100.379 93.465 100.785 ;
        RECT 88.715 100.629 93.215 101.035 ;
        RECT 88.465 100.879 92.965 101.285 ;
        RECT 88.215 101.129 92.715 101.535 ;
        RECT 87.965 101.379 92.465 101.785 ;
        RECT 87.715 101.629 92.215 102.035 ;
        RECT 87.465 101.879 91.965 102.285 ;
        RECT 87.215 102.129 91.715 102.535 ;
        RECT 86.965 102.379 91.465 102.785 ;
        RECT 86.715 102.629 91.215 103.035 ;
        RECT 86.465 102.879 90.965 103.285 ;
        RECT 86.215 103.129 90.715 103.535 ;
        RECT 85.965 103.379 90.465 103.785 ;
        RECT 85.715 103.629 90.215 104.035 ;
        RECT 85.465 103.879 89.965 104.285 ;
        RECT 85.215 104.129 89.715 104.535 ;
        RECT 84.965 104.379 89.465 104.785 ;
        RECT 84.715 104.629 89.215 105.035 ;
        RECT 84.465 104.879 88.965 105.285 ;
        RECT 84.215 105.129 88.715 105.535 ;
        RECT 83.965 105.379 88.465 105.785 ;
        RECT 83.715 105.629 88.215 106.035 ;
        RECT 83.465 105.879 87.965 106.285 ;
        RECT 83.215 106.129 87.715 106.535 ;
        RECT 83.215 106.129 87.465 106.785 ;
        RECT 83.215 106.129 87.215 107.035 ;
        RECT 83.215 106.129 86.965 107.285 ;
        RECT 83.215 106.129 86.715 119.5 ;
        RECT 86.578 39.2 119.5 42.7 ;
        RECT 82.2 43.453 86.828 43.731 ;
        RECT 86.45 39.264 86.578 43.92 ;
        RECT 81.95 43.703 86.45 44.109 ;
        RECT 82.45 43.203 87.078 43.481 ;
        RECT 86.2 39.453 86.45 44.109 ;
        RECT 81.7 43.953 86.2 44.359 ;
        RECT 82.7 42.953 87.328 43.231 ;
        RECT 85.95 39.703 86.2 44.359 ;
        RECT 81.45 44.203 85.95 44.609 ;
        RECT 82.95 42.703 87.578 42.981 ;
        RECT 85.7 39.953 85.95 44.609 ;
        RECT 81.2 44.453 85.7 44.859 ;
        RECT 83.2 42.453 87.734 42.778 ;
        RECT 85.45 40.203 85.7 44.859 ;
        RECT 80.95 44.703 85.45 45.109 ;
        RECT 83.45 42.203 119.5 42.7 ;
        RECT 85.2 40.453 85.45 45.109 ;
        RECT 80.7 44.953 85.2 45.359 ;
        RECT 83.7 41.953 119.5 42.7 ;
        RECT 84.95 40.703 85.2 45.359 ;
        RECT 80.45 45.203 84.95 45.609 ;
        RECT 83.95 41.703 119.5 42.7 ;
        RECT 84.7 40.953 84.95 45.609 ;
        RECT 80.2 45.453 84.7 45.859 ;
        RECT 84.2 41.453 119.5 42.7 ;
        RECT 84.45 41.203 84.7 45.859 ;
        RECT 79.95 45.703 84.45 46.109 ;
        RECT 79.7 45.953 84.2 46.359 ;
        RECT 79.45 46.203 83.95 46.609 ;
        RECT 79.2 46.453 83.7 46.859 ;
        RECT 78.95 46.703 83.45 47.109 ;
        RECT 78.7 46.953 83.2 47.359 ;
        RECT 78.45 47.203 82.95 47.609 ;
        RECT 78.2 47.453 82.7 47.859 ;
        RECT 77.95 47.703 82.45 48.109 ;
        RECT 77.7 47.953 82.2 48.359 ;
        RECT 77.45 48.203 81.95 48.609 ;
        RECT 77.2 48.453 81.7 48.859 ;
        RECT 76.95 48.703 81.45 49.109 ;
        RECT 76.7 48.953 81.2 49.359 ;
        RECT 76.45 49.203 80.95 49.609 ;
        RECT 76.2 49.453 80.7 49.859 ;
        RECT 75.95 49.703 80.45 50.109 ;
        RECT 75.7 49.953 80.2 50.359 ;
        RECT 75.45 50.203 79.95 50.609 ;
        RECT 75.2 50.453 79.7 50.859 ;
        RECT 74.95 50.703 79.45 51.109 ;
        RECT 74.7 50.953 79.2 51.359 ;
        RECT 74.45 51.203 78.95 51.609 ;
        RECT 74.2 51.453 78.7 51.859 ;
        RECT 73.95 51.703 78.45 52.109 ;
        RECT 73.7 51.953 78.2 52.359 ;
        RECT 73.45 52.203 77.95 52.609 ;
        RECT 73.2 52.453 77.7 52.859 ;
        RECT 72.95 52.703 77.45 53.109 ;
        RECT 72.7 52.953 77.2 53.359 ;
        RECT 72.45 53.203 76.95 53.609 ;
        RECT 72.2 53.453 76.7 53.859 ;
        RECT 71.95 53.703 76.45 54.109 ;
        RECT 71.7 53.953 76.2 54.359 ;
        RECT 71.45 54.203 75.95 54.609 ;
        RECT 71.2 54.453 75.7 54.859 ;
        RECT 70.95 54.703 75.45 55.109 ;
        RECT 70.7 54.953 75.2 55.359 ;
        RECT 70.45 55.203 74.95 55.609 ;
        RECT 70.2 55.453 74.7 55.859 ;
        RECT 69.95 55.703 74.45 56.109 ;
        RECT 69.7 55.953 74.2 56.359 ;
        RECT 69.45 56.203 73.95 56.609 ;
        RECT 69.2 56.453 73.7 56.859 ;
        RECT 68.95 56.703 73.45 57.109 ;
        RECT 68.7 56.953 73.2 57.359 ;
        RECT 68.45 57.203 72.95 57.609 ;
        RECT 68.2 57.453 72.7 57.859 ;
        RECT 67.95 57.703 72.45 58.109 ;
        RECT 67.7 57.953 72.2 58.359 ;
        RECT 67.45 58.203 71.95 58.609 ;
        RECT 67.2 58.453 71.7 58.859 ;
        RECT 66.95 58.703 71.45 59.109 ;
        RECT 66.7 58.953 71.2 59.359 ;
        RECT 66.45 59.203 70.95 59.609 ;
        RECT 66.2 59.453 70.7 59.859 ;
        RECT 65.95 59.703 70.45 60.109 ;
        RECT 65.7 59.953 70.2 60.359 ;
        RECT 65.45 60.203 69.95 60.609 ;
        RECT 65.2 60.453 69.7 60.859 ;
        RECT 64.95 60.703 69.45 61.109 ;
        RECT 64.7 60.953 69.2 61.359 ;
        RECT 64.45 61.203 68.95 61.609 ;
        RECT 64.2 61.453 68.7 61.859 ;
        RECT 63.95 61.703 68.45 62.109 ;
        RECT 63.7 61.953 68.2 62.359 ;
        RECT 63.45 62.203 67.95 62.609 ;
        RECT 63.2 62.453 67.7 62.859 ;
        RECT 62.95 62.703 67.45 63.109 ;
        RECT 62.7 62.953 67.2 63.359 ;
        RECT 62.45 63.203 66.95 63.609 ;
        RECT 62.2 63.453 66.7 63.859 ;
        RECT 61.95 63.703 66.45 64.109 ;
        RECT 61.7 63.953 66.2 64.359 ;
        RECT 61.45 64.203 65.95 64.609 ;
        RECT 61.2 64.453 65.7 64.859 ;
        RECT 60.95 64.703 65.45 65.109 ;
        RECT 60.7 64.953 65.2 65.359 ;
        RECT 60.45 65.203 64.95 65.609 ;
        RECT 60.2 65.453 64.7 65.859 ;
        RECT 59.95 65.703 64.45 66.109 ;
        RECT 59.7 65.953 64.2 66.359 ;
        RECT 59.45 66.203 63.95 66.609 ;
        RECT 59.2 66.453 63.7 66.859 ;
        RECT 58.95 66.703 63.45 67.109 ;
        RECT 58.7 66.953 63.2 67.359 ;
        RECT 58.45 67.203 62.95 67.609 ;
        RECT 58.2 67.453 62.7 67.859 ;
        RECT 57.95 67.703 62.45 68.109 ;
        RECT 57.7 67.953 62.2 68.359 ;
        RECT 57.45 68.203 61.95 68.609 ;
        RECT 57.2 68.453 61.7 68.859 ;
        RECT 56.95 68.703 61.45 69.109 ;
        RECT 56.7 68.953 61.2 69.359 ;
        RECT 56.45 69.203 60.95 69.609 ;
        RECT 56.2 69.453 60.7 69.859 ;
        RECT 55.95 69.703 60.45 70.109 ;
        RECT 55.7 69.953 60.2 70.359 ;
        RECT 55.45 70.203 59.95 70.609 ;
        RECT 55.2 70.453 59.7 70.859 ;
        RECT 54.95 70.703 59.45 71.109 ;
        RECT 54.7 70.953 59.2 71.359 ;
        RECT 54.45 71.203 58.95 71.609 ;
        RECT 54.2 71.453 58.7 71.859 ;
        RECT 53.95 71.703 58.45 72.109 ;
        RECT 53.7 71.953 58.2 72.359 ;
        RECT 53.45 72.203 57.95 72.609 ;
        RECT 53.2 72.453 57.7 72.859 ;
        RECT 52.95 72.703 57.45 73.109 ;
        RECT 52.7 72.953 57.2 73.359 ;
        RECT 52.45 73.203 56.95 73.609 ;
        RECT 52.2 73.453 56.7 73.859 ;
        RECT 51.95 73.703 56.45 74.109 ;
        RECT 51.7 73.953 56.2 74.359 ;
        RECT 51.45 74.203 55.95 74.609 ;
        RECT 51.2 74.453 55.7 74.859 ;
        RECT 50.95 74.703 55.45 75.109 ;
        RECT 50.7 74.953 55.2 75.359 ;
        RECT 50.45 75.203 54.95 75.609 ;
        RECT 50.2 75.453 54.7 75.859 ;
        RECT 49.95 75.703 54.45 76.109 ;
        RECT 49.7 75.953 54.2 76.359 ;
        RECT 49.45 76.203 53.95 76.609 ;
        RECT 49.2 76.453 53.7 76.859 ;
        RECT 48.95 76.703 53.45 77.109 ;
        RECT 48.7 76.953 53.2 77.359 ;
        RECT 48.45 77.203 52.95 77.609 ;
        RECT 48.2 77.453 52.7 77.859 ;
        RECT 47.95 77.703 52.45 78.109 ;
        RECT 47.7 77.953 52.2 78.359 ;
        RECT 47.45 78.203 51.95 78.609 ;
        RECT 47.2 78.453 51.7 78.859 ;
        RECT 46.95 78.703 51.45 79.109 ;
        RECT 46.7 78.953 51.2 79.359 ;
        RECT 46.45 79.203 50.95 79.609 ;
        RECT 46.2 79.453 50.7 79.859 ;
        RECT 45.95 79.703 50.45 80.109 ;
        RECT 45.7 79.953 50.2 80.359 ;
        RECT 45.45 80.203 49.95 80.609 ;
        RECT 45.2 80.453 49.7 80.859 ;
        RECT 44.95 80.703 49.45 81.109 ;
        RECT 44.7 80.953 49.2 81.359 ;
        RECT 44.45 81.203 48.95 81.609 ;
        RECT 44.2 81.453 48.7 81.859 ;
        RECT 43.95 81.703 48.45 82.109 ;
        RECT 43.7 81.953 48.2 82.359 ;
        RECT 43.45 82.203 47.95 82.609 ;
        RECT 43.2 82.453 47.7 82.859 ;
        RECT 42.95 82.703 47.45 83.109 ;
        RECT 42.7 82.953 47.2 83.359 ;
        RECT 42.45 83.203 46.95 83.609 ;
        RECT 42.2 83.453 46.7 83.859 ;
        RECT 41.95 83.703 46.45 84.109 ;
        RECT 41.7 83.953 46.2 84.359 ;
        RECT 41.45 84.203 45.95 84.609 ;
        RECT 41.2 84.453 45.7 84.859 ;
        RECT 40.95 84.703 45.45 85.109 ;
        RECT 40.7 84.953 45.2 85.359 ;
        RECT 40.45 85.203 44.95 85.609 ;
        RECT 40.2 85.453 44.7 85.859 ;
        RECT 39.95 85.703 44.45 86.109 ;
        RECT 39.7 85.953 44.2 86.359 ;
        RECT 39.45 86.203 43.95 86.609 ;
        RECT 39.2 86.453 43.7 86.859 ;
        RECT 39.2 86.453 43.45 87.109 ;
        RECT 39.2 86.453 43.2 87.359 ;
        RECT 39.2 86.453 42.95 87.609 ;
        RECT 39.2 86.453 42.7 119.5 ;
        RECT 88.753 44.1 119.5 47.6 ;
        RECT 84.35 48.378 89.003 48.631 ;
        RECT 88.6 44.176 88.753 48.833 ;
        RECT 84.1 48.628 88.6 49.034 ;
        RECT 84.6 48.128 89.253 48.381 ;
        RECT 88.35 44.378 88.6 49.034 ;
        RECT 83.85 48.878 88.35 49.284 ;
        RECT 84.85 47.878 89.503 48.131 ;
        RECT 88.1 44.628 88.35 49.284 ;
        RECT 83.6 49.128 88.1 49.534 ;
        RECT 85.1 47.628 89.753 47.881 ;
        RECT 87.85 44.878 88.1 49.534 ;
        RECT 83.35 49.378 87.85 49.784 ;
        RECT 85.35 47.378 89.909 47.678 ;
        RECT 87.6 45.128 87.85 49.784 ;
        RECT 83.1 49.628 87.6 50.034 ;
        RECT 85.6 47.128 119.5 47.6 ;
        RECT 87.35 45.378 87.6 50.034 ;
        RECT 82.85 49.878 87.35 50.284 ;
        RECT 85.85 46.878 119.5 47.6 ;
        RECT 87.1 45.628 87.35 50.284 ;
        RECT 82.6 50.128 87.1 50.534 ;
        RECT 86.1 46.628 119.5 47.6 ;
        RECT 86.85 45.878 87.1 50.534 ;
        RECT 82.35 50.378 86.85 50.784 ;
        RECT 86.35 46.378 119.5 47.6 ;
        RECT 86.6 46.128 86.85 50.784 ;
        RECT 82.1 50.628 86.6 51.034 ;
        RECT 81.85 50.878 86.35 51.284 ;
        RECT 81.6 51.128 86.1 51.534 ;
        RECT 81.35 51.378 85.85 51.784 ;
        RECT 81.1 51.628 85.6 52.034 ;
        RECT 80.85 51.878 85.35 52.284 ;
        RECT 80.6 52.128 85.1 52.534 ;
        RECT 80.35 52.378 84.85 52.784 ;
        RECT 80.1 52.628 84.6 53.034 ;
        RECT 79.85 52.878 84.35 53.284 ;
        RECT 79.6 53.128 84.1 53.534 ;
        RECT 79.35 53.378 83.85 53.784 ;
        RECT 79.1 53.628 83.6 54.034 ;
        RECT 78.85 53.878 83.35 54.284 ;
        RECT 78.6 54.128 83.1 54.534 ;
        RECT 78.35 54.378 82.85 54.784 ;
        RECT 78.1 54.628 82.6 55.034 ;
        RECT 77.85 54.878 82.35 55.284 ;
        RECT 77.6 55.128 82.1 55.534 ;
        RECT 77.35 55.378 81.85 55.784 ;
        RECT 77.1 55.628 81.6 56.034 ;
        RECT 76.85 55.878 81.35 56.284 ;
        RECT 76.6 56.128 81.1 56.534 ;
        RECT 76.35 56.378 80.85 56.784 ;
        RECT 76.1 56.628 80.6 57.034 ;
        RECT 75.85 56.878 80.35 57.284 ;
        RECT 75.6 57.128 80.1 57.534 ;
        RECT 75.35 57.378 79.85 57.784 ;
        RECT 75.1 57.628 79.6 58.034 ;
        RECT 74.85 57.878 79.35 58.284 ;
        RECT 74.6 58.128 79.1 58.534 ;
        RECT 74.35 58.378 78.85 58.784 ;
        RECT 74.1 58.628 78.6 59.034 ;
        RECT 73.85 58.878 78.35 59.284 ;
        RECT 73.6 59.128 78.1 59.534 ;
        RECT 73.35 59.378 77.85 59.784 ;
        RECT 73.1 59.628 77.6 60.034 ;
        RECT 72.85 59.878 77.35 60.284 ;
        RECT 72.6 60.128 77.1 60.534 ;
        RECT 72.35 60.378 76.85 60.784 ;
        RECT 72.1 60.628 76.6 61.034 ;
        RECT 71.85 60.878 76.35 61.284 ;
        RECT 71.6 61.128 76.1 61.534 ;
        RECT 71.35 61.378 75.85 61.784 ;
        RECT 71.1 61.628 75.6 62.034 ;
        RECT 70.85 61.878 75.35 62.284 ;
        RECT 70.6 62.128 75.1 62.534 ;
        RECT 70.35 62.378 74.85 62.784 ;
        RECT 70.1 62.628 74.6 63.034 ;
        RECT 69.85 62.878 74.35 63.284 ;
        RECT 69.6 63.128 74.1 63.534 ;
        RECT 69.35 63.378 73.85 63.784 ;
        RECT 69.1 63.628 73.6 64.034 ;
        RECT 68.85 63.878 73.35 64.284 ;
        RECT 68.6 64.128 73.1 64.534 ;
        RECT 68.35 64.378 72.85 64.784 ;
        RECT 68.1 64.628 72.6 65.034 ;
        RECT 67.85 64.878 72.35 65.284 ;
        RECT 67.6 65.128 72.1 65.534 ;
        RECT 67.35 65.378 71.85 65.784 ;
        RECT 67.1 65.628 71.6 66.034 ;
        RECT 66.85 65.878 71.35 66.284 ;
        RECT 66.6 66.128 71.1 66.534 ;
        RECT 66.35 66.378 70.85 66.784 ;
        RECT 66.1 66.628 70.6 67.034 ;
        RECT 65.85 66.878 70.35 67.284 ;
        RECT 65.6 67.128 70.1 67.534 ;
        RECT 65.35 67.378 69.85 67.784 ;
        RECT 65.1 67.628 69.6 68.034 ;
        RECT 64.85 67.878 69.35 68.284 ;
        RECT 64.6 68.128 69.1 68.534 ;
        RECT 64.35 68.378 68.85 68.784 ;
        RECT 64.1 68.628 68.6 69.034 ;
        RECT 63.85 68.878 68.35 69.284 ;
        RECT 63.6 69.128 68.1 69.534 ;
        RECT 63.35 69.378 67.85 69.784 ;
        RECT 63.1 69.628 67.6 70.034 ;
        RECT 62.85 69.878 67.35 70.284 ;
        RECT 62.6 70.128 67.1 70.534 ;
        RECT 62.35 70.378 66.85 70.784 ;
        RECT 62.1 70.628 66.6 71.034 ;
        RECT 61.85 70.878 66.35 71.284 ;
        RECT 61.6 71.128 66.1 71.534 ;
        RECT 61.35 71.378 65.85 71.784 ;
        RECT 61.1 71.628 65.6 72.034 ;
        RECT 60.85 71.878 65.35 72.284 ;
        RECT 60.6 72.128 65.1 72.534 ;
        RECT 60.35 72.378 64.85 72.784 ;
        RECT 60.1 72.628 64.6 73.034 ;
        RECT 59.85 72.878 64.35 73.284 ;
        RECT 59.6 73.128 64.1 73.534 ;
        RECT 59.35 73.378 63.85 73.784 ;
        RECT 59.1 73.628 63.6 74.034 ;
        RECT 58.85 73.878 63.35 74.284 ;
        RECT 58.6 74.128 63.1 74.534 ;
        RECT 58.35 74.378 62.85 74.784 ;
        RECT 58.1 74.628 62.6 75.034 ;
        RECT 57.85 74.878 62.35 75.284 ;
        RECT 57.6 75.128 62.1 75.534 ;
        RECT 57.35 75.378 61.85 75.784 ;
        RECT 57.1 75.628 61.6 76.034 ;
        RECT 56.85 75.878 61.35 76.284 ;
        RECT 56.6 76.128 61.1 76.534 ;
        RECT 56.35 76.378 60.85 76.784 ;
        RECT 56.1 76.628 60.6 77.034 ;
        RECT 55.85 76.878 60.35 77.284 ;
        RECT 55.6 77.128 60.1 77.534 ;
        RECT 55.35 77.378 59.85 77.784 ;
        RECT 55.1 77.628 59.6 78.034 ;
        RECT 54.85 77.878 59.35 78.284 ;
        RECT 54.6 78.128 59.1 78.534 ;
        RECT 54.35 78.378 58.85 78.784 ;
        RECT 54.1 78.628 58.6 79.034 ;
        RECT 53.85 78.878 58.35 79.284 ;
        RECT 53.6 79.128 58.1 79.534 ;
        RECT 53.35 79.378 57.85 79.784 ;
        RECT 53.1 79.628 57.6 80.034 ;
        RECT 52.85 79.878 57.35 80.284 ;
        RECT 52.6 80.128 57.1 80.534 ;
        RECT 52.35 80.378 56.85 80.784 ;
        RECT 52.1 80.628 56.6 81.034 ;
        RECT 51.85 80.878 56.35 81.284 ;
        RECT 51.6 81.128 56.1 81.534 ;
        RECT 51.35 81.378 55.85 81.784 ;
        RECT 51.1 81.628 55.6 82.034 ;
        RECT 50.85 81.878 55.35 82.284 ;
        RECT 50.6 82.128 55.1 82.534 ;
        RECT 50.35 82.378 54.85 82.784 ;
        RECT 50.1 82.628 54.6 83.034 ;
        RECT 49.85 82.878 54.35 83.284 ;
        RECT 49.6 83.128 54.1 83.534 ;
        RECT 49.35 83.378 53.85 83.784 ;
        RECT 49.1 83.628 53.6 84.034 ;
        RECT 48.85 83.878 53.35 84.284 ;
        RECT 48.6 84.128 53.1 84.534 ;
        RECT 48.35 84.378 52.85 84.784 ;
        RECT 48.1 84.628 52.6 85.034 ;
        RECT 47.85 84.878 52.35 85.284 ;
        RECT 47.6 85.128 52.1 85.534 ;
        RECT 47.35 85.378 51.85 85.784 ;
        RECT 47.1 85.628 51.6 86.034 ;
        RECT 46.85 85.878 51.35 86.284 ;
        RECT 46.6 86.128 51.1 86.534 ;
        RECT 46.35 86.378 50.85 86.784 ;
        RECT 46.1 86.628 50.6 87.034 ;
        RECT 45.85 86.878 50.35 87.284 ;
        RECT 45.6 87.128 50.1 87.534 ;
        RECT 45.35 87.378 49.85 87.784 ;
        RECT 45.1 87.628 49.6 88.034 ;
        RECT 44.85 87.878 49.35 88.284 ;
        RECT 44.6 88.128 49.1 88.534 ;
        RECT 44.35 88.378 48.85 88.784 ;
        RECT 44.1 88.628 48.6 89.034 ;
        RECT 44.1 88.628 48.35 89.284 ;
        RECT 44.1 88.628 48.1 89.534 ;
        RECT 44.1 88.628 47.85 89.784 ;
        RECT 44.1 88.628 47.6 119.5 ;
        RECT 90.933 49 119.5 52.5 ;
        RECT 87.25 52.558 91.933 52.781 ;
        RECT 86.5 53.308 90.933 53.748 ;
        RECT 86.75 53.058 91.183 53.531 ;
        RECT 90.75 49.091 90.933 53.748 ;
        RECT 86.25 53.558 90.75 53.964 ;
        RECT 87 52.808 91.433 53.281 ;
        RECT 90.5 49.308 90.75 53.964 ;
        RECT 86 53.808 90.5 54.214 ;
        RECT 87.25 52.558 91.683 53.031 ;
        RECT 90.25 49.558 90.5 54.214 ;
        RECT 85.75 54.058 90.25 54.464 ;
        RECT 87.5 52.308 92.089 52.578 ;
        RECT 90 49.808 90.25 54.464 ;
        RECT 85.5 54.308 90 54.714 ;
        RECT 87.75 52.058 119.5 52.5 ;
        RECT 89.75 50.058 90 54.714 ;
        RECT 85.25 54.558 89.75 54.964 ;
        RECT 88 51.808 119.5 52.5 ;
        RECT 89.5 50.308 89.75 54.964 ;
        RECT 85 54.808 89.5 55.214 ;
        RECT 88.25 51.558 119.5 52.5 ;
        RECT 89.25 50.558 89.5 55.214 ;
        RECT 84.75 55.058 89.25 55.464 ;
        RECT 88.5 51.308 119.5 52.5 ;
        RECT 89 50.808 89.25 55.464 ;
        RECT 84.5 55.308 89 55.714 ;
        RECT 88.75 51.058 119.5 52.5 ;
        RECT 84.25 55.558 88.75 55.964 ;
        RECT 84 55.808 88.5 56.214 ;
        RECT 83.75 56.058 88.25 56.464 ;
        RECT 83.5 56.308 88 56.714 ;
        RECT 83.25 56.558 87.75 56.964 ;
        RECT 83 56.808 87.5 57.214 ;
        RECT 82.75 57.058 87.25 57.464 ;
        RECT 82.5 57.308 87 57.714 ;
        RECT 82.25 57.558 86.75 57.964 ;
        RECT 82 57.808 86.5 58.214 ;
        RECT 81.75 58.058 86.25 58.464 ;
        RECT 81.5 58.308 86 58.714 ;
        RECT 81.25 58.558 85.75 58.964 ;
        RECT 81 58.808 85.5 59.214 ;
        RECT 80.75 59.058 85.25 59.464 ;
        RECT 80.5 59.308 85 59.714 ;
        RECT 80.25 59.558 84.75 59.964 ;
        RECT 80 59.808 84.5 60.214 ;
        RECT 79.75 60.058 84.25 60.464 ;
        RECT 79.5 60.308 84 60.714 ;
        RECT 79.25 60.558 83.75 60.964 ;
        RECT 79 60.808 83.5 61.214 ;
        RECT 78.75 61.058 83.25 61.464 ;
        RECT 78.5 61.308 83 61.714 ;
        RECT 78.25 61.558 82.75 61.964 ;
        RECT 78 61.808 82.5 62.214 ;
        RECT 77.75 62.058 82.25 62.464 ;
        RECT 77.5 62.308 82 62.714 ;
        RECT 77.25 62.558 81.75 62.964 ;
        RECT 77 62.808 81.5 63.214 ;
        RECT 76.75 63.058 81.25 63.464 ;
        RECT 76.5 63.308 81 63.714 ;
        RECT 76.25 63.558 80.75 63.964 ;
        RECT 76 63.808 80.5 64.214 ;
        RECT 75.75 64.058 80.25 64.464 ;
        RECT 75.5 64.308 80 64.714 ;
        RECT 75.25 64.558 79.75 64.964 ;
        RECT 75 64.808 79.5 65.214 ;
        RECT 74.75 65.058 79.25 65.464 ;
        RECT 74.5 65.308 79 65.714 ;
        RECT 74.25 65.558 78.75 65.964 ;
        RECT 74 65.808 78.5 66.214 ;
        RECT 73.75 66.058 78.25 66.464 ;
        RECT 73.5 66.308 78 66.714 ;
        RECT 73.25 66.558 77.75 66.964 ;
        RECT 73 66.808 77.5 67.214 ;
        RECT 72.75 67.058 77.25 67.464 ;
        RECT 72.5 67.308 77 67.714 ;
        RECT 72.25 67.558 76.75 67.964 ;
        RECT 72 67.808 76.5 68.214 ;
        RECT 71.75 68.058 76.25 68.464 ;
        RECT 71.5 68.308 76 68.714 ;
        RECT 71.25 68.558 75.75 68.964 ;
        RECT 71 68.808 75.5 69.214 ;
        RECT 70.75 69.058 75.25 69.464 ;
        RECT 70.5 69.308 75 69.714 ;
        RECT 70.25 69.558 74.75 69.964 ;
        RECT 70 69.808 74.5 70.214 ;
        RECT 69.75 70.058 74.25 70.464 ;
        RECT 69.5 70.308 74 70.714 ;
        RECT 69.25 70.558 73.75 70.964 ;
        RECT 69 70.808 73.5 71.214 ;
        RECT 68.75 71.058 73.25 71.464 ;
        RECT 68.5 71.308 73 71.714 ;
        RECT 68.25 71.558 72.75 71.964 ;
        RECT 68 71.808 72.5 72.214 ;
        RECT 67.75 72.058 72.25 72.464 ;
        RECT 67.5 72.308 72 72.714 ;
        RECT 67.25 72.558 71.75 72.964 ;
        RECT 67 72.808 71.5 73.214 ;
        RECT 66.75 73.058 71.25 73.464 ;
        RECT 66.5 73.308 71 73.714 ;
        RECT 66.25 73.558 70.75 73.964 ;
        RECT 66 73.808 70.5 74.214 ;
        RECT 65.75 74.058 70.25 74.464 ;
        RECT 65.5 74.308 70 74.714 ;
        RECT 65.25 74.558 69.75 74.964 ;
        RECT 65 74.808 69.5 75.214 ;
        RECT 64.75 75.058 69.25 75.464 ;
        RECT 64.5 75.308 69 75.714 ;
        RECT 64.25 75.558 68.75 75.964 ;
        RECT 64 75.808 68.5 76.214 ;
        RECT 63.75 76.058 68.25 76.464 ;
        RECT 63.5 76.308 68 76.714 ;
        RECT 63.25 76.558 67.75 76.964 ;
        RECT 63 76.808 67.5 77.214 ;
        RECT 62.75 77.058 67.25 77.464 ;
        RECT 62.5 77.308 67 77.714 ;
        RECT 62.25 77.558 66.75 77.964 ;
        RECT 62 77.808 66.5 78.214 ;
        RECT 61.75 78.058 66.25 78.464 ;
        RECT 61.5 78.308 66 78.714 ;
        RECT 61.25 78.558 65.75 78.964 ;
        RECT 61 78.808 65.5 79.214 ;
        RECT 60.75 79.058 65.25 79.464 ;
        RECT 60.5 79.308 65 79.714 ;
        RECT 60.25 79.558 64.75 79.964 ;
        RECT 60 79.808 64.5 80.214 ;
        RECT 59.75 80.058 64.25 80.464 ;
        RECT 59.5 80.308 64 80.714 ;
        RECT 59.25 80.558 63.75 80.964 ;
        RECT 59 80.808 63.5 81.214 ;
        RECT 58.75 81.058 63.25 81.464 ;
        RECT 58.5 81.308 63 81.714 ;
        RECT 58.25 81.558 62.75 81.964 ;
        RECT 58 81.808 62.5 82.214 ;
        RECT 57.75 82.058 62.25 82.464 ;
        RECT 57.5 82.308 62 82.714 ;
        RECT 57.25 82.558 61.75 82.964 ;
        RECT 57 82.808 61.5 83.214 ;
        RECT 56.75 83.058 61.25 83.464 ;
        RECT 56.5 83.308 61 83.714 ;
        RECT 56.25 83.558 60.75 83.964 ;
        RECT 56 83.808 60.5 84.214 ;
        RECT 55.75 84.058 60.25 84.464 ;
        RECT 55.5 84.308 60 84.714 ;
        RECT 55.25 84.558 59.75 84.964 ;
        RECT 55 84.808 59.5 85.214 ;
        RECT 54.75 85.058 59.25 85.464 ;
        RECT 54.5 85.308 59 85.714 ;
        RECT 54.25 85.558 58.75 85.964 ;
        RECT 54 85.808 58.5 86.214 ;
        RECT 53.75 86.058 58.25 86.464 ;
        RECT 53.5 86.308 58 86.714 ;
        RECT 53.25 86.558 57.75 86.964 ;
        RECT 53 86.808 57.5 87.214 ;
        RECT 52.75 87.058 57.25 87.464 ;
        RECT 52.5 87.308 57 87.714 ;
        RECT 52.25 87.558 56.75 87.964 ;
        RECT 52 87.808 56.5 88.214 ;
        RECT 51.75 88.058 56.25 88.464 ;
        RECT 51.5 88.308 56 88.714 ;
        RECT 51.25 88.558 55.75 88.964 ;
        RECT 51 88.808 55.5 89.214 ;
        RECT 50.75 89.058 55.25 89.464 ;
        RECT 50.5 89.308 55 89.714 ;
        RECT 50.25 89.558 54.75 89.964 ;
        RECT 50 89.808 54.5 90.214 ;
        RECT 49.75 90.058 54.25 90.464 ;
        RECT 49.5 90.308 54 90.714 ;
        RECT 49.25 90.558 53.75 90.964 ;
        RECT 49 90.808 53.5 91.214 ;
        RECT 49 90.808 53.25 91.464 ;
        RECT 49 90.808 53 91.714 ;
        RECT 49 90.808 52.75 91.964 ;
        RECT 49 90.808 52.5 119.5 ;
        RECT 93.108 53.9 119.5 57.4 ;
        RECT 89.65 57.233 94.264 57.478 ;
        RECT 88.65 58.233 93.108 58.66 ;
        RECT 88.9 57.983 93.358 58.431 ;
        RECT 92.9 54.004 93.108 58.66 ;
        RECT 88.4 58.483 92.9 58.889 ;
        RECT 89.15 57.733 93.608 58.181 ;
        RECT 92.65 54.233 92.9 58.889 ;
        RECT 88.15 58.733 92.65 59.139 ;
        RECT 89.4 57.483 93.858 57.931 ;
        RECT 92.4 54.483 92.65 59.139 ;
        RECT 87.9 58.983 92.4 59.389 ;
        RECT 89.65 57.233 94.108 57.681 ;
        RECT 92.15 54.733 92.4 59.389 ;
        RECT 87.65 59.233 92.15 59.639 ;
        RECT 89.9 56.983 119.5 57.4 ;
        RECT 91.9 54.983 92.15 59.639 ;
        RECT 87.4 59.483 91.9 59.889 ;
        RECT 90.15 56.733 119.5 57.4 ;
        RECT 91.65 55.233 91.9 59.889 ;
        RECT 87.15 59.733 91.65 60.139 ;
        RECT 90.4 56.483 119.5 57.4 ;
        RECT 91.4 55.483 91.65 60.139 ;
        RECT 86.9 59.983 91.4 60.389 ;
        RECT 90.65 56.233 119.5 57.4 ;
        RECT 91.15 55.733 91.4 60.389 ;
        RECT 86.65 60.233 91.15 60.639 ;
        RECT 90.9 55.983 119.5 57.4 ;
        RECT 86.4 60.483 90.9 60.889 ;
        RECT 86.15 60.733 90.65 61.139 ;
        RECT 85.9 60.983 90.4 61.389 ;
        RECT 85.65 61.233 90.15 61.639 ;
        RECT 85.4 61.483 89.9 61.889 ;
        RECT 85.15 61.733 89.65 62.139 ;
        RECT 84.9 61.983 89.4 62.389 ;
        RECT 84.65 62.233 89.15 62.639 ;
        RECT 84.4 62.483 88.9 62.889 ;
        RECT 84.15 62.733 88.65 63.139 ;
        RECT 83.9 62.983 88.4 63.389 ;
        RECT 83.65 63.233 88.15 63.639 ;
        RECT 83.4 63.483 87.9 63.889 ;
        RECT 83.15 63.733 87.65 64.139 ;
        RECT 82.9 63.983 87.4 64.389 ;
        RECT 82.65 64.233 87.15 64.639 ;
        RECT 82.4 64.483 86.9 64.889 ;
        RECT 82.15 64.733 86.65 65.139 ;
        RECT 81.9 64.983 86.4 65.389 ;
        RECT 81.65 65.233 86.15 65.639 ;
        RECT 81.4 65.483 85.9 65.889 ;
        RECT 81.15 65.733 85.65 66.139 ;
        RECT 80.9 65.983 85.4 66.389 ;
        RECT 80.65 66.233 85.15 66.639 ;
        RECT 80.4 66.483 84.9 66.889 ;
        RECT 80.15 66.733 84.65 67.139 ;
        RECT 79.9 66.983 84.4 67.389 ;
        RECT 79.65 67.233 84.15 67.639 ;
        RECT 79.4 67.483 83.9 67.889 ;
        RECT 79.15 67.733 83.65 68.139 ;
        RECT 78.9 67.983 83.4 68.389 ;
        RECT 78.65 68.233 83.15 68.639 ;
        RECT 78.4 68.483 82.9 68.889 ;
        RECT 78.15 68.733 82.65 69.139 ;
        RECT 77.9 68.983 82.4 69.389 ;
        RECT 77.65 69.233 82.15 69.639 ;
        RECT 77.4 69.483 81.9 69.889 ;
        RECT 77.15 69.733 81.65 70.139 ;
        RECT 76.9 69.983 81.4 70.389 ;
        RECT 76.65 70.233 81.15 70.639 ;
        RECT 76.4 70.483 80.9 70.889 ;
        RECT 76.15 70.733 80.65 71.139 ;
        RECT 75.9 70.983 80.4 71.389 ;
        RECT 75.65 71.233 80.15 71.639 ;
        RECT 75.4 71.483 79.9 71.889 ;
        RECT 75.15 71.733 79.65 72.139 ;
        RECT 74.9 71.983 79.4 72.389 ;
        RECT 74.65 72.233 79.15 72.639 ;
        RECT 74.4 72.483 78.9 72.889 ;
        RECT 74.15 72.733 78.65 73.139 ;
        RECT 73.9 72.983 78.4 73.389 ;
        RECT 73.65 73.233 78.15 73.639 ;
        RECT 73.4 73.483 77.9 73.889 ;
        RECT 73.15 73.733 77.65 74.139 ;
        RECT 72.9 73.983 77.4 74.389 ;
        RECT 72.65 74.233 77.15 74.639 ;
        RECT 72.4 74.483 76.9 74.889 ;
        RECT 72.15 74.733 76.65 75.139 ;
        RECT 71.9 74.983 76.4 75.389 ;
        RECT 71.65 75.233 76.15 75.639 ;
        RECT 71.4 75.483 75.9 75.889 ;
        RECT 71.15 75.733 75.65 76.139 ;
        RECT 70.9 75.983 75.4 76.389 ;
        RECT 70.65 76.233 75.15 76.639 ;
        RECT 70.4 76.483 74.9 76.889 ;
        RECT 70.15 76.733 74.65 77.139 ;
        RECT 69.9 76.983 74.4 77.389 ;
        RECT 69.65 77.233 74.15 77.639 ;
        RECT 69.4 77.483 73.9 77.889 ;
        RECT 69.15 77.733 73.65 78.139 ;
        RECT 68.9 77.983 73.4 78.389 ;
        RECT 68.65 78.233 73.15 78.639 ;
        RECT 68.4 78.483 72.9 78.889 ;
        RECT 68.15 78.733 72.65 79.139 ;
        RECT 67.9 78.983 72.4 79.389 ;
        RECT 67.65 79.233 72.15 79.639 ;
        RECT 67.4 79.483 71.9 79.889 ;
        RECT 67.15 79.733 71.65 80.139 ;
        RECT 66.9 79.983 71.4 80.389 ;
        RECT 66.65 80.233 71.15 80.639 ;
        RECT 66.4 80.483 70.9 80.889 ;
        RECT 66.15 80.733 70.65 81.139 ;
        RECT 65.9 80.983 70.4 81.389 ;
        RECT 65.65 81.233 70.15 81.639 ;
        RECT 65.4 81.483 69.9 81.889 ;
        RECT 65.15 81.733 69.65 82.139 ;
        RECT 64.9 81.983 69.4 82.389 ;
        RECT 64.65 82.233 69.15 82.639 ;
        RECT 64.4 82.483 68.9 82.889 ;
        RECT 64.15 82.733 68.65 83.139 ;
        RECT 63.9 82.983 68.4 83.389 ;
        RECT 63.65 83.233 68.15 83.639 ;
        RECT 63.4 83.483 67.9 83.889 ;
        RECT 63.15 83.733 67.65 84.139 ;
        RECT 62.9 83.983 67.4 84.389 ;
        RECT 62.65 84.233 67.15 84.639 ;
        RECT 62.4 84.483 66.9 84.889 ;
        RECT 62.15 84.733 66.65 85.139 ;
        RECT 61.9 84.983 66.4 85.389 ;
        RECT 61.65 85.233 66.15 85.639 ;
        RECT 61.4 85.483 65.9 85.889 ;
        RECT 61.15 85.733 65.65 86.139 ;
        RECT 60.9 85.983 65.4 86.389 ;
        RECT 60.65 86.233 65.15 86.639 ;
        RECT 60.4 86.483 64.9 86.889 ;
        RECT 60.15 86.733 64.65 87.139 ;
        RECT 59.9 86.983 64.4 87.389 ;
        RECT 59.65 87.233 64.15 87.639 ;
        RECT 59.4 87.483 63.9 87.889 ;
        RECT 59.15 87.733 63.65 88.139 ;
        RECT 58.9 87.983 63.4 88.389 ;
        RECT 58.65 88.233 63.15 88.639 ;
        RECT 58.4 88.483 62.9 88.889 ;
        RECT 58.15 88.733 62.65 89.139 ;
        RECT 57.9 88.983 62.4 89.389 ;
        RECT 57.65 89.233 62.15 89.639 ;
        RECT 57.4 89.483 61.9 89.889 ;
        RECT 57.15 89.733 61.65 90.139 ;
        RECT 56.9 89.983 61.4 90.389 ;
        RECT 56.65 90.233 61.15 90.639 ;
        RECT 56.4 90.483 60.9 90.889 ;
        RECT 56.15 90.733 60.65 91.139 ;
        RECT 55.9 90.983 60.4 91.389 ;
        RECT 55.65 91.233 60.15 91.639 ;
        RECT 55.4 91.483 59.9 91.889 ;
        RECT 55.15 91.733 59.65 92.139 ;
        RECT 54.9 91.983 59.4 92.389 ;
        RECT 54.65 92.233 59.15 92.639 ;
        RECT 54.4 92.483 58.9 92.889 ;
        RECT 54.15 92.733 58.65 93.139 ;
        RECT 53.9 92.983 58.4 93.389 ;
        RECT 53.9 92.983 58.15 93.639 ;
        RECT 53.9 92.983 57.9 93.889 ;
        RECT 53.9 92.983 57.65 94.139 ;
        RECT 53.9 92.983 57.4 119.5 ;
        RECT 95.284 58.8 119.5 62.3 ;
        RECT 91.8 62.159 96.44 62.378 ;
        RECT 90.8 63.159 95.284 63.573 ;
        RECT 91.05 62.909 95.534 63.331 ;
        RECT 95.05 58.917 95.284 63.573 ;
        RECT 90.55 63.409 95.05 63.815 ;
        RECT 91.3 62.659 95.784 63.081 ;
        RECT 94.8 59.159 95.05 63.815 ;
        RECT 90.3 63.659 94.8 64.065 ;
        RECT 91.55 62.409 96.034 62.831 ;
        RECT 94.55 59.409 94.8 64.065 ;
        RECT 90.05 63.909 94.55 64.315 ;
        RECT 91.8 62.159 96.284 62.581 ;
        RECT 94.3 59.659 94.55 64.315 ;
        RECT 89.8 64.159 94.3 64.565 ;
        RECT 92.05 61.909 119.5 62.3 ;
        RECT 94.05 59.909 94.3 64.565 ;
        RECT 89.55 64.409 94.05 64.815 ;
        RECT 92.3 61.659 119.5 62.3 ;
        RECT 93.8 60.159 94.05 64.815 ;
        RECT 89.3 64.659 93.8 65.065 ;
        RECT 92.55 61.409 119.5 62.3 ;
        RECT 93.55 60.409 93.8 65.065 ;
        RECT 89.05 64.909 93.55 65.315 ;
        RECT 92.8 61.159 119.5 62.3 ;
        RECT 93.3 60.659 93.55 65.315 ;
        RECT 88.8 65.159 93.3 65.565 ;
        RECT 93.05 60.909 119.5 62.3 ;
        RECT 88.55 65.409 93.05 65.815 ;
        RECT 88.3 65.659 92.8 66.065 ;
        RECT 88.05 65.909 92.55 66.315 ;
        RECT 87.8 66.159 92.3 66.565 ;
        RECT 87.55 66.409 92.05 66.815 ;
        RECT 87.3 66.659 91.8 67.065 ;
        RECT 87.05 66.909 91.55 67.315 ;
        RECT 86.8 67.159 91.3 67.565 ;
        RECT 86.55 67.409 91.05 67.815 ;
        RECT 86.3 67.659 90.8 68.065 ;
        RECT 86.05 67.909 90.55 68.315 ;
        RECT 85.8 68.159 90.3 68.565 ;
        RECT 85.55 68.409 90.05 68.815 ;
        RECT 85.3 68.659 89.8 69.065 ;
        RECT 85.05 68.909 89.55 69.315 ;
        RECT 84.8 69.159 89.3 69.565 ;
        RECT 84.55 69.409 89.05 69.815 ;
        RECT 84.3 69.659 88.8 70.065 ;
        RECT 84.05 69.909 88.55 70.315 ;
        RECT 83.8 70.159 88.3 70.565 ;
        RECT 83.55 70.409 88.05 70.815 ;
        RECT 83.3 70.659 87.8 71.065 ;
        RECT 83.05 70.909 87.55 71.315 ;
        RECT 82.8 71.159 87.3 71.565 ;
        RECT 82.55 71.409 87.05 71.815 ;
        RECT 82.3 71.659 86.8 72.065 ;
        RECT 82.05 71.909 86.55 72.315 ;
        RECT 81.8 72.159 86.3 72.565 ;
        RECT 81.55 72.409 86.05 72.815 ;
        RECT 81.3 72.659 85.8 73.065 ;
        RECT 81.05 72.909 85.55 73.315 ;
        RECT 80.8 73.159 85.3 73.565 ;
        RECT 80.55 73.409 85.05 73.815 ;
        RECT 80.3 73.659 84.8 74.065 ;
        RECT 80.05 73.909 84.55 74.315 ;
        RECT 79.8 74.159 84.3 74.565 ;
        RECT 79.55 74.409 84.05 74.815 ;
        RECT 79.3 74.659 83.8 75.065 ;
        RECT 79.05 74.909 83.55 75.315 ;
        RECT 78.8 75.159 83.3 75.565 ;
        RECT 78.55 75.409 83.05 75.815 ;
        RECT 78.3 75.659 82.8 76.065 ;
        RECT 78.05 75.909 82.55 76.315 ;
        RECT 77.8 76.159 82.3 76.565 ;
        RECT 77.55 76.409 82.05 76.815 ;
        RECT 77.3 76.659 81.8 77.065 ;
        RECT 77.05 76.909 81.55 77.315 ;
        RECT 76.8 77.159 81.3 77.565 ;
        RECT 76.55 77.409 81.05 77.815 ;
        RECT 76.3 77.659 80.8 78.065 ;
        RECT 76.05 77.909 80.55 78.315 ;
        RECT 75.8 78.159 80.3 78.565 ;
        RECT 75.55 78.409 80.05 78.815 ;
        RECT 75.3 78.659 79.8 79.065 ;
        RECT 75.05 78.909 79.55 79.315 ;
        RECT 74.8 79.159 79.3 79.565 ;
        RECT 74.55 79.409 79.05 79.815 ;
        RECT 74.3 79.659 78.8 80.065 ;
        RECT 74.05 79.909 78.55 80.315 ;
        RECT 73.8 80.159 78.3 80.565 ;
        RECT 73.55 80.409 78.05 80.815 ;
        RECT 73.3 80.659 77.8 81.065 ;
        RECT 73.05 80.909 77.55 81.315 ;
        RECT 72.8 81.159 77.3 81.565 ;
        RECT 72.55 81.409 77.05 81.815 ;
        RECT 72.3 81.659 76.8 82.065 ;
        RECT 72.05 81.909 76.55 82.315 ;
        RECT 71.8 82.159 76.3 82.565 ;
        RECT 71.55 82.409 76.05 82.815 ;
        RECT 71.3 82.659 75.8 83.065 ;
        RECT 71.05 82.909 75.55 83.315 ;
        RECT 70.8 83.159 75.3 83.565 ;
        RECT 70.55 83.409 75.05 83.815 ;
        RECT 70.3 83.659 74.8 84.065 ;
        RECT 70.05 83.909 74.55 84.315 ;
        RECT 69.8 84.159 74.3 84.565 ;
        RECT 69.55 84.409 74.05 84.815 ;
        RECT 69.3 84.659 73.8 85.065 ;
        RECT 69.05 84.909 73.55 85.315 ;
        RECT 68.8 85.159 73.3 85.565 ;
        RECT 68.55 85.409 73.05 85.815 ;
        RECT 68.3 85.659 72.8 86.065 ;
        RECT 68.05 85.909 72.55 86.315 ;
        RECT 67.8 86.159 72.3 86.565 ;
        RECT 67.55 86.409 72.05 86.815 ;
        RECT 67.3 86.659 71.8 87.065 ;
        RECT 67.05 86.909 71.55 87.315 ;
        RECT 66.8 87.159 71.3 87.565 ;
        RECT 66.55 87.409 71.05 87.815 ;
        RECT 66.3 87.659 70.8 88.065 ;
        RECT 66.05 87.909 70.55 88.315 ;
        RECT 65.8 88.159 70.3 88.565 ;
        RECT 65.55 88.409 70.05 88.815 ;
        RECT 65.3 88.659 69.8 89.065 ;
        RECT 65.05 88.909 69.55 89.315 ;
        RECT 64.8 89.159 69.3 89.565 ;
        RECT 64.55 89.409 69.05 89.815 ;
        RECT 64.3 89.659 68.8 90.065 ;
        RECT 64.05 89.909 68.55 90.315 ;
        RECT 63.8 90.159 68.3 90.565 ;
        RECT 63.55 90.409 68.05 90.815 ;
        RECT 63.3 90.659 67.8 91.065 ;
        RECT 63.05 90.909 67.55 91.315 ;
        RECT 62.8 91.159 67.3 91.565 ;
        RECT 62.55 91.409 67.05 91.815 ;
        RECT 62.3 91.659 66.8 92.065 ;
        RECT 62.05 91.909 66.55 92.315 ;
        RECT 61.8 92.159 66.3 92.565 ;
        RECT 61.55 92.409 66.05 92.815 ;
        RECT 61.3 92.659 65.8 93.065 ;
        RECT 61.05 92.909 65.55 93.315 ;
        RECT 60.8 93.159 65.3 93.565 ;
        RECT 60.55 93.409 65.05 93.815 ;
        RECT 60.3 93.659 64.8 94.065 ;
        RECT 60.05 93.909 64.55 94.315 ;
        RECT 59.8 94.159 64.3 94.565 ;
        RECT 59.55 94.409 64.05 94.815 ;
        RECT 59.3 94.659 63.8 95.065 ;
        RECT 59.05 94.909 63.55 95.315 ;
        RECT 58.8 95.159 63.3 95.565 ;
        RECT 58.8 95.159 63.05 95.815 ;
        RECT 58.8 95.159 62.8 96.065 ;
        RECT 58.8 95.159 62.55 96.315 ;
        RECT 58.8 95.159 62.3 119.5 ;
        RECT 97.459 63.7 119.5 67.2 ;
        RECT 93.95 67.084 98.615 67.278 ;
        RECT 92.95 68.084 97.459 68.361 ;
        RECT 93.2 67.834 97.709 68.231 ;
        RECT 97.45 63.704 97.459 68.361 ;
        RECT 93.45 67.584 97.959 67.981 ;
        RECT 97.2 63.834 97.45 68.49 ;
        RECT 92.7 68.334 97.2 68.74 ;
        RECT 93.7 67.334 98.209 67.731 ;
        RECT 96.95 64.084 97.2 68.74 ;
        RECT 92.45 68.584 96.95 68.99 ;
        RECT 93.95 67.084 98.459 67.481 ;
        RECT 96.7 64.334 96.95 68.99 ;
        RECT 92.2 68.834 96.7 69.24 ;
        RECT 94.2 66.834 119.5 67.2 ;
        RECT 96.45 64.584 96.7 69.24 ;
        RECT 91.95 69.084 96.45 69.49 ;
        RECT 94.45 66.584 119.5 67.2 ;
        RECT 96.2 64.834 96.45 69.49 ;
        RECT 91.7 69.334 96.2 69.74 ;
        RECT 94.7 66.334 119.5 67.2 ;
        RECT 95.95 65.084 96.2 69.74 ;
        RECT 91.45 69.584 95.95 69.99 ;
        RECT 94.95 66.084 119.5 67.2 ;
        RECT 95.7 65.334 95.95 69.99 ;
        RECT 91.2 69.834 95.7 70.24 ;
        RECT 95.2 65.834 119.5 67.2 ;
        RECT 95.45 65.584 95.7 70.24 ;
        RECT 90.95 70.084 95.45 70.49 ;
        RECT 90.7 70.334 95.2 70.74 ;
        RECT 90.45 70.584 94.95 70.99 ;
        RECT 90.2 70.834 94.7 71.24 ;
        RECT 89.95 71.084 94.45 71.49 ;
        RECT 89.7 71.334 94.2 71.74 ;
        RECT 89.45 71.584 93.95 71.99 ;
        RECT 89.2 71.834 93.7 72.24 ;
        RECT 88.95 72.084 93.45 72.49 ;
        RECT 88.7 72.334 93.2 72.74 ;
        RECT 88.45 72.584 92.95 72.99 ;
        RECT 88.2 72.834 92.7 73.24 ;
        RECT 87.95 73.084 92.45 73.49 ;
        RECT 87.7 73.334 92.2 73.74 ;
        RECT 87.45 73.584 91.95 73.99 ;
        RECT 87.2 73.834 91.7 74.24 ;
        RECT 86.95 74.084 91.45 74.49 ;
        RECT 86.7 74.334 91.2 74.74 ;
        RECT 86.45 74.584 90.95 74.99 ;
        RECT 86.2 74.834 90.7 75.24 ;
        RECT 85.95 75.084 90.45 75.49 ;
        RECT 85.7 75.334 90.2 75.74 ;
        RECT 85.45 75.584 89.95 75.99 ;
        RECT 85.2 75.834 89.7 76.24 ;
        RECT 84.95 76.084 89.45 76.49 ;
        RECT 84.7 76.334 89.2 76.74 ;
        RECT 84.45 76.584 88.95 76.99 ;
        RECT 84.2 76.834 88.7 77.24 ;
        RECT 83.95 77.084 88.45 77.49 ;
        RECT 83.7 77.334 88.2 77.74 ;
        RECT 83.45 77.584 87.95 77.99 ;
        RECT 83.2 77.834 87.7 78.24 ;
        RECT 82.95 78.084 87.45 78.49 ;
        RECT 82.7 78.334 87.2 78.74 ;
        RECT 82.45 78.584 86.95 78.99 ;
        RECT 82.2 78.834 86.7 79.24 ;
        RECT 81.95 79.084 86.45 79.49 ;
        RECT 81.7 79.334 86.2 79.74 ;
        RECT 81.45 79.584 85.95 79.99 ;
        RECT 81.2 79.834 85.7 80.24 ;
        RECT 80.95 80.084 85.45 80.49 ;
        RECT 80.7 80.334 85.2 80.74 ;
        RECT 80.45 80.584 84.95 80.99 ;
        RECT 80.2 80.834 84.7 81.24 ;
        RECT 79.95 81.084 84.45 81.49 ;
        RECT 79.7 81.334 84.2 81.74 ;
        RECT 79.45 81.584 83.95 81.99 ;
        RECT 79.2 81.834 83.7 82.24 ;
        RECT 78.95 82.084 83.45 82.49 ;
        RECT 78.7 82.334 83.2 82.74 ;
        RECT 78.45 82.584 82.95 82.99 ;
        RECT 78.2 82.834 82.7 83.24 ;
        RECT 77.95 83.084 82.45 83.49 ;
        RECT 77.7 83.334 82.2 83.74 ;
        RECT 77.45 83.584 81.95 83.99 ;
        RECT 77.2 83.834 81.7 84.24 ;
        RECT 76.95 84.084 81.45 84.49 ;
        RECT 76.7 84.334 81.2 84.74 ;
        RECT 76.45 84.584 80.95 84.99 ;
        RECT 76.2 84.834 80.7 85.24 ;
        RECT 75.95 85.084 80.45 85.49 ;
        RECT 75.7 85.334 80.2 85.74 ;
        RECT 75.45 85.584 79.95 85.99 ;
        RECT 75.2 85.834 79.7 86.24 ;
        RECT 74.95 86.084 79.45 86.49 ;
        RECT 74.7 86.334 79.2 86.74 ;
        RECT 74.45 86.584 78.95 86.99 ;
        RECT 74.2 86.834 78.7 87.24 ;
        RECT 73.95 87.084 78.45 87.49 ;
        RECT 73.7 87.334 78.2 87.74 ;
        RECT 73.45 87.584 77.95 87.99 ;
        RECT 73.2 87.834 77.7 88.24 ;
        RECT 72.95 88.084 77.45 88.49 ;
        RECT 72.7 88.334 77.2 88.74 ;
        RECT 72.45 88.584 76.95 88.99 ;
        RECT 72.2 88.834 76.7 89.24 ;
        RECT 71.95 89.084 76.45 89.49 ;
        RECT 71.7 89.334 76.2 89.74 ;
        RECT 71.45 89.584 75.95 89.99 ;
        RECT 71.2 89.834 75.7 90.24 ;
        RECT 70.95 90.084 75.45 90.49 ;
        RECT 70.7 90.334 75.2 90.74 ;
        RECT 70.45 90.584 74.95 90.99 ;
        RECT 70.2 90.834 74.7 91.24 ;
        RECT 69.95 91.084 74.45 91.49 ;
        RECT 69.7 91.334 74.2 91.74 ;
        RECT 69.45 91.584 73.95 91.99 ;
        RECT 69.2 91.834 73.7 92.24 ;
        RECT 68.95 92.084 73.45 92.49 ;
        RECT 68.7 92.334 73.2 92.74 ;
        RECT 68.45 92.584 72.95 92.99 ;
        RECT 68.2 92.834 72.7 93.24 ;
        RECT 67.95 93.084 72.45 93.49 ;
        RECT 67.7 93.334 72.2 93.74 ;
        RECT 67.45 93.584 71.95 93.99 ;
        RECT 67.2 93.834 71.7 94.24 ;
        RECT 66.95 94.084 71.45 94.49 ;
        RECT 66.7 94.334 71.2 94.74 ;
        RECT 66.45 94.584 70.95 94.99 ;
        RECT 66.2 94.834 70.7 95.24 ;
        RECT 65.95 95.084 70.45 95.49 ;
        RECT 65.7 95.334 70.2 95.74 ;
        RECT 65.45 95.584 69.95 95.99 ;
        RECT 65.2 95.834 69.7 96.24 ;
    END
  END VDDD
  PIN VSS
    DIRECTION INOUT ;
    USE GROUND ;
    PORT
      LAYER MET4 ;
        RECT 108.436 88.115 119.5 91.615 ;
        RECT 104.865 91.561 109.592 91.693 ;
        RECT 104.115 92.311 108.686 92.646 ;
        RECT 108.365 88.15 108.436 92.807 ;
        RECT 103.865 92.561 108.365 92.967 ;
        RECT 104.365 92.061 108.936 92.396 ;
        RECT 108.115 88.311 108.365 92.967 ;
        RECT 103.615 92.811 108.115 93.217 ;
        RECT 104.615 91.811 109.186 92.146 ;
        RECT 107.865 88.561 108.115 93.217 ;
        RECT 103.365 93.061 107.865 93.467 ;
        RECT 104.865 91.561 109.436 91.896 ;
        RECT 107.615 88.811 107.865 93.467 ;
        RECT 103.115 93.311 107.615 93.717 ;
        RECT 105.115 91.311 119.5 91.615 ;
        RECT 107.365 89.061 107.615 93.717 ;
        RECT 102.865 93.561 107.365 93.967 ;
        RECT 105.365 91.061 119.5 91.615 ;
        RECT 107.115 89.311 107.365 93.967 ;
        RECT 102.615 93.811 107.115 94.217 ;
        RECT 105.615 90.811 119.5 91.615 ;
        RECT 106.865 89.561 107.115 94.217 ;
        RECT 102.365 94.061 106.865 94.467 ;
        RECT 105.865 90.561 119.5 91.615 ;
        RECT 106.615 89.811 106.865 94.467 ;
        RECT 102.115 94.311 106.615 94.717 ;
        RECT 106.115 90.311 119.5 91.615 ;
        RECT 106.365 90.061 106.615 94.717 ;
        RECT 101.865 94.561 106.365 94.967 ;
        RECT 101.615 94.811 106.115 95.217 ;
        RECT 101.365 95.061 105.865 95.467 ;
        RECT 101.115 95.311 105.615 95.717 ;
        RECT 100.865 95.561 105.365 95.967 ;
        RECT 100.615 95.811 105.115 96.217 ;
        RECT 100.365 96.061 104.865 96.467 ;
        RECT 100.115 96.311 104.615 96.717 ;
        RECT 99.865 96.561 104.365 96.967 ;
        RECT 99.615 96.811 104.115 97.217 ;
        RECT 99.365 97.061 103.865 97.467 ;
        RECT 99.115 97.311 103.615 97.717 ;
        RECT 98.865 97.561 103.365 97.967 ;
        RECT 98.615 97.811 103.115 98.217 ;
        RECT 98.365 98.061 102.865 98.467 ;
        RECT 98.115 98.311 102.615 98.717 ;
        RECT 97.865 98.561 102.365 98.967 ;
        RECT 97.615 98.811 102.115 99.217 ;
        RECT 97.365 99.061 101.865 99.467 ;
        RECT 97.115 99.311 101.615 99.717 ;
        RECT 96.865 99.561 101.365 99.967 ;
        RECT 96.615 99.811 101.115 100.217 ;
        RECT 96.365 100.061 100.865 100.467 ;
        RECT 96.115 100.311 100.615 100.717 ;
        RECT 95.865 100.561 100.365 100.967 ;
        RECT 95.615 100.811 100.115 101.217 ;
        RECT 95.365 101.061 99.865 101.467 ;
        RECT 95.115 101.311 99.615 101.717 ;
        RECT 94.865 101.561 99.365 101.967 ;
        RECT 94.615 101.811 99.115 102.217 ;
        RECT 94.365 102.061 98.865 102.467 ;
        RECT 94.115 102.311 98.615 102.717 ;
        RECT 93.865 102.561 98.365 102.967 ;
        RECT 93.615 102.811 98.115 103.217 ;
        RECT 93.365 103.061 97.865 103.467 ;
        RECT 93.115 103.311 97.615 103.717 ;
        RECT 92.865 103.561 97.365 103.967 ;
        RECT 92.615 103.811 97.115 104.217 ;
        RECT 92.365 104.061 96.865 104.467 ;
        RECT 92.115 104.311 96.615 104.717 ;
        RECT 91.865 104.561 96.365 104.967 ;
        RECT 91.615 104.811 96.115 105.217 ;
        RECT 91.365 105.061 95.865 105.467 ;
        RECT 91.115 105.311 95.615 105.717 ;
        RECT 90.865 105.561 95.365 105.967 ;
        RECT 90.615 105.811 95.115 106.217 ;
        RECT 90.365 106.061 94.865 106.467 ;
        RECT 90.115 106.311 94.615 106.717 ;
        RECT 89.865 106.561 94.365 106.967 ;
        RECT 89.615 106.811 94.115 107.217 ;
        RECT 89.365 107.061 93.865 107.467 ;
        RECT 89.115 107.311 93.615 107.717 ;
        RECT 88.865 107.561 93.365 107.967 ;
        RECT 88.615 107.811 93.115 108.217 ;
        RECT 88.365 108.061 92.865 108.467 ;
        RECT 88.115 108.311 92.615 108.717 ;
        RECT 88.115 108.311 92.365 108.967 ;
        RECT 88.115 108.311 92.115 109.217 ;
        RECT 88.115 108.311 91.865 109.467 ;
        RECT 88.115 108.311 91.615 119.5 ;
        RECT 110.526 93.1 119.5 96.6 ;
        RECT 106.85 96.651 111.526 96.881 ;
        RECT 106.1 97.401 110.526 97.844 ;
        RECT 106.35 97.151 110.776 97.631 ;
        RECT 110.35 93.188 110.526 97.844 ;
        RECT 105.85 97.651 110.35 98.057 ;
        RECT 106.6 96.901 111.026 97.381 ;
        RECT 110.1 93.401 110.35 98.057 ;
        RECT 105.6 97.901 110.1 98.307 ;
        RECT 106.85 96.651 111.276 97.131 ;
        RECT 109.85 93.651 110.1 98.307 ;
        RECT 105.35 98.151 109.85 98.557 ;
        RECT 107.1 96.401 111.682 96.678 ;
        RECT 109.6 93.901 109.85 98.557 ;
        RECT 105.1 98.401 109.6 98.807 ;
        RECT 107.35 96.151 119.5 96.6 ;
        RECT 109.35 94.151 109.6 98.807 ;
        RECT 104.85 98.651 109.35 99.057 ;
        RECT 107.6 95.901 119.5 96.6 ;
        RECT 109.1 94.401 109.35 99.057 ;
        RECT 104.6 98.901 109.1 99.307 ;
        RECT 107.85 95.651 119.5 96.6 ;
        RECT 108.85 94.651 109.1 99.307 ;
        RECT 104.35 99.151 108.85 99.557 ;
        RECT 108.1 95.401 119.5 96.6 ;
        RECT 108.6 94.901 108.85 99.557 ;
        RECT 104.1 99.401 108.6 99.807 ;
        RECT 108.35 95.151 119.5 96.6 ;
        RECT 103.85 99.651 108.35 100.057 ;
        RECT 103.6 99.901 108.1 100.307 ;
        RECT 103.35 100.151 107.85 100.557 ;
        RECT 103.1 100.401 107.6 100.807 ;
        RECT 102.85 100.651 107.35 101.057 ;
        RECT 102.6 100.901 107.1 101.307 ;
        RECT 102.35 101.151 106.85 101.557 ;
        RECT 102.1 101.401 106.6 101.807 ;
        RECT 101.85 101.651 106.35 102.057 ;
        RECT 101.6 101.901 106.1 102.307 ;
        RECT 101.35 102.151 105.85 102.557 ;
        RECT 101.1 102.401 105.6 102.807 ;
        RECT 100.85 102.651 105.35 103.057 ;
        RECT 100.6 102.901 105.1 103.307 ;
        RECT 100.35 103.151 104.85 103.557 ;
        RECT 100.1 103.401 104.6 103.807 ;
        RECT 99.85 103.651 104.35 104.057 ;
        RECT 99.6 103.901 104.1 104.307 ;
        RECT 99.35 104.151 103.85 104.557 ;
        RECT 99.1 104.401 103.6 104.807 ;
        RECT 98.85 104.651 103.35 105.057 ;
        RECT 98.6 104.901 103.1 105.307 ;
        RECT 98.35 105.151 102.85 105.557 ;
        RECT 98.1 105.401 102.6 105.807 ;
        RECT 97.85 105.651 102.35 106.057 ;
        RECT 97.6 105.901 102.1 106.307 ;
        RECT 97.35 106.151 101.85 106.557 ;
        RECT 97.1 106.401 101.6 106.807 ;
        RECT 96.85 106.651 101.35 107.057 ;
        RECT 96.6 106.901 101.1 107.307 ;
        RECT 96.35 107.151 100.85 107.557 ;
        RECT 96.1 107.401 100.6 107.807 ;
        RECT 95.85 107.651 100.35 108.057 ;
        RECT 95.6 107.901 100.1 108.307 ;
        RECT 95.35 108.151 99.85 108.557 ;
        RECT 95.1 108.401 99.6 108.807 ;
        RECT 94.85 108.651 99.35 109.057 ;
        RECT 94.6 108.901 99.1 109.307 ;
        RECT 94.35 109.151 98.85 109.557 ;
        RECT 94.1 109.401 98.6 109.807 ;
        RECT 93.85 109.651 98.35 110.057 ;
        RECT 93.6 109.901 98.1 110.307 ;
        RECT 93.35 110.151 97.85 110.557 ;
        RECT 93.1 110.401 97.6 110.807 ;
        RECT 93.1 110.401 97.35 111.057 ;
        RECT 93.1 110.401 97.1 111.307 ;
        RECT 93.1 110.401 96.85 111.557 ;
        RECT 93.1 110.401 96.6 119.5 ;
        RECT 112.703 98 119.5 101.5 ;
        RECT 109 101.578 113.703 101.781 ;
        RECT 108.25 102.328 112.703 102.758 ;
        RECT 108.5 102.078 112.953 102.531 ;
        RECT 112.5 98.101 112.703 102.758 ;
        RECT 108 102.578 112.5 102.984 ;
        RECT 108.75 101.828 113.203 102.281 ;
        RECT 112.25 98.328 112.5 102.984 ;
        RECT 107.75 102.828 112.25 103.234 ;
        RECT 109 101.578 113.453 102.031 ;
        RECT 112 98.578 112.25 103.234 ;
        RECT 107.5 103.078 112 103.484 ;
        RECT 109.25 101.328 113.859 101.578 ;
        RECT 111.75 98.828 112 103.484 ;
        RECT 107.25 103.328 111.75 103.734 ;
        RECT 109.5 101.078 119.5 101.5 ;
        RECT 111.5 99.078 111.75 103.734 ;
        RECT 107 103.578 111.5 103.984 ;
        RECT 109.75 100.828 119.5 101.5 ;
        RECT 111.25 99.328 111.5 103.984 ;
        RECT 106.75 103.828 111.25 104.234 ;
        RECT 110 100.578 119.5 101.5 ;
        RECT 111 99.578 111.25 104.234 ;
        RECT 106.5 104.078 111 104.484 ;
        RECT 110.25 100.328 119.5 101.5 ;
        RECT 110.75 99.828 111 104.484 ;
        RECT 106.25 104.328 110.75 104.734 ;
        RECT 110.5 100.078 119.5 101.5 ;
        RECT 106 104.578 110.5 104.984 ;
        RECT 105.75 104.828 110.25 105.234 ;
        RECT 105.5 105.078 110 105.484 ;
        RECT 105.25 105.328 109.75 105.734 ;
        RECT 105 105.578 109.5 105.984 ;
        RECT 104.75 105.828 109.25 106.234 ;
        RECT 104.5 106.078 109 106.484 ;
        RECT 104.25 106.328 108.75 106.734 ;
        RECT 104 106.578 108.5 106.984 ;
        RECT 103.75 106.828 108.25 107.234 ;
        RECT 103.5 107.078 108 107.484 ;
        RECT 103.25 107.328 107.75 107.734 ;
        RECT 103 107.578 107.5 107.984 ;
        RECT 102.75 107.828 107.25 108.234 ;
        RECT 102.5 108.078 107 108.484 ;
        RECT 102.25 108.328 106.75 108.734 ;
        RECT 102 108.578 106.5 108.984 ;
        RECT 101.75 108.828 106.25 109.234 ;
        RECT 101.5 109.078 106 109.484 ;
        RECT 101.25 109.328 105.75 109.734 ;
        RECT 101 109.578 105.5 109.984 ;
        RECT 100.75 109.828 105.25 110.234 ;
        RECT 100.5 110.078 105 110.484 ;
        RECT 100.25 110.328 104.75 110.734 ;
        RECT 100 110.578 104.5 110.984 ;
        RECT 99.75 110.828 104.25 111.234 ;
        RECT 99.5 111.078 104 111.484 ;
        RECT 99.25 111.328 103.75 111.734 ;
        RECT 99 111.578 103.5 111.984 ;
        RECT 98.75 111.828 103.25 112.234 ;
        RECT 98.5 112.078 103 112.484 ;
        RECT 98.25 112.328 102.75 112.734 ;
        RECT 98 112.578 102.5 112.984 ;
        RECT 98 112.578 102.25 113.234 ;
        RECT 98 112.578 102 113.484 ;
        RECT 98 112.578 101.75 113.734 ;
        RECT 98 112.578 101.5 119.5 ;
    END
  END VSS
  PIN VSSD
    DIRECTION INOUT ;
    USE GROUND ;
    PORT
      LAYER MET4 ;
        RECT 56.95 40.402 61.45 40.808 ;
        RECT 56.7 40.652 61.2 41.058 ;
        RECT 56.45 40.902 60.95 41.308 ;
        RECT 56.2 41.152 60.7 41.558 ;
        RECT 55.95 41.402 60.45 41.808 ;
        RECT 55.7 41.652 60.2 42.058 ;
        RECT 55.45 41.902 59.95 42.308 ;
        RECT 55.2 42.152 59.7 42.558 ;
        RECT 54.95 42.402 59.45 42.808 ;
        RECT 54.7 42.652 59.2 43.058 ;
        RECT 54.45 42.902 58.95 43.308 ;
        RECT 54.2 43.152 58.7 43.558 ;
        RECT 53.95 43.402 58.45 43.808 ;
        RECT 53.7 43.652 58.2 44.058 ;
        RECT 53.45 43.902 57.95 44.308 ;
        RECT 53.2 44.152 57.7 44.558 ;
        RECT 52.95 44.402 57.45 44.808 ;
        RECT 52.7 44.652 57.2 45.058 ;
        RECT 52.45 44.902 56.95 45.308 ;
        RECT 52.2 45.152 56.7 45.558 ;
        RECT 51.95 45.402 56.45 45.808 ;
        RECT 51.7 45.652 56.2 46.058 ;
        RECT 51.45 45.902 55.95 46.308 ;
        RECT 51.2 46.152 55.7 46.558 ;
        RECT 50.95 46.402 55.45 46.808 ;
        RECT 50.7 46.652 55.2 47.058 ;
        RECT 50.45 46.902 54.95 47.308 ;
        RECT 50.2 47.152 54.7 47.558 ;
        RECT 49.95 47.402 54.45 47.808 ;
        RECT 49.7 47.652 54.2 48.058 ;
        RECT 49.45 47.902 53.95 48.308 ;
        RECT 49.2 48.152 53.7 48.558 ;
        RECT 48.95 48.402 53.45 48.808 ;
        RECT 48.7 48.652 53.2 49.058 ;
        RECT 48.45 48.902 52.95 49.308 ;
        RECT 48.2 49.152 52.7 49.558 ;
        RECT 47.95 49.402 52.45 49.808 ;
        RECT 47.7 49.652 52.2 50.058 ;
        RECT 47.45 49.902 51.95 50.308 ;
        RECT 47.2 50.152 51.7 50.558 ;
        RECT 46.95 50.402 51.45 50.808 ;
        RECT 46.7 50.652 51.2 51.058 ;
        RECT 46.45 50.902 50.95 51.308 ;
        RECT 46.2 51.152 50.7 51.558 ;
        RECT 45.95 51.402 50.45 51.808 ;
        RECT 45.7 51.652 50.2 52.058 ;
        RECT 45.45 51.902 49.95 52.308 ;
        RECT 45.2 52.152 49.7 52.558 ;
        RECT 44.95 52.402 49.45 52.808 ;
        RECT 44.7 52.652 49.2 53.058 ;
        RECT 44.45 52.902 48.95 53.308 ;
        RECT 44.2 53.152 48.7 53.558 ;
        RECT 43.95 53.402 48.45 53.808 ;
        RECT 43.7 53.652 48.2 54.058 ;
        RECT 43.45 53.902 47.95 54.308 ;
        RECT 43.2 54.152 47.7 54.558 ;
        RECT 42.95 54.402 47.45 54.808 ;
        RECT 42.7 54.652 47.2 55.058 ;
        RECT 42.45 54.902 46.95 55.308 ;
        RECT 42.2 55.152 46.7 55.558 ;
        RECT 41.95 55.402 46.45 55.808 ;
        RECT 41.7 55.652 46.2 56.058 ;
        RECT 41.45 55.902 45.95 56.308 ;
        RECT 41.2 56.152 45.7 56.558 ;
        RECT 40.95 56.402 45.45 56.808 ;
        RECT 40.7 56.652 45.2 57.058 ;
        RECT 40.45 56.902 44.95 57.308 ;
        RECT 40.2 57.152 44.7 57.558 ;
        RECT 39.95 57.402 44.45 57.808 ;
        RECT 39.7 57.652 44.2 58.058 ;
        RECT 39.45 57.902 43.95 58.308 ;
        RECT 39.2 58.152 43.7 58.558 ;
        RECT 38.95 58.402 43.45 58.808 ;
        RECT 38.7 58.652 43.2 59.058 ;
        RECT 38.45 58.902 42.95 59.308 ;
        RECT 38.2 59.152 42.7 59.558 ;
        RECT 37.95 59.402 42.45 59.808 ;
        RECT 37.7 59.652 42.2 60.058 ;
        RECT 37.45 59.902 41.95 60.308 ;
        RECT 37.2 60.152 41.7 60.558 ;
        RECT 36.95 60.402 41.45 60.808 ;
        RECT 36.7 60.652 41.2 61.058 ;
        RECT 36.45 60.902 40.95 61.308 ;
        RECT 36.2 61.152 40.7 61.558 ;
        RECT 35.95 61.402 40.45 61.808 ;
        RECT 35.7 61.652 40.2 62.058 ;
        RECT 35.45 61.902 39.95 62.308 ;
        RECT 35.2 62.152 39.7 62.558 ;
        RECT 34.95 62.402 39.45 62.808 ;
        RECT 34.7 62.652 39.2 63.058 ;
        RECT 34.45 62.902 38.95 63.308 ;
        RECT 34.2 63.152 38.7 63.558 ;
        RECT 33.95 63.402 38.45 63.808 ;
        RECT 33.7 63.652 38.2 64.058 ;
        RECT 33.45 63.902 37.95 64.308 ;
        RECT 33.2 64.152 37.7 64.558 ;
        RECT 32.95 64.402 37.45 64.808 ;
        RECT 32.7 64.652 37.2 65.058 ;
        RECT 32.45 64.902 36.95 65.308 ;
        RECT 32.2 65.152 36.7 65.558 ;
        RECT 31.95 65.402 36.45 65.808 ;
        RECT 31.7 65.652 36.2 66.058 ;
        RECT 31.45 65.902 35.95 66.308 ;
        RECT 31.2 66.152 35.7 66.558 ;
        RECT 30.95 66.402 35.45 66.808 ;
        RECT 30.7 66.652 35.2 67.058 ;
        RECT 30.45 66.902 34.95 67.308 ;
        RECT 30.2 67.152 34.7 67.558 ;
        RECT 29.95 67.402 34.45 67.808 ;
        RECT 29.7 67.652 34.2 68.058 ;
        RECT 29.45 67.902 33.95 68.308 ;
        RECT 29.2 68.152 33.7 68.558 ;
        RECT 28.95 68.402 33.45 68.808 ;
        RECT 28.7 68.652 33.2 69.058 ;
        RECT 28.45 68.902 32.95 69.308 ;
        RECT 28.2 69.152 32.7 69.558 ;
        RECT 27.95 69.402 32.45 69.808 ;
        RECT 27.7 69.652 32.2 70.058 ;
        RECT 27.45 69.902 31.95 70.308 ;
        RECT 27.2 70.152 31.7 70.558 ;
        RECT 26.95 70.402 31.45 70.808 ;
        RECT 26.7 70.652 31.2 71.058 ;
        RECT 26.45 70.902 30.95 71.308 ;
        RECT 26.2 71.152 30.7 71.558 ;
        RECT 25.95 71.402 30.45 71.808 ;
        RECT 25.7 71.652 30.2 72.058 ;
        RECT 25.45 71.902 29.95 72.308 ;
        RECT 25.2 72.152 29.7 72.558 ;
        RECT 24.95 72.402 29.45 72.808 ;
        RECT 24.7 72.652 29.2 73.058 ;
        RECT 24.45 72.902 28.95 73.308 ;
        RECT 24.2 73.152 28.7 73.558 ;
        RECT 23.95 73.402 28.45 73.808 ;
        RECT 23.7 73.652 28.2 74.058 ;
        RECT 23.45 73.902 27.95 74.308 ;
        RECT 23.2 74.152 27.7 74.558 ;
        RECT 22.95 74.402 27.45 74.808 ;
        RECT 22.7 74.652 27.2 75.058 ;
        RECT 22.45 74.902 26.95 75.308 ;
        RECT 22.2 75.152 26.7 75.558 ;
        RECT 21.95 75.402 26.45 75.808 ;
        RECT 21.7 75.652 26.2 76.058 ;
        RECT 21.45 75.902 25.95 76.308 ;
        RECT 21.2 76.152 25.7 76.558 ;
        RECT 20.95 76.402 25.45 76.808 ;
        RECT 20.7 76.652 25.2 77.058 ;
        RECT 20.45 76.902 24.95 77.308 ;
        RECT 20.2 77.152 24.7 77.558 ;
        RECT 19.95 77.402 24.45 77.808 ;
        RECT 19.7 77.652 24.2 78.058 ;
        RECT 19.45 77.902 23.95 78.308 ;
        RECT 19.2 78.152 23.7 78.558 ;
        RECT 18.95 78.402 23.45 78.808 ;
        RECT 18.7 78.652 23.2 79.058 ;
        RECT 18.45 78.902 22.95 79.308 ;
        RECT 18.2 79.152 22.7 79.558 ;
        RECT 17.95 79.402 22.45 79.808 ;
        RECT 17.7 79.652 22.2 80.058 ;
        RECT 17.45 79.902 21.95 80.308 ;
        RECT 17.2 80.152 21.7 80.558 ;
        RECT 16.95 80.402 21.45 80.808 ;
        RECT 16.7 80.652 21.2 81.058 ;
        RECT 16.45 80.902 20.95 81.308 ;
        RECT 16.2 81.152 20.7 81.558 ;
        RECT 15.95 81.402 20.45 81.808 ;
        RECT 15.7 81.652 20.2 82.058 ;
        RECT 15.45 81.902 19.95 82.308 ;
        RECT 15.2 82.152 19.7 82.558 ;
        RECT 14.95 82.402 19.45 82.808 ;
        RECT 14.7 82.652 19.2 83.058 ;
        RECT 14.7 82.652 18.95 83.308 ;
        RECT 14.7 82.652 18.7 83.558 ;
        RECT 14.7 82.652 18.45 83.808 ;
        RECT 14.7 82.652 18.2 119.5 ;
        RECT 84.957 19.6 119.5 23.1 ;
        RECT 81.35 23.082 86.113 23.178 ;
        RECT 80.6 23.832 85.207 24.131 ;
        RECT 84.85 19.653 84.957 24.31 ;
        RECT 80.35 24.082 84.85 24.488 ;
        RECT 80.85 23.582 85.457 23.881 ;
        RECT 84.6 19.832 84.85 24.488 ;
        RECT 80.1 24.332 84.6 24.738 ;
        RECT 81.1 23.332 85.707 23.631 ;
        RECT 84.35 20.082 84.6 24.738 ;
        RECT 79.85 24.582 84.35 24.988 ;
        RECT 81.35 23.082 85.957 23.381 ;
        RECT 84.1 20.332 84.35 24.988 ;
        RECT 79.6 24.832 84.1 25.238 ;
        RECT 81.6 22.832 119.5 23.1 ;
        RECT 83.85 20.582 84.1 25.238 ;
        RECT 79.35 25.082 83.85 25.488 ;
        RECT 81.85 22.582 119.5 23.1 ;
        RECT 83.6 20.832 83.85 25.488 ;
        RECT 79.1 25.332 83.6 25.738 ;
        RECT 82.1 22.332 119.5 23.1 ;
        RECT 83.35 21.082 83.6 25.738 ;
        RECT 78.85 25.582 83.35 25.988 ;
        RECT 82.35 22.082 119.5 23.1 ;
        RECT 83.1 21.332 83.35 25.988 ;
        RECT 78.6 25.832 83.1 26.238 ;
        RECT 82.6 21.832 119.5 23.1 ;
        RECT 82.85 21.582 83.1 26.238 ;
        RECT 78.35 26.082 82.85 26.488 ;
        RECT 78.1 26.332 82.6 26.738 ;
        RECT 77.85 26.582 82.35 26.988 ;
        RECT 77.6 26.832 82.1 27.238 ;
        RECT 77.35 27.082 81.85 27.488 ;
        RECT 77.1 27.332 81.6 27.738 ;
        RECT 76.85 27.582 81.35 27.988 ;
        RECT 76.6 27.832 81.1 28.238 ;
        RECT 76.35 28.082 80.85 28.488 ;
        RECT 76.1 28.332 80.6 28.738 ;
        RECT 75.85 28.582 80.35 28.988 ;
        RECT 75.6 28.832 80.1 29.238 ;
        RECT 75.35 29.082 79.85 29.488 ;
        RECT 75.1 29.332 79.6 29.738 ;
        RECT 74.85 29.582 79.35 29.988 ;
        RECT 74.6 29.832 79.1 30.238 ;
        RECT 74.35 30.082 78.85 30.488 ;
        RECT 74.1 30.332 78.6 30.738 ;
        RECT 73.85 30.582 78.35 30.988 ;
        RECT 73.6 30.832 78.1 31.238 ;
        RECT 73.35 31.082 77.85 31.488 ;
        RECT 73.1 31.332 77.6 31.738 ;
        RECT 72.85 31.582 77.35 31.988 ;
        RECT 72.6 31.832 77.1 32.238 ;
        RECT 72.35 32.082 76.85 32.488 ;
        RECT 72.1 32.332 76.6 32.738 ;
        RECT 71.85 32.582 76.35 32.988 ;
        RECT 71.6 32.832 76.1 33.238 ;
        RECT 71.35 33.082 75.85 33.488 ;
        RECT 71.1 33.332 75.6 33.738 ;
        RECT 70.85 33.582 75.35 33.988 ;
        RECT 70.6 33.832 75.1 34.238 ;
        RECT 70.35 34.082 74.85 34.488 ;
        RECT 70.1 34.332 74.6 34.738 ;
        RECT 69.85 34.582 74.35 34.988 ;
        RECT 69.6 34.832 74.1 35.238 ;
        RECT 69.35 35.082 73.85 35.488 ;
        RECT 69.1 35.332 73.6 35.738 ;
        RECT 68.85 35.582 73.35 35.988 ;
        RECT 68.6 35.832 73.1 36.238 ;
        RECT 68.35 36.082 72.85 36.488 ;
        RECT 68.1 36.332 72.6 36.738 ;
        RECT 67.85 36.582 72.35 36.988 ;
        RECT 67.6 36.832 72.1 37.238 ;
        RECT 67.35 37.082 71.85 37.488 ;
        RECT 67.1 37.332 71.6 37.738 ;
        RECT 66.85 37.582 71.35 37.988 ;
        RECT 66.6 37.832 71.1 38.238 ;
        RECT 66.35 38.082 70.85 38.488 ;
        RECT 66.1 38.332 70.6 38.738 ;
        RECT 65.85 38.582 70.35 38.988 ;
        RECT 65.6 38.832 70.1 39.238 ;
        RECT 65.35 39.082 69.85 39.488 ;
        RECT 65.1 39.332 69.6 39.738 ;
        RECT 64.85 39.582 69.35 39.988 ;
        RECT 64.6 39.832 69.1 40.238 ;
        RECT 64.35 40.082 68.85 40.488 ;
        RECT 64.1 40.332 68.6 40.738 ;
        RECT 63.85 40.582 68.35 40.988 ;
        RECT 63.6 40.832 68.1 41.238 ;
        RECT 63.35 41.082 67.85 41.488 ;
        RECT 63.1 41.332 67.6 41.738 ;
        RECT 62.85 41.582 67.35 41.988 ;
        RECT 62.6 41.832 67.1 42.238 ;
        RECT 62.35 42.082 66.85 42.488 ;
        RECT 62.1 42.332 66.6 42.738 ;
        RECT 61.85 42.582 66.35 42.988 ;
        RECT 61.6 42.832 66.1 43.238 ;
        RECT 61.35 43.082 65.85 43.488 ;
        RECT 61.1 43.332 65.6 43.738 ;
        RECT 60.85 43.582 65.35 43.988 ;
        RECT 60.6 43.832 65.1 44.238 ;
        RECT 60.35 44.082 64.85 44.488 ;
        RECT 60.1 44.332 64.6 44.738 ;
        RECT 59.85 44.582 64.35 44.988 ;
        RECT 59.6 44.832 64.1 45.238 ;
        RECT 59.35 45.082 63.85 45.488 ;
        RECT 59.1 45.332 63.6 45.738 ;
        RECT 58.85 45.582 63.35 45.988 ;
        RECT 58.6 45.832 63.1 46.238 ;
        RECT 58.35 46.082 62.85 46.488 ;
        RECT 58.1 46.332 62.6 46.738 ;
        RECT 57.85 46.582 62.35 46.988 ;
        RECT 57.6 46.832 62.1 47.238 ;
        RECT 57.35 47.082 61.85 47.488 ;
        RECT 57.1 47.332 61.6 47.738 ;
        RECT 56.85 47.582 61.35 47.988 ;
        RECT 56.6 47.832 61.1 48.238 ;
        RECT 56.35 48.082 60.85 48.488 ;
        RECT 56.1 48.332 60.6 48.738 ;
        RECT 55.85 48.582 60.35 48.988 ;
        RECT 55.6 48.832 60.1 49.238 ;
        RECT 55.35 49.082 59.85 49.488 ;
        RECT 55.1 49.332 59.6 49.738 ;
        RECT 54.85 49.582 59.35 49.988 ;
        RECT 54.6 49.832 59.1 50.238 ;
        RECT 54.35 50.082 58.85 50.488 ;
        RECT 54.1 50.332 58.6 50.738 ;
        RECT 53.85 50.582 58.35 50.988 ;
        RECT 53.6 50.832 58.1 51.238 ;
        RECT 53.35 51.082 57.85 51.488 ;
        RECT 53.1 51.332 57.6 51.738 ;
        RECT 52.85 51.582 57.35 51.988 ;
        RECT 52.6 51.832 57.1 52.238 ;
        RECT 52.35 52.082 56.85 52.488 ;
        RECT 52.1 52.332 56.6 52.738 ;
        RECT 51.85 52.582 56.35 52.988 ;
        RECT 51.6 52.832 56.1 53.238 ;
        RECT 51.35 53.082 55.85 53.488 ;
        RECT 51.1 53.332 55.6 53.738 ;
        RECT 50.85 53.582 55.35 53.988 ;
        RECT 50.6 53.832 55.1 54.238 ;
        RECT 50.35 54.082 54.85 54.488 ;
        RECT 50.1 54.332 54.6 54.738 ;
        RECT 49.85 54.582 54.35 54.988 ;
        RECT 49.6 54.832 54.1 55.238 ;
        RECT 49.35 55.082 53.85 55.488 ;
        RECT 49.1 55.332 53.6 55.738 ;
        RECT 48.85 55.582 53.35 55.988 ;
        RECT 48.6 55.832 53.1 56.238 ;
        RECT 48.35 56.082 52.85 56.488 ;
        RECT 48.1 56.332 52.6 56.738 ;
        RECT 47.85 56.582 52.35 56.988 ;
        RECT 47.6 56.832 52.1 57.238 ;
        RECT 47.35 57.082 51.85 57.488 ;
        RECT 47.1 57.332 51.6 57.738 ;
        RECT 46.85 57.582 51.35 57.988 ;
        RECT 46.6 57.832 51.1 58.238 ;
        RECT 46.35 58.082 50.85 58.488 ;
        RECT 46.1 58.332 50.6 58.738 ;
        RECT 45.85 58.582 50.35 58.988 ;
        RECT 45.6 58.832 50.1 59.238 ;
        RECT 45.35 59.082 49.85 59.488 ;
        RECT 45.1 59.332 49.6 59.738 ;
        RECT 44.85 59.582 49.35 59.988 ;
        RECT 44.6 59.832 49.1 60.238 ;
        RECT 44.35 60.082 48.85 60.488 ;
        RECT 44.1 60.332 48.6 60.738 ;
        RECT 43.85 60.582 48.35 60.988 ;
        RECT 43.6 60.832 48.1 61.238 ;
        RECT 43.35 61.082 47.85 61.488 ;
        RECT 43.1 61.332 47.6 61.738 ;
        RECT 42.85 61.582 47.35 61.988 ;
        RECT 42.6 61.832 47.1 62.238 ;
        RECT 42.35 62.082 46.85 62.488 ;
        RECT 42.1 62.332 46.6 62.738 ;
        RECT 41.85 62.582 46.35 62.988 ;
        RECT 41.6 62.832 46.1 63.238 ;
        RECT 41.35 63.082 45.85 63.488 ;
        RECT 41.1 63.332 45.6 63.738 ;
        RECT 40.85 63.582 45.35 63.988 ;
        RECT 40.6 63.832 45.1 64.238 ;
        RECT 40.35 64.082 44.85 64.488 ;
        RECT 40.1 64.332 44.6 64.738 ;
        RECT 39.85 64.582 44.35 64.988 ;
        RECT 39.6 64.832 44.1 65.238 ;
        RECT 39.35 65.082 43.85 65.488 ;
        RECT 39.1 65.332 43.6 65.738 ;
        RECT 38.85 65.582 43.35 65.988 ;
        RECT 38.6 65.832 43.1 66.238 ;
        RECT 38.35 66.082 42.85 66.488 ;
        RECT 38.1 66.332 42.6 66.738 ;
        RECT 37.85 66.582 42.35 66.988 ;
        RECT 37.6 66.832 42.1 67.238 ;
        RECT 37.35 67.082 41.85 67.488 ;
        RECT 37.1 67.332 41.6 67.738 ;
        RECT 36.85 67.582 41.35 67.988 ;
        RECT 36.6 67.832 41.1 68.238 ;
        RECT 36.35 68.082 40.85 68.488 ;
        RECT 36.1 68.332 40.6 68.738 ;
        RECT 35.85 68.582 40.35 68.988 ;
        RECT 35.6 68.832 40.1 69.238 ;
        RECT 35.35 69.082 39.85 69.488 ;
        RECT 35.1 69.332 39.6 69.738 ;
        RECT 34.85 69.582 39.35 69.988 ;
        RECT 34.6 69.832 39.1 70.238 ;
        RECT 34.35 70.082 38.85 70.488 ;
        RECT 34.1 70.332 38.6 70.738 ;
        RECT 33.85 70.582 38.35 70.988 ;
        RECT 33.6 70.832 38.1 71.238 ;
        RECT 33.35 71.082 37.85 71.488 ;
        RECT 33.1 71.332 37.6 71.738 ;
        RECT 32.85 71.582 37.35 71.988 ;
        RECT 32.6 71.832 37.1 72.238 ;
        RECT 32.35 72.082 36.85 72.488 ;
        RECT 32.1 72.332 36.6 72.738 ;
        RECT 31.85 72.582 36.35 72.988 ;
        RECT 31.6 72.832 36.1 73.238 ;
        RECT 31.35 73.082 35.85 73.488 ;
        RECT 31.1 73.332 35.6 73.738 ;
        RECT 30.85 73.582 35.35 73.988 ;
        RECT 30.6 73.832 35.1 74.238 ;
        RECT 30.35 74.082 34.85 74.488 ;
        RECT 30.1 74.332 34.6 74.738 ;
        RECT 29.85 74.582 34.35 74.988 ;
        RECT 29.6 74.832 34.1 75.238 ;
        RECT 29.35 75.082 33.85 75.488 ;
        RECT 29.1 75.332 33.6 75.738 ;
        RECT 28.85 75.582 33.35 75.988 ;
        RECT 28.6 75.832 33.1 76.238 ;
        RECT 28.35 76.082 32.85 76.488 ;
        RECT 28.1 76.332 32.6 76.738 ;
        RECT 27.85 76.582 32.35 76.988 ;
        RECT 27.6 76.832 32.1 77.238 ;
        RECT 27.35 77.082 31.85 77.488 ;
        RECT 27.1 77.332 31.6 77.738 ;
        RECT 26.85 77.582 31.35 77.988 ;
        RECT 26.6 77.832 31.1 78.238 ;
        RECT 26.35 78.082 30.85 78.488 ;
        RECT 26.1 78.332 30.6 78.738 ;
        RECT 25.85 78.582 30.35 78.988 ;
        RECT 25.6 78.832 30.1 79.238 ;
        RECT 25.35 79.082 29.85 79.488 ;
        RECT 25.1 79.332 29.6 79.738 ;
        RECT 24.85 79.582 29.35 79.988 ;
        RECT 24.6 79.832 29.1 80.238 ;
        RECT 24.35 80.082 28.85 80.488 ;
        RECT 24.1 80.332 28.6 80.738 ;
        RECT 23.85 80.582 28.35 80.988 ;
        RECT 23.6 80.832 28.1 81.238 ;
        RECT 23.35 81.082 27.85 81.488 ;
        RECT 23.1 81.332 27.6 81.738 ;
        RECT 22.85 81.582 27.35 81.988 ;
        RECT 22.6 81.832 27.1 82.238 ;
        RECT 22.35 82.082 26.85 82.488 ;
        RECT 22.1 82.332 26.6 82.738 ;
        RECT 21.85 82.582 26.35 82.988 ;
        RECT 21.6 82.832 26.1 83.238 ;
        RECT 21.35 83.082 25.85 83.488 ;
        RECT 21.1 83.332 25.6 83.738 ;
        RECT 20.85 83.582 25.35 83.988 ;
        RECT 20.6 83.832 25.1 84.238 ;
        RECT 20.35 84.082 24.85 84.488 ;
        RECT 20.1 84.332 24.6 84.738 ;
        RECT 19.85 84.582 24.35 84.988 ;
        RECT 19.6 84.832 24.1 85.238 ;
        RECT 19.6 84.832 23.85 85.488 ;
        RECT 19.6 84.832 23.6 85.738 ;
        RECT 19.6 84.832 23.35 85.988 ;
        RECT 19.6 84.832 23.1 119.5 ;
        RECT 87.147 24.49 119.5 28 ;
        RECT 82.75 28.762 87.397 29.031 ;
        RECT 87 24.563 87.147 29.23 ;
        RECT 82.5 29.012 87 29.428 ;
        RECT 83 28.512 87.647 28.781 ;
        RECT 86.75 24.762 87 29.428 ;
        RECT 82.25 29.262 86.75 29.678 ;
        RECT 83.25 28.262 87.897 28.531 ;
        RECT 86.5 25.012 86.75 29.678 ;
        RECT 82 29.512 86.5 29.928 ;
        RECT 83.5 28.012 88.147 28.281 ;
        RECT 86.25 25.262 86.5 29.928 ;
        RECT 81.75 29.762 86.25 30.178 ;
        RECT 83.75 27.762 88.303 28.078 ;
        RECT 86 25.512 86.25 30.178 ;
        RECT 81.5 30.012 86 30.428 ;
        RECT 84 27.512 119.5 28 ;
        RECT 85.75 25.762 86 30.428 ;
        RECT 81.25 30.262 85.75 30.678 ;
        RECT 84.25 27.262 119.5 28 ;
        RECT 85.5 26.012 85.75 30.678 ;
        RECT 81 30.512 85.5 30.928 ;
        RECT 84.5 27.012 119.5 28 ;
        RECT 85.25 26.262 85.5 30.928 ;
        RECT 80.75 30.762 85.25 31.178 ;
        RECT 84.75 26.762 119.5 28 ;
        RECT 85 26.512 85.25 31.178 ;
        RECT 80.5 31.012 85 31.428 ;
        RECT 80.25 31.262 84.75 31.678 ;
        RECT 80 31.512 84.5 31.928 ;
        RECT 79.75 31.762 84.25 32.178 ;
        RECT 79.5 32.012 84 32.428 ;
        RECT 79.25 32.262 83.75 32.678 ;
        RECT 79 32.512 83.5 32.928 ;
        RECT 78.75 32.762 83.25 33.178 ;
        RECT 78.5 33.012 83 33.428 ;
        RECT 78.25 33.262 82.75 33.678 ;
        RECT 78 33.512 82.5 33.928 ;
        RECT 77.75 33.762 82.25 34.178 ;
        RECT 77.5 34.012 82 34.428 ;
        RECT 77.25 34.262 81.75 34.678 ;
        RECT 77 34.512 81.5 34.928 ;
        RECT 76.75 34.762 81.25 35.178 ;
        RECT 76.5 35.012 81 35.428 ;
        RECT 76.25 35.262 80.75 35.678 ;
        RECT 76 35.512 80.5 35.928 ;
        RECT 75.75 35.762 80.25 36.178 ;
        RECT 75.5 36.012 80 36.428 ;
        RECT 75.25 36.262 79.75 36.678 ;
        RECT 75 36.512 79.5 36.928 ;
        RECT 74.75 36.762 79.25 37.178 ;
        RECT 74.5 37.012 79 37.428 ;
        RECT 74.25 37.262 78.75 37.678 ;
        RECT 74 37.512 78.5 37.928 ;
        RECT 73.75 37.762 78.25 38.178 ;
        RECT 73.5 38.012 78 38.428 ;
        RECT 73.25 38.262 77.75 38.678 ;
        RECT 73 38.512 77.5 38.928 ;
        RECT 72.75 38.762 77.25 39.178 ;
        RECT 72.5 39.012 77 39.428 ;
        RECT 72.25 39.262 76.75 39.678 ;
        RECT 72 39.512 76.5 39.928 ;
        RECT 71.75 39.762 76.25 40.178 ;
        RECT 71.5 40.012 76 40.428 ;
        RECT 71.25 40.262 75.75 40.678 ;
        RECT 71 40.512 75.5 40.928 ;
        RECT 70.75 40.762 75.25 41.178 ;
        RECT 70.5 41.012 75 41.428 ;
        RECT 70.25 41.262 74.75 41.678 ;
        RECT 70 41.512 74.5 41.928 ;
        RECT 69.75 41.762 74.25 42.178 ;
        RECT 69.5 42.012 74 42.428 ;
        RECT 69.25 42.262 73.75 42.678 ;
        RECT 69 42.512 73.5 42.928 ;
        RECT 68.75 42.762 73.25 43.178 ;
        RECT 68.5 43.012 73 43.428 ;
        RECT 68.25 43.262 72.75 43.678 ;
        RECT 68 43.512 72.5 43.928 ;
        RECT 67.75 43.762 72.25 44.178 ;
        RECT 67.5 44.012 72 44.428 ;
        RECT 67.25 44.262 71.75 44.678 ;
        RECT 67 44.512 71.5 44.928 ;
        RECT 66.75 44.762 71.25 45.178 ;
        RECT 66.5 45.012 71 45.428 ;
        RECT 66.25 45.262 70.75 45.678 ;
        RECT 66 45.512 70.5 45.928 ;
        RECT 65.75 45.762 70.25 46.178 ;
        RECT 65.5 46.012 70 46.428 ;
        RECT 65.25 46.262 69.75 46.678 ;
        RECT 65 46.512 69.5 46.928 ;
        RECT 64.75 46.762 69.25 47.178 ;
        RECT 64.5 47.012 69 47.428 ;
        RECT 64.25 47.262 68.75 47.678 ;
        RECT 64 47.512 68.5 47.928 ;
        RECT 63.75 47.762 68.25 48.178 ;
        RECT 63.5 48.012 68 48.428 ;
        RECT 63.25 48.262 67.75 48.678 ;
        RECT 63 48.512 67.5 48.928 ;
        RECT 62.75 48.762 67.25 49.178 ;
        RECT 62.5 49.012 67 49.428 ;
        RECT 62.25 49.262 66.75 49.678 ;
        RECT 62 49.512 66.5 49.928 ;
        RECT 61.75 49.762 66.25 50.178 ;
        RECT 61.5 50.012 66 50.428 ;
        RECT 61.25 50.262 65.75 50.678 ;
        RECT 61 50.512 65.5 50.928 ;
        RECT 60.75 50.762 65.25 51.178 ;
        RECT 60.5 51.012 65 51.428 ;
        RECT 60.25 51.262 64.75 51.678 ;
        RECT 60 51.512 64.5 51.928 ;
        RECT 59.75 51.762 64.25 52.178 ;
        RECT 59.5 52.012 64 52.428 ;
        RECT 59.25 52.262 63.75 52.678 ;
        RECT 59 52.512 63.5 52.928 ;
        RECT 58.75 52.762 63.25 53.178 ;
        RECT 58.5 53.012 63 53.428 ;
        RECT 58.25 53.262 62.75 53.678 ;
        RECT 58 53.512 62.5 53.928 ;
        RECT 57.75 53.762 62.25 54.178 ;
        RECT 57.5 54.012 62 54.428 ;
        RECT 57.25 54.262 61.75 54.678 ;
        RECT 57 54.512 61.5 54.928 ;
        RECT 56.75 54.762 61.25 55.178 ;
        RECT 56.5 55.012 61 55.428 ;
        RECT 56.25 55.262 60.75 55.678 ;
        RECT 56 55.512 60.5 55.928 ;
        RECT 55.75 55.762 60.25 56.178 ;
        RECT 55.5 56.012 60 56.428 ;
        RECT 55.25 56.262 59.75 56.678 ;
        RECT 55 56.512 59.5 56.928 ;
        RECT 54.75 56.762 59.25 57.178 ;
        RECT 54.5 57.012 59 57.428 ;
        RECT 54.25 57.262 58.75 57.678 ;
        RECT 54 57.512 58.5 57.928 ;
        RECT 53.75 57.762 58.25 58.178 ;
        RECT 53.5 58.012 58 58.428 ;
        RECT 53.25 58.262 57.75 58.678 ;
        RECT 53 58.512 57.5 58.928 ;
        RECT 52.75 58.762 57.25 59.178 ;
        RECT 52.5 59.012 57 59.428 ;
        RECT 52.25 59.262 56.75 59.678 ;
        RECT 52 59.512 56.5 59.928 ;
        RECT 51.75 59.762 56.25 60.178 ;
        RECT 51.5 60.012 56 60.428 ;
        RECT 51.25 60.262 55.75 60.678 ;
        RECT 51 60.512 55.5 60.928 ;
        RECT 50.75 60.762 55.25 61.178 ;
        RECT 50.5 61.012 55 61.428 ;
        RECT 50.25 61.262 54.75 61.678 ;
        RECT 50 61.512 54.5 61.928 ;
        RECT 49.75 61.762 54.25 62.178 ;
        RECT 49.5 62.012 54 62.428 ;
        RECT 49.25 62.262 53.75 62.678 ;
        RECT 49 62.512 53.5 62.928 ;
        RECT 48.75 62.762 53.25 63.178 ;
        RECT 48.5 63.012 53 63.428 ;
        RECT 48.25 63.262 52.75 63.678 ;
        RECT 48 63.512 52.5 63.928 ;
        RECT 47.75 63.762 52.25 64.178 ;
        RECT 47.5 64.012 52 64.428 ;
        RECT 47.25 64.262 51.75 64.678 ;
        RECT 47 64.512 51.5 64.928 ;
        RECT 46.75 64.762 51.25 65.178 ;
        RECT 46.5 65.012 51 65.428 ;
        RECT 46.25 65.262 50.75 65.678 ;
        RECT 46 65.512 50.5 65.928 ;
        RECT 45.75 65.762 50.25 66.178 ;
        RECT 45.5 66.012 50 66.428 ;
        RECT 45.25 66.262 49.75 66.678 ;
        RECT 45 66.512 49.5 66.928 ;
        RECT 44.75 66.762 49.25 67.178 ;
        RECT 44.5 67.012 49 67.428 ;
        RECT 44.25 67.262 48.75 67.678 ;
        RECT 44 67.512 48.5 67.928 ;
        RECT 43.75 67.762 48.25 68.178 ;
        RECT 43.5 68.012 48 68.428 ;
        RECT 43.25 68.262 47.75 68.678 ;
        RECT 43 68.512 47.5 68.928 ;
        RECT 42.75 68.762 47.25 69.178 ;
        RECT 42.5 69.012 47 69.428 ;
        RECT 42.25 69.262 46.75 69.678 ;
        RECT 42 69.512 46.5 69.928 ;
        RECT 41.75 69.762 46.25 70.178 ;
        RECT 41.5 70.012 46 70.428 ;
        RECT 41.25 70.262 45.75 70.678 ;
        RECT 41 70.512 45.5 70.928 ;
        RECT 40.75 70.762 45.25 71.178 ;
        RECT 40.5 71.012 45 71.428 ;
        RECT 40.25 71.262 44.75 71.678 ;
        RECT 40 71.512 44.5 71.928 ;
        RECT 39.75 71.762 44.25 72.178 ;
        RECT 39.5 72.012 44 72.428 ;
        RECT 39.25 72.262 43.75 72.678 ;
        RECT 39 72.512 43.5 72.928 ;
        RECT 38.75 72.762 43.25 73.178 ;
        RECT 38.5 73.012 43 73.428 ;
        RECT 38.25 73.262 42.75 73.678 ;
        RECT 38 73.512 42.5 73.928 ;
        RECT 37.75 73.762 42.25 74.178 ;
        RECT 37.5 74.012 42 74.428 ;
        RECT 37.25 74.262 41.75 74.678 ;
        RECT 37 74.512 41.5 74.928 ;
        RECT 36.75 74.762 41.25 75.178 ;
        RECT 36.5 75.012 41 75.428 ;
        RECT 36.25 75.262 40.75 75.678 ;
        RECT 36 75.512 40.5 75.928 ;
        RECT 35.75 75.762 40.25 76.178 ;
        RECT 35.5 76.012 40 76.428 ;
        RECT 35.25 76.262 39.75 76.678 ;
        RECT 35 76.512 39.5 76.928 ;
        RECT 34.75 76.762 39.25 77.178 ;
        RECT 34.5 77.012 39 77.428 ;
        RECT 34.25 77.262 38.75 77.678 ;
        RECT 34 77.512 38.5 77.928 ;
        RECT 33.75 77.762 38.25 78.178 ;
        RECT 33.5 78.012 38 78.428 ;
        RECT 33.25 78.262 37.75 78.678 ;
        RECT 33 78.512 37.5 78.928 ;
        RECT 32.75 78.762 37.25 79.178 ;
        RECT 32.5 79.012 37 79.428 ;
        RECT 32.25 79.262 36.75 79.678 ;
        RECT 32 79.512 36.5 79.928 ;
        RECT 31.75 79.762 36.25 80.178 ;
        RECT 31.5 80.012 36 80.428 ;
        RECT 31.25 80.262 35.75 80.678 ;
        RECT 31 80.512 35.5 80.928 ;
        RECT 30.75 80.762 35.25 81.178 ;
        RECT 30.5 81.012 35 81.428 ;
        RECT 30.25 81.262 34.75 81.678 ;
        RECT 30 81.512 34.5 81.928 ;
        RECT 29.75 81.762 34.25 82.178 ;
        RECT 29.5 82.012 34 82.428 ;
        RECT 29.25 82.262 33.75 82.678 ;
        RECT 29 82.512 33.5 82.928 ;
        RECT 28.75 82.762 33.25 83.178 ;
        RECT 28.5 83.012 33 83.428 ;
        RECT 28.25 83.262 32.75 83.678 ;
        RECT 28 83.512 32.5 83.928 ;
        RECT 27.75 83.762 32.25 84.178 ;
        RECT 27.5 84.012 32 84.428 ;
        RECT 27.25 84.262 31.75 84.678 ;
        RECT 27 84.512 31.5 84.928 ;
        RECT 26.75 84.762 31.25 85.178 ;
        RECT 26.5 85.012 31 85.428 ;
        RECT 26.25 85.262 30.75 85.678 ;
        RECT 26 85.512 30.5 85.928 ;
        RECT 25.75 85.762 30.25 86.178 ;
        RECT 25.5 86.012 30 86.428 ;
        RECT 25.25 86.262 29.75 86.678 ;
        RECT 25 86.512 29.5 86.928 ;
        RECT 24.75 86.762 29.25 87.178 ;
        RECT 24.5 87.012 29 87.428 ;
        RECT 24.5 87.012 28.75 87.678 ;
        RECT 24.5 87.012 28.5 87.928 ;
        RECT 24.5 87.012 28.25 88.178 ;
        RECT 24.5 87.012 28 119.5 ;
        RECT 89.307 29.4 119.5 32.9 ;
        RECT 85.65 32.932 90.307 33.181 ;
        RECT 84.9 33.682 89.307 34.135 ;
        RECT 85.15 33.432 89.557 33.931 ;
        RECT 89.15 29.478 89.307 34.135 ;
        RECT 84.65 33.932 89.15 34.338 ;
        RECT 85.4 33.182 89.807 33.681 ;
        RECT 88.9 29.682 89.15 34.338 ;
        RECT 84.4 34.182 88.9 34.588 ;
        RECT 85.65 32.932 90.057 33.431 ;
        RECT 88.65 29.932 88.9 34.588 ;
        RECT 84.15 34.432 88.65 34.838 ;
        RECT 85.9 32.682 90.463 32.978 ;
        RECT 88.4 30.182 88.65 34.838 ;
        RECT 83.9 34.682 88.4 35.088 ;
        RECT 86.15 32.432 119.5 32.9 ;
        RECT 88.15 30.432 88.4 35.088 ;
        RECT 83.65 34.932 88.15 35.338 ;
        RECT 86.4 32.182 119.5 32.9 ;
        RECT 87.9 30.682 88.15 35.338 ;
        RECT 83.4 35.182 87.9 35.588 ;
        RECT 86.65 31.932 119.5 32.9 ;
        RECT 87.65 30.932 87.9 35.588 ;
        RECT 83.15 35.432 87.65 35.838 ;
        RECT 86.9 31.682 119.5 32.9 ;
        RECT 87.4 31.182 87.65 35.838 ;
        RECT 82.9 35.682 87.4 36.088 ;
        RECT 87.15 31.432 119.5 32.9 ;
        RECT 82.65 35.932 87.15 36.338 ;
        RECT 82.4 36.182 86.9 36.588 ;
        RECT 82.15 36.432 86.65 36.838 ;
        RECT 81.9 36.682 86.4 37.088 ;
        RECT 81.65 36.932 86.15 37.338 ;
        RECT 81.4 37.182 85.9 37.588 ;
        RECT 81.15 37.432 85.65 37.838 ;
        RECT 80.9 37.682 85.4 38.088 ;
        RECT 80.65 37.932 85.15 38.338 ;
        RECT 80.4 38.182 84.9 38.588 ;
        RECT 80.15 38.432 84.65 38.838 ;
        RECT 79.9 38.682 84.4 39.088 ;
        RECT 79.65 38.932 84.15 39.338 ;
        RECT 79.4 39.182 83.9 39.588 ;
        RECT 79.15 39.432 83.65 39.838 ;
        RECT 78.9 39.682 83.4 40.088 ;
        RECT 78.65 39.932 83.15 40.338 ;
        RECT 78.4 40.182 82.9 40.588 ;
        RECT 78.15 40.432 82.65 40.838 ;
        RECT 77.9 40.682 82.4 41.088 ;
        RECT 77.65 40.932 82.15 41.338 ;
        RECT 77.4 41.182 81.9 41.588 ;
        RECT 77.15 41.432 81.65 41.838 ;
        RECT 76.9 41.682 81.4 42.088 ;
        RECT 76.65 41.932 81.15 42.338 ;
        RECT 76.4 42.182 80.9 42.588 ;
        RECT 76.15 42.432 80.65 42.838 ;
        RECT 75.9 42.682 80.4 43.088 ;
        RECT 75.65 42.932 80.15 43.338 ;
        RECT 75.4 43.182 79.9 43.588 ;
        RECT 75.15 43.432 79.65 43.838 ;
        RECT 74.9 43.682 79.4 44.088 ;
        RECT 74.65 43.932 79.15 44.338 ;
        RECT 74.4 44.182 78.9 44.588 ;
        RECT 74.15 44.432 78.65 44.838 ;
        RECT 73.9 44.682 78.4 45.088 ;
        RECT 73.65 44.932 78.15 45.338 ;
        RECT 73.4 45.182 77.9 45.588 ;
        RECT 73.15 45.432 77.65 45.838 ;
        RECT 72.9 45.682 77.4 46.088 ;
        RECT 72.65 45.932 77.15 46.338 ;
        RECT 72.4 46.182 76.9 46.588 ;
        RECT 72.15 46.432 76.65 46.838 ;
        RECT 71.9 46.682 76.4 47.088 ;
        RECT 71.65 46.932 76.15 47.338 ;
        RECT 71.4 47.182 75.9 47.588 ;
        RECT 71.15 47.432 75.65 47.838 ;
        RECT 70.9 47.682 75.4 48.088 ;
        RECT 70.65 47.932 75.15 48.338 ;
        RECT 70.4 48.182 74.9 48.588 ;
        RECT 70.15 48.432 74.65 48.838 ;
        RECT 69.9 48.682 74.4 49.088 ;
        RECT 69.65 48.932 74.15 49.338 ;
        RECT 69.4 49.182 73.9 49.588 ;
        RECT 69.15 49.432 73.65 49.838 ;
        RECT 68.9 49.682 73.4 50.088 ;
        RECT 68.65 49.932 73.15 50.338 ;
        RECT 68.4 50.182 72.9 50.588 ;
        RECT 68.15 50.432 72.65 50.838 ;
        RECT 67.9 50.682 72.4 51.088 ;
        RECT 67.65 50.932 72.15 51.338 ;
        RECT 67.4 51.182 71.9 51.588 ;
        RECT 67.15 51.432 71.65 51.838 ;
        RECT 66.9 51.682 71.4 52.088 ;
        RECT 66.65 51.932 71.15 52.338 ;
        RECT 66.4 52.182 70.9 52.588 ;
        RECT 66.15 52.432 70.65 52.838 ;
        RECT 65.9 52.682 70.4 53.088 ;
        RECT 65.65 52.932 70.15 53.338 ;
        RECT 65.4 53.182 69.9 53.588 ;
        RECT 65.15 53.432 69.65 53.838 ;
        RECT 64.9 53.682 69.4 54.088 ;
        RECT 64.65 53.932 69.15 54.338 ;
        RECT 64.4 54.182 68.9 54.588 ;
        RECT 64.15 54.432 68.65 54.838 ;
        RECT 63.9 54.682 68.4 55.088 ;
        RECT 63.65 54.932 68.15 55.338 ;
        RECT 63.4 55.182 67.9 55.588 ;
        RECT 63.15 55.432 67.65 55.838 ;
        RECT 62.9 55.682 67.4 56.088 ;
        RECT 62.65 55.932 67.15 56.338 ;
        RECT 62.4 56.182 66.9 56.588 ;
        RECT 62.15 56.432 66.65 56.838 ;
        RECT 61.9 56.682 66.4 57.088 ;
        RECT 61.65 56.932 66.15 57.338 ;
        RECT 61.4 57.182 65.9 57.588 ;
        RECT 61.15 57.432 65.65 57.838 ;
        RECT 60.9 57.682 65.4 58.088 ;
        RECT 60.65 57.932 65.15 58.338 ;
        RECT 60.4 58.182 64.9 58.588 ;
        RECT 60.15 58.432 64.65 58.838 ;
        RECT 59.9 58.682 64.4 59.088 ;
        RECT 59.65 58.932 64.15 59.338 ;
        RECT 59.4 59.182 63.9 59.588 ;
        RECT 59.15 59.432 63.65 59.838 ;
        RECT 58.9 59.682 63.4 60.088 ;
        RECT 58.65 59.932 63.15 60.338 ;
        RECT 58.4 60.182 62.9 60.588 ;
        RECT 58.15 60.432 62.65 60.838 ;
        RECT 57.9 60.682 62.4 61.088 ;
        RECT 57.65 60.932 62.15 61.338 ;
        RECT 57.4 61.182 61.9 61.588 ;
        RECT 57.15 61.432 61.65 61.838 ;
        RECT 56.9 61.682 61.4 62.088 ;
        RECT 56.65 61.932 61.15 62.338 ;
        RECT 56.4 62.182 60.9 62.588 ;
        RECT 56.15 62.432 60.65 62.838 ;
        RECT 55.9 62.682 60.4 63.088 ;
        RECT 55.65 62.932 60.15 63.338 ;
        RECT 55.4 63.182 59.9 63.588 ;
        RECT 55.15 63.432 59.65 63.838 ;
        RECT 54.9 63.682 59.4 64.088 ;
        RECT 54.65 63.932 59.15 64.338 ;
        RECT 54.4 64.182 58.9 64.588 ;
        RECT 54.15 64.432 58.65 64.838 ;
        RECT 53.9 64.682 58.4 65.088 ;
        RECT 53.65 64.932 58.15 65.338 ;
        RECT 53.4 65.182 57.9 65.588 ;
        RECT 53.15 65.432 57.65 65.838 ;
        RECT 52.9 65.682 57.4 66.088 ;
        RECT 52.65 65.932 57.15 66.338 ;
        RECT 52.4 66.182 56.9 66.588 ;
        RECT 52.15 66.432 56.65 66.838 ;
        RECT 51.9 66.682 56.4 67.088 ;
        RECT 51.65 66.932 56.15 67.338 ;
        RECT 51.4 67.182 55.9 67.588 ;
        RECT 51.15 67.432 55.65 67.838 ;
        RECT 50.9 67.682 55.4 68.088 ;
        RECT 50.65 67.932 55.15 68.338 ;
        RECT 50.4 68.182 54.9 68.588 ;
        RECT 50.15 68.432 54.65 68.838 ;
        RECT 49.9 68.682 54.4 69.088 ;
        RECT 49.65 68.932 54.15 69.338 ;
        RECT 49.4 69.182 53.9 69.588 ;
        RECT 49.15 69.432 53.65 69.838 ;
        RECT 48.9 69.682 53.4 70.088 ;
        RECT 48.65 69.932 53.15 70.338 ;
        RECT 48.4 70.182 52.9 70.588 ;
        RECT 48.15 70.432 52.65 70.838 ;
        RECT 47.9 70.682 52.4 71.088 ;
        RECT 47.65 70.932 52.15 71.338 ;
        RECT 47.4 71.182 51.9 71.588 ;
        RECT 47.15 71.432 51.65 71.838 ;
        RECT 46.9 71.682 51.4 72.088 ;
        RECT 46.65 71.932 51.15 72.338 ;
        RECT 46.4 72.182 50.9 72.588 ;
        RECT 46.15 72.432 50.65 72.838 ;
        RECT 45.9 72.682 50.4 73.088 ;
        RECT 45.65 72.932 50.15 73.338 ;
        RECT 45.4 73.182 49.9 73.588 ;
        RECT 45.15 73.432 49.65 73.838 ;
        RECT 44.9 73.682 49.4 74.088 ;
        RECT 44.65 73.932 49.15 74.338 ;
        RECT 44.4 74.182 48.9 74.588 ;
        RECT 44.15 74.432 48.65 74.838 ;
        RECT 43.9 74.682 48.4 75.088 ;
        RECT 43.65 74.932 48.15 75.338 ;
        RECT 43.4 75.182 47.9 75.588 ;
        RECT 43.15 75.432 47.65 75.838 ;
        RECT 42.9 75.682 47.4 76.088 ;
        RECT 42.65 75.932 47.15 76.338 ;
        RECT 42.4 76.182 46.9 76.588 ;
        RECT 42.15 76.432 46.65 76.838 ;
        RECT 41.9 76.682 46.4 77.088 ;
        RECT 41.65 76.932 46.15 77.338 ;
        RECT 41.4 77.182 45.9 77.588 ;
        RECT 41.15 77.432 45.65 77.838 ;
        RECT 40.9 77.682 45.4 78.088 ;
        RECT 40.65 77.932 45.15 78.338 ;
        RECT 40.4 78.182 44.9 78.588 ;
        RECT 40.15 78.432 44.65 78.838 ;
        RECT 39.9 78.682 44.4 79.088 ;
        RECT 39.65 78.932 44.15 79.338 ;
        RECT 39.4 79.182 43.9 79.588 ;
        RECT 39.15 79.432 43.65 79.838 ;
        RECT 38.9 79.682 43.4 80.088 ;
        RECT 38.65 79.932 43.15 80.338 ;
        RECT 38.4 80.182 42.9 80.588 ;
        RECT 38.15 80.432 42.65 80.838 ;
        RECT 37.9 80.682 42.4 81.088 ;
        RECT 37.65 80.932 42.15 81.338 ;
        RECT 37.4 81.182 41.9 81.588 ;
        RECT 37.15 81.432 41.65 81.838 ;
        RECT 36.9 81.682 41.4 82.088 ;
        RECT 36.65 81.932 41.15 82.338 ;
        RECT 36.4 82.182 40.9 82.588 ;
        RECT 36.15 82.432 40.65 82.838 ;
        RECT 35.9 82.682 40.4 83.088 ;
        RECT 35.65 82.932 40.15 83.338 ;
        RECT 35.4 83.182 39.9 83.588 ;
        RECT 35.15 83.432 39.65 83.838 ;
        RECT 34.9 83.682 39.4 84.088 ;
        RECT 34.65 83.932 39.15 84.338 ;
        RECT 34.4 84.182 38.9 84.588 ;
        RECT 34.15 84.432 38.65 84.838 ;
        RECT 33.9 84.682 38.4 85.088 ;
        RECT 33.65 84.932 38.15 85.338 ;
        RECT 33.4 85.182 37.9 85.588 ;
        RECT 33.15 85.432 37.65 85.838 ;
        RECT 32.9 85.682 37.4 86.088 ;
        RECT 32.65 85.932 37.15 86.338 ;
        RECT 32.4 86.182 36.9 86.588 ;
        RECT 32.15 86.432 36.65 86.838 ;
        RECT 31.9 86.682 36.4 87.088 ;
        RECT 31.65 86.932 36.15 87.338 ;
        RECT 31.4 87.182 35.9 87.588 ;
        RECT 31.15 87.432 35.65 87.838 ;
        RECT 30.9 87.682 35.4 88.088 ;
        RECT 30.65 87.932 35.15 88.338 ;
        RECT 30.4 88.182 34.9 88.588 ;
        RECT 30.15 88.432 34.65 88.838 ;
        RECT 29.9 88.682 34.4 89.088 ;
        RECT 29.65 88.932 34.15 89.338 ;
        RECT 29.4 89.182 33.9 89.588 ;
        RECT 29.4 89.182 33.65 89.838 ;
        RECT 29.4 89.182 33.4 90.088 ;
        RECT 29.4 89.182 33.15 90.338 ;
        RECT 29.4 89.182 32.9 119.5 ;
        RECT 75.697 0 119.5 3.5 ;
        RECT 72 3.572 76.697 3.781 ;
        RECT 71.25 4.322 75.697 4.755 ;
        RECT 71.5 4.072 75.947 4.531 ;
        RECT 75.5 0.098 75.697 4.755 ;
        RECT 71 4.572 75.5 4.978 ;
        RECT 71.75 3.822 76.197 4.281 ;
        RECT 75.25 0.322 75.5 4.978 ;
        RECT 70.75 4.822 75.25 5.228 ;
        RECT 72 3.572 76.447 4.031 ;
        RECT 75 0.572 75.25 5.228 ;
        RECT 70.5 5.072 75 5.478 ;
        RECT 72.25 3.322 76.853 3.578 ;
        RECT 74.75 0.822 75 5.478 ;
        RECT 70.25 5.322 74.75 5.728 ;
        RECT 72.5 3.072 119.5 3.5 ;
        RECT 74.5 1.072 74.75 5.728 ;
        RECT 70 5.572 74.5 5.978 ;
        RECT 72.75 2.822 119.5 3.5 ;
        RECT 74.25 1.322 74.5 5.978 ;
        RECT 69.75 5.822 74.25 6.228 ;
        RECT 73 2.572 119.5 3.5 ;
        RECT 74 1.572 74.25 6.228 ;
        RECT 69.5 6.072 74 6.478 ;
        RECT 73.25 2.322 119.5 3.5 ;
        RECT 73.75 1.822 74 6.478 ;
        RECT 69.25 6.322 73.75 6.728 ;
        RECT 73.5 2.072 119.5 3.5 ;
        RECT 69 6.572 73.5 6.978 ;
        RECT 68.75 6.822 73.25 7.228 ;
        RECT 68.5 7.072 73 7.478 ;
        RECT 68.25 7.322 72.75 7.728 ;
        RECT 68 7.572 72.5 7.978 ;
        RECT 67.75 7.822 72.25 8.228 ;
        RECT 67.5 8.072 72 8.478 ;
        RECT 67.25 8.322 71.75 8.728 ;
        RECT 67 8.572 71.5 8.978 ;
        RECT 66.75 8.822 71.25 9.228 ;
        RECT 66.5 9.072 71 9.478 ;
        RECT 66.25 9.322 70.75 9.728 ;
        RECT 66 9.572 70.5 9.978 ;
        RECT 65.75 9.822 70.25 10.228 ;
        RECT 65.5 10.072 70 10.478 ;
        RECT 65.25 10.322 69.75 10.728 ;
        RECT 65 10.572 69.5 10.978 ;
        RECT 64.75 10.822 69.25 11.228 ;
        RECT 64.5 11.072 69 11.478 ;
        RECT 64.25 11.322 68.75 11.728 ;
        RECT 64 11.572 68.5 11.978 ;
        RECT 63.75 11.822 68.25 12.228 ;
        RECT 63.5 12.072 68 12.478 ;
        RECT 63.25 12.322 67.75 12.728 ;
        RECT 63 12.572 67.5 12.978 ;
        RECT 62.75 12.822 67.25 13.228 ;
        RECT 62.5 13.072 67 13.478 ;
        RECT 62.25 13.322 66.75 13.728 ;
        RECT 62 13.572 66.5 13.978 ;
        RECT 61.75 13.822 66.25 14.228 ;
        RECT 61.5 14.072 66 14.478 ;
        RECT 61.25 14.322 65.75 14.728 ;
        RECT 61 14.572 65.5 14.978 ;
        RECT 60.75 14.822 65.25 15.228 ;
        RECT 60.5 15.072 65 15.478 ;
        RECT 60.25 15.322 64.75 15.728 ;
        RECT 60 15.572 64.5 15.978 ;
        RECT 59.75 15.822 64.25 16.228 ;
        RECT 59.5 16.072 64 16.478 ;
        RECT 59.25 16.322 63.75 16.728 ;
        RECT 59 16.572 63.5 16.978 ;
        RECT 58.75 16.822 63.25 17.228 ;
        RECT 58.5 17.072 63 17.478 ;
        RECT 58.25 17.322 62.75 17.728 ;
        RECT 58 17.572 62.5 17.978 ;
        RECT 57.75 17.822 62.25 18.228 ;
        RECT 57.5 18.072 62 18.478 ;
        RECT 57.25 18.322 61.75 18.728 ;
        RECT 57 18.572 61.5 18.978 ;
        RECT 56.75 18.822 61.25 19.228 ;
        RECT 56.5 19.072 61 19.478 ;
        RECT 56.25 19.322 60.75 19.728 ;
        RECT 56 19.572 60.5 19.978 ;
        RECT 55.75 19.822 60.25 20.228 ;
        RECT 55.5 20.072 60 20.478 ;
        RECT 55.25 20.322 59.75 20.728 ;
        RECT 55 20.572 59.5 20.978 ;
        RECT 54.75 20.822 59.25 21.228 ;
        RECT 54.5 21.072 59 21.478 ;
        RECT 54.25 21.322 58.75 21.728 ;
        RECT 54 21.572 58.5 21.978 ;
        RECT 53.75 21.822 58.25 22.228 ;
        RECT 53.5 22.072 58 22.478 ;
        RECT 53.25 22.322 57.75 22.728 ;
        RECT 53 22.572 57.5 22.978 ;
        RECT 52.75 22.822 57.25 23.228 ;
        RECT 52.5 23.072 57 23.478 ;
        RECT 52.25 23.322 56.75 23.728 ;
        RECT 52 23.572 56.5 23.978 ;
        RECT 51.75 23.822 56.25 24.228 ;
        RECT 51.5 24.072 56 24.478 ;
        RECT 51.25 24.322 55.75 24.728 ;
        RECT 51 24.572 55.5 24.978 ;
        RECT 50.75 24.822 55.25 25.228 ;
        RECT 50.5 25.072 55 25.478 ;
        RECT 50.25 25.322 54.75 25.728 ;
        RECT 50 25.572 54.5 25.978 ;
        RECT 49.75 25.822 54.25 26.228 ;
        RECT 49.5 26.072 54 26.478 ;
        RECT 49.25 26.322 53.75 26.728 ;
        RECT 49 26.572 53.5 26.978 ;
        RECT 48.75 26.822 53.25 27.228 ;
        RECT 48.5 27.072 53 27.478 ;
        RECT 48.25 27.322 52.75 27.728 ;
        RECT 48 27.572 52.5 27.978 ;
        RECT 47.75 27.822 52.25 28.228 ;
        RECT 47.5 28.072 52 28.478 ;
        RECT 47.25 28.322 51.75 28.728 ;
        RECT 47 28.572 51.5 28.978 ;
        RECT 46.75 28.822 51.25 29.228 ;
        RECT 46.5 29.072 51 29.478 ;
        RECT 46.25 29.322 50.75 29.728 ;
        RECT 46 29.572 50.5 29.978 ;
        RECT 45.75 29.822 50.25 30.228 ;
        RECT 45.5 30.072 50 30.478 ;
        RECT 45.25 30.322 49.75 30.728 ;
        RECT 45 30.572 49.5 30.978 ;
        RECT 44.75 30.822 49.25 31.228 ;
        RECT 44.5 31.072 49 31.478 ;
        RECT 44.25 31.322 48.75 31.728 ;
        RECT 44 31.572 48.5 31.978 ;
        RECT 43.75 31.822 48.25 32.228 ;
        RECT 43.5 32.072 48 32.478 ;
        RECT 43.25 32.322 47.75 32.728 ;
        RECT 43 32.572 47.5 32.978 ;
        RECT 42.75 32.822 47.25 33.228 ;
        RECT 42.5 33.072 47 33.478 ;
        RECT 42.25 33.322 46.75 33.728 ;
        RECT 42 33.572 46.5 33.978 ;
        RECT 41.75 33.822 46.25 34.228 ;
        RECT 41.5 34.072 46 34.478 ;
        RECT 41.25 34.322 45.75 34.728 ;
        RECT 41 34.572 45.5 34.978 ;
        RECT 40.75 34.822 45.25 35.228 ;
        RECT 40.5 35.072 45 35.478 ;
        RECT 40.25 35.322 44.75 35.728 ;
        RECT 40 35.572 44.5 35.978 ;
        RECT 39.75 35.822 44.25 36.228 ;
        RECT 39.5 36.072 44 36.478 ;
        RECT 39.25 36.322 43.75 36.728 ;
        RECT 39 36.572 43.5 36.978 ;
        RECT 38.75 36.822 43.25 37.228 ;
        RECT 38.5 37.072 43 37.478 ;
        RECT 38.25 37.322 42.75 37.728 ;
        RECT 38 37.572 42.5 37.978 ;
        RECT 37.75 37.822 42.25 38.228 ;
        RECT 37.5 38.072 42 38.478 ;
        RECT 37.25 38.322 41.75 38.728 ;
        RECT 37 38.572 41.5 38.978 ;
        RECT 36.75 38.822 41.25 39.228 ;
        RECT 36.5 39.072 41 39.478 ;
        RECT 36.25 39.322 40.75 39.728 ;
        RECT 36 39.572 40.5 39.978 ;
        RECT 35.75 39.822 40.25 40.228 ;
        RECT 35.5 40.072 40 40.478 ;
        RECT 35.25 40.322 39.75 40.728 ;
        RECT 35 40.572 39.5 40.978 ;
        RECT 34.75 40.822 39.25 41.228 ;
        RECT 34.5 41.072 39 41.478 ;
        RECT 34.25 41.322 38.75 41.728 ;
        RECT 34 41.572 38.5 41.978 ;
        RECT 33.75 41.822 38.25 42.228 ;
        RECT 33.5 42.072 38 42.478 ;
        RECT 33.25 42.322 37.75 42.728 ;
        RECT 33 42.572 37.5 42.978 ;
        RECT 32.75 42.822 37.25 43.228 ;
        RECT 32.5 43.072 37 43.478 ;
        RECT 32.25 43.322 36.75 43.728 ;
        RECT 32 43.572 36.5 43.978 ;
        RECT 31.75 43.822 36.25 44.228 ;
        RECT 31.5 44.072 36 44.478 ;
        RECT 31.25 44.322 35.75 44.728 ;
        RECT 31 44.572 35.5 44.978 ;
        RECT 30.75 44.822 35.25 45.228 ;
        RECT 30.5 45.072 35 45.478 ;
        RECT 30.25 45.322 34.75 45.728 ;
        RECT 30 45.572 34.5 45.978 ;
        RECT 29.75 45.822 34.25 46.228 ;
        RECT 29.5 46.072 34 46.478 ;
        RECT 29.25 46.322 33.75 46.728 ;
        RECT 29 46.572 33.5 46.978 ;
        RECT 28.75 46.822 33.25 47.228 ;
        RECT 28.5 47.072 33 47.478 ;
        RECT 28.25 47.322 32.75 47.728 ;
        RECT 28 47.572 32.5 47.978 ;
        RECT 27.75 47.822 32.25 48.228 ;
        RECT 27.5 48.072 32 48.478 ;
        RECT 27.25 48.322 31.75 48.728 ;
        RECT 27 48.572 31.5 48.978 ;
        RECT 26.75 48.822 31.25 49.228 ;
        RECT 26.5 49.072 31 49.478 ;
        RECT 26.25 49.322 30.75 49.728 ;
        RECT 26 49.572 30.5 49.978 ;
        RECT 25.75 49.822 30.25 50.228 ;
        RECT 25.5 50.072 30 50.478 ;
        RECT 25.25 50.322 29.75 50.728 ;
        RECT 25 50.572 29.5 50.978 ;
        RECT 24.75 50.822 29.25 51.228 ;
        RECT 24.5 51.072 29 51.478 ;
        RECT 24.25 51.322 28.75 51.728 ;
        RECT 24 51.572 28.5 51.978 ;
        RECT 23.75 51.822 28.25 52.228 ;
        RECT 23.5 52.072 28 52.478 ;
        RECT 23.25 52.322 27.75 52.728 ;
        RECT 23 52.572 27.5 52.978 ;
        RECT 22.75 52.822 27.25 53.228 ;
        RECT 22.5 53.072 27 53.478 ;
        RECT 22.25 53.322 26.75 53.728 ;
        RECT 22 53.572 26.5 53.978 ;
        RECT 21.75 53.822 26.25 54.228 ;
        RECT 21.5 54.072 26 54.478 ;
        RECT 21.25 54.322 25.75 54.728 ;
        RECT 21 54.572 25.5 54.978 ;
        RECT 20.75 54.822 25.25 55.228 ;
        RECT 20.5 55.072 25 55.478 ;
        RECT 20.25 55.322 24.75 55.728 ;
        RECT 20 55.572 24.5 55.978 ;
        RECT 19.75 55.822 24.25 56.228 ;
        RECT 19.5 56.072 24 56.478 ;
        RECT 19.25 56.322 23.75 56.728 ;
        RECT 19 56.572 23.5 56.978 ;
        RECT 18.75 56.822 23.25 57.228 ;
        RECT 18.5 57.072 23 57.478 ;
        RECT 18.25 57.322 22.75 57.728 ;
        RECT 18 57.572 22.5 57.978 ;
        RECT 17.75 57.822 22.25 58.228 ;
        RECT 17.5 58.072 22 58.478 ;
        RECT 17.25 58.322 21.75 58.728 ;
        RECT 17 58.572 21.5 58.978 ;
        RECT 16.75 58.822 21.25 59.228 ;
        RECT 16.5 59.072 21 59.478 ;
        RECT 16.25 59.322 20.75 59.728 ;
        RECT 16 59.572 20.5 59.978 ;
        RECT 15.75 59.822 20.25 60.228 ;
        RECT 15.5 60.072 20 60.478 ;
        RECT 15.25 60.322 19.75 60.728 ;
        RECT 15 60.572 19.5 60.978 ;
        RECT 14.75 60.822 19.25 61.228 ;
        RECT 14.5 61.072 19 61.478 ;
        RECT 14.25 61.322 18.75 61.728 ;
        RECT 14 61.572 18.5 61.978 ;
        RECT 13.75 61.822 18.25 62.228 ;
        RECT 13.5 62.072 18 62.478 ;
        RECT 13.25 62.322 17.75 62.728 ;
        RECT 13 62.572 17.5 62.978 ;
        RECT 12.75 62.822 17.25 63.228 ;
        RECT 12.5 63.072 17 63.478 ;
        RECT 12.25 63.322 16.75 63.728 ;
        RECT 12 63.572 16.5 63.978 ;
        RECT 11.75 63.822 16.25 64.228 ;
        RECT 11.5 64.072 16 64.478 ;
        RECT 11.25 64.322 15.75 64.728 ;
        RECT 11 64.572 15.5 64.978 ;
        RECT 10.75 64.822 15.25 65.228 ;
        RECT 10.5 65.072 15 65.478 ;
        RECT 10.25 65.322 14.75 65.728 ;
        RECT 10 65.572 14.5 65.978 ;
        RECT 9.75 65.822 14.25 66.228 ;
        RECT 9.5 66.072 14 66.478 ;
        RECT 9.25 66.322 13.75 66.728 ;
        RECT 9 66.572 13.5 66.978 ;
        RECT 8.75 66.822 13.25 67.228 ;
        RECT 8.5 67.072 13 67.478 ;
        RECT 8.25 67.322 12.75 67.728 ;
        RECT 8 67.572 12.5 67.978 ;
        RECT 7.75 67.822 12.25 68.228 ;
        RECT 7.5 68.072 12 68.478 ;
        RECT 7.25 68.322 11.75 68.728 ;
        RECT 7 68.572 11.5 68.978 ;
        RECT 6.75 68.822 11.25 69.228 ;
        RECT 6.5 69.072 11 69.478 ;
        RECT 6.25 69.322 10.75 69.728 ;
        RECT 6 69.572 10.5 69.978 ;
        RECT 5.75 69.822 10.25 70.228 ;
        RECT 5.5 70.072 10 70.478 ;
        RECT 5.25 70.322 9.75 70.728 ;
        RECT 5 70.572 9.5 70.978 ;
        RECT 4.75 70.822 9.25 71.228 ;
        RECT 4.5 71.072 9 71.478 ;
        RECT 4.25 71.322 8.75 71.728 ;
        RECT 4 71.572 8.5 71.978 ;
        RECT 3.75 71.822 8.25 72.228 ;
        RECT 3.5 72.072 8 72.478 ;
        RECT 3.25 72.322 7.75 72.728 ;
        RECT 3 72.572 7.5 72.978 ;
        RECT 2.75 72.822 7.25 73.228 ;
        RECT 2.5 73.072 7 73.478 ;
        RECT 2.25 73.322 6.75 73.728 ;
        RECT 2 73.572 6.5 73.978 ;
        RECT 1.75 73.822 6.25 74.228 ;
        RECT 1.5 74.072 6 74.478 ;
        RECT 1.25 74.322 5.75 74.728 ;
        RECT 1 74.572 5.5 74.978 ;
        RECT 0.75 74.822 5.25 75.228 ;
        RECT 0.5 75.072 5 75.478 ;
        RECT 0.25 75.322 4.75 75.728 ;
        RECT 0 75.572 4.5 75.978 ;
        RECT 0 75.572 4.25 76.228 ;
        RECT 0 75.572 4 76.478 ;
        RECT 0 75.572 3.75 76.728 ;
        RECT 0 75.572 3.5 119.5 ;
        RECT 77.877 4.9 119.5 8.4 ;
        RECT 74.4 8.252 79.033 8.478 ;
        RECT 73.4 9.252 77.877 9.67 ;
        RECT 73.65 9.002 78.127 9.431 ;
        RECT 77.65 5.013 77.877 9.67 ;
        RECT 73.15 9.502 77.65 9.908 ;
        RECT 73.9 8.752 78.377 9.181 ;
        RECT 77.4 5.252 77.65 9.908 ;
        RECT 72.9 9.752 77.4 10.158 ;
        RECT 74.15 8.502 78.627 8.931 ;
        RECT 77.15 5.502 77.4 10.158 ;
        RECT 72.65 10.002 77.15 10.408 ;
        RECT 74.4 8.252 78.877 8.681 ;
        RECT 76.9 5.752 77.15 10.408 ;
        RECT 72.4 10.252 76.9 10.658 ;
        RECT 74.65 8.002 119.5 8.4 ;
        RECT 76.65 6.002 76.9 10.658 ;
        RECT 72.15 10.502 76.65 10.908 ;
        RECT 74.9 7.752 119.5 8.4 ;
        RECT 76.4 6.252 76.65 10.908 ;
        RECT 71.9 10.752 76.4 11.158 ;
        RECT 75.15 7.502 119.5 8.4 ;
        RECT 76.15 6.502 76.4 11.158 ;
        RECT 71.65 11.002 76.15 11.408 ;
        RECT 75.4 7.252 119.5 8.4 ;
        RECT 75.9 6.752 76.15 11.408 ;
        RECT 71.4 11.252 75.9 11.658 ;
        RECT 75.65 7.002 119.5 8.4 ;
        RECT 71.15 11.502 75.65 11.908 ;
        RECT 70.9 11.752 75.4 12.158 ;
        RECT 70.65 12.002 75.15 12.408 ;
        RECT 70.4 12.252 74.9 12.658 ;
        RECT 70.15 12.502 74.65 12.908 ;
        RECT 69.9 12.752 74.4 13.158 ;
        RECT 69.65 13.002 74.15 13.408 ;
        RECT 69.4 13.252 73.9 13.658 ;
        RECT 69.15 13.502 73.65 13.908 ;
        RECT 68.9 13.752 73.4 14.158 ;
        RECT 68.65 14.002 73.15 14.408 ;
        RECT 68.4 14.252 72.9 14.658 ;
        RECT 68.15 14.502 72.65 14.908 ;
        RECT 67.9 14.752 72.4 15.158 ;
        RECT 67.65 15.002 72.15 15.408 ;
        RECT 67.4 15.252 71.9 15.658 ;
        RECT 67.15 15.502 71.65 15.908 ;
        RECT 66.9 15.752 71.4 16.158 ;
        RECT 66.65 16.002 71.15 16.408 ;
        RECT 66.4 16.252 70.9 16.658 ;
        RECT 66.15 16.502 70.65 16.908 ;
        RECT 65.9 16.752 70.4 17.158 ;
        RECT 65.65 17.002 70.15 17.408 ;
        RECT 65.4 17.252 69.9 17.658 ;
        RECT 65.15 17.502 69.65 17.908 ;
        RECT 64.9 17.752 69.4 18.158 ;
        RECT 64.65 18.002 69.15 18.408 ;
        RECT 64.4 18.252 68.9 18.658 ;
        RECT 64.15 18.502 68.65 18.908 ;
        RECT 63.9 18.752 68.4 19.158 ;
        RECT 63.65 19.002 68.15 19.408 ;
        RECT 63.4 19.252 67.9 19.658 ;
        RECT 63.15 19.502 67.65 19.908 ;
        RECT 62.9 19.752 67.4 20.158 ;
        RECT 62.65 20.002 67.15 20.408 ;
        RECT 62.4 20.252 66.9 20.658 ;
        RECT 62.15 20.502 66.65 20.908 ;
        RECT 61.9 20.752 66.4 21.158 ;
        RECT 61.65 21.002 66.15 21.408 ;
        RECT 61.4 21.252 65.9 21.658 ;
        RECT 61.15 21.502 65.65 21.908 ;
        RECT 60.9 21.752 65.4 22.158 ;
        RECT 60.65 22.002 65.15 22.408 ;
        RECT 60.4 22.252 64.9 22.658 ;
        RECT 60.15 22.502 64.65 22.908 ;
        RECT 59.9 22.752 64.4 23.158 ;
        RECT 59.65 23.002 64.15 23.408 ;
        RECT 59.4 23.252 63.9 23.658 ;
        RECT 59.15 23.502 63.65 23.908 ;
        RECT 58.9 23.752 63.4 24.158 ;
        RECT 58.65 24.002 63.15 24.408 ;
        RECT 58.4 24.252 62.9 24.658 ;
        RECT 58.15 24.502 62.65 24.908 ;
        RECT 57.9 24.752 62.4 25.158 ;
        RECT 57.65 25.002 62.15 25.408 ;
        RECT 57.4 25.252 61.9 25.658 ;
        RECT 57.15 25.502 61.65 25.908 ;
        RECT 56.9 25.752 61.4 26.158 ;
        RECT 56.65 26.002 61.15 26.408 ;
        RECT 56.4 26.252 60.9 26.658 ;
        RECT 56.15 26.502 60.65 26.908 ;
        RECT 55.9 26.752 60.4 27.158 ;
        RECT 55.65 27.002 60.15 27.408 ;
        RECT 55.4 27.252 59.9 27.658 ;
        RECT 55.15 27.502 59.65 27.908 ;
        RECT 54.9 27.752 59.4 28.158 ;
        RECT 54.65 28.002 59.15 28.408 ;
        RECT 54.4 28.252 58.9 28.658 ;
        RECT 54.15 28.502 58.65 28.908 ;
        RECT 53.9 28.752 58.4 29.158 ;
        RECT 53.65 29.002 58.15 29.408 ;
        RECT 53.4 29.252 57.9 29.658 ;
        RECT 53.15 29.502 57.65 29.908 ;
        RECT 52.9 29.752 57.4 30.158 ;
        RECT 52.65 30.002 57.15 30.408 ;
        RECT 52.4 30.252 56.9 30.658 ;
        RECT 52.15 30.502 56.65 30.908 ;
        RECT 51.9 30.752 56.4 31.158 ;
        RECT 51.65 31.002 56.15 31.408 ;
        RECT 51.4 31.252 55.9 31.658 ;
        RECT 51.15 31.502 55.65 31.908 ;
        RECT 50.9 31.752 55.4 32.158 ;
        RECT 50.65 32.002 55.15 32.408 ;
        RECT 50.4 32.252 54.9 32.658 ;
        RECT 50.15 32.502 54.65 32.908 ;
        RECT 49.9 32.752 54.4 33.158 ;
        RECT 49.65 33.002 54.15 33.408 ;
        RECT 49.4 33.252 53.9 33.658 ;
        RECT 49.15 33.502 53.65 33.908 ;
        RECT 48.9 33.752 53.4 34.158 ;
        RECT 48.65 34.002 53.15 34.408 ;
        RECT 48.4 34.252 52.9 34.658 ;
        RECT 48.15 34.502 52.65 34.908 ;
        RECT 47.9 34.752 52.4 35.158 ;
        RECT 47.65 35.002 52.15 35.408 ;
        RECT 47.4 35.252 51.9 35.658 ;
        RECT 47.15 35.502 51.65 35.908 ;
        RECT 46.9 35.752 51.4 36.158 ;
        RECT 46.65 36.002 51.15 36.408 ;
        RECT 46.4 36.252 50.9 36.658 ;
        RECT 46.15 36.502 50.65 36.908 ;
        RECT 45.9 36.752 50.4 37.158 ;
        RECT 45.65 37.002 50.15 37.408 ;
        RECT 45.4 37.252 49.9 37.658 ;
        RECT 45.15 37.502 49.65 37.908 ;
        RECT 44.9 37.752 49.4 38.158 ;
        RECT 44.65 38.002 49.15 38.408 ;
        RECT 44.4 38.252 48.9 38.658 ;
        RECT 44.15 38.502 48.65 38.908 ;
        RECT 43.9 38.752 48.4 39.158 ;
        RECT 43.65 39.002 48.15 39.408 ;
        RECT 43.4 39.252 47.9 39.658 ;
        RECT 43.15 39.502 47.65 39.908 ;
        RECT 42.9 39.752 47.4 40.158 ;
        RECT 42.65 40.002 47.15 40.408 ;
        RECT 42.4 40.252 46.9 40.658 ;
        RECT 42.15 40.502 46.65 40.908 ;
        RECT 41.9 40.752 46.4 41.158 ;
        RECT 41.65 41.002 46.15 41.408 ;
        RECT 41.4 41.252 45.9 41.658 ;
        RECT 41.15 41.502 45.65 41.908 ;
        RECT 40.9 41.752 45.4 42.158 ;
        RECT 40.65 42.002 45.15 42.408 ;
        RECT 40.4 42.252 44.9 42.658 ;
        RECT 40.15 42.502 44.65 42.908 ;
        RECT 39.9 42.752 44.4 43.158 ;
        RECT 39.65 43.002 44.15 43.408 ;
        RECT 39.4 43.252 43.9 43.658 ;
        RECT 39.15 43.502 43.65 43.908 ;
        RECT 38.9 43.752 43.4 44.158 ;
        RECT 38.65 44.002 43.15 44.408 ;
        RECT 38.4 44.252 42.9 44.658 ;
        RECT 38.15 44.502 42.65 44.908 ;
        RECT 37.9 44.752 42.4 45.158 ;
        RECT 37.65 45.002 42.15 45.408 ;
        RECT 37.4 45.252 41.9 45.658 ;
        RECT 37.15 45.502 41.65 45.908 ;
        RECT 36.9 45.752 41.4 46.158 ;
        RECT 36.65 46.002 41.15 46.408 ;
        RECT 36.4 46.252 40.9 46.658 ;
        RECT 36.15 46.502 40.65 46.908 ;
        RECT 35.9 46.752 40.4 47.158 ;
        RECT 35.65 47.002 40.15 47.408 ;
        RECT 35.4 47.252 39.9 47.658 ;
        RECT 35.15 47.502 39.65 47.908 ;
        RECT 34.9 47.752 39.4 48.158 ;
        RECT 34.65 48.002 39.15 48.408 ;
        RECT 34.4 48.252 38.9 48.658 ;
        RECT 34.15 48.502 38.65 48.908 ;
        RECT 33.9 48.752 38.4 49.158 ;
        RECT 33.65 49.002 38.15 49.408 ;
        RECT 33.4 49.252 37.9 49.658 ;
        RECT 33.15 49.502 37.65 49.908 ;
        RECT 32.9 49.752 37.4 50.158 ;
        RECT 32.65 50.002 37.15 50.408 ;
        RECT 32.4 50.252 36.9 50.658 ;
        RECT 32.15 50.502 36.65 50.908 ;
        RECT 31.9 50.752 36.4 51.158 ;
        RECT 31.65 51.002 36.15 51.408 ;
        RECT 31.4 51.252 35.9 51.658 ;
        RECT 31.15 51.502 35.65 51.908 ;
        RECT 30.9 51.752 35.4 52.158 ;
        RECT 30.65 52.002 35.15 52.408 ;
        RECT 30.4 52.252 34.9 52.658 ;
        RECT 30.15 52.502 34.65 52.908 ;
        RECT 29.9 52.752 34.4 53.158 ;
        RECT 29.65 53.002 34.15 53.408 ;
        RECT 29.4 53.252 33.9 53.658 ;
        RECT 29.15 53.502 33.65 53.908 ;
        RECT 28.9 53.752 33.4 54.158 ;
        RECT 28.65 54.002 33.15 54.408 ;
        RECT 28.4 54.252 32.9 54.658 ;
        RECT 28.15 54.502 32.65 54.908 ;
        RECT 27.9 54.752 32.4 55.158 ;
        RECT 27.65 55.002 32.15 55.408 ;
        RECT 27.4 55.252 31.9 55.658 ;
        RECT 27.15 55.502 31.65 55.908 ;
        RECT 26.9 55.752 31.4 56.158 ;
        RECT 26.65 56.002 31.15 56.408 ;
        RECT 26.4 56.252 30.9 56.658 ;
        RECT 26.15 56.502 30.65 56.908 ;
        RECT 25.9 56.752 30.4 57.158 ;
        RECT 25.65 57.002 30.15 57.408 ;
        RECT 25.4 57.252 29.9 57.658 ;
        RECT 25.15 57.502 29.65 57.908 ;
        RECT 24.9 57.752 29.4 58.158 ;
        RECT 24.65 58.002 29.15 58.408 ;
        RECT 24.4 58.252 28.9 58.658 ;
        RECT 24.15 58.502 28.65 58.908 ;
        RECT 23.9 58.752 28.4 59.158 ;
        RECT 23.65 59.002 28.15 59.408 ;
        RECT 23.4 59.252 27.9 59.658 ;
        RECT 23.15 59.502 27.65 59.908 ;
        RECT 22.9 59.752 27.4 60.158 ;
        RECT 22.65 60.002 27.15 60.408 ;
        RECT 22.4 60.252 26.9 60.658 ;
        RECT 22.15 60.502 26.65 60.908 ;
        RECT 21.9 60.752 26.4 61.158 ;
        RECT 21.65 61.002 26.15 61.408 ;
        RECT 21.4 61.252 25.9 61.658 ;
        RECT 21.15 61.502 25.65 61.908 ;
        RECT 20.9 61.752 25.4 62.158 ;
        RECT 20.65 62.002 25.15 62.408 ;
        RECT 20.4 62.252 24.9 62.658 ;
        RECT 20.15 62.502 24.65 62.908 ;
        RECT 19.9 62.752 24.4 63.158 ;
        RECT 19.65 63.002 24.15 63.408 ;
        RECT 19.4 63.252 23.9 63.658 ;
        RECT 19.15 63.502 23.65 63.908 ;
        RECT 18.9 63.752 23.4 64.158 ;
        RECT 18.65 64.002 23.15 64.408 ;
        RECT 18.4 64.252 22.9 64.658 ;
        RECT 18.15 64.502 22.65 64.908 ;
        RECT 17.9 64.752 22.4 65.158 ;
        RECT 17.65 65.002 22.15 65.408 ;
        RECT 17.4 65.252 21.9 65.658 ;
        RECT 17.15 65.502 21.65 65.908 ;
        RECT 16.9 65.752 21.4 66.158 ;
        RECT 16.65 66.002 21.15 66.408 ;
        RECT 16.4 66.252 20.9 66.658 ;
        RECT 16.15 66.502 20.65 66.908 ;
        RECT 15.9 66.752 20.4 67.158 ;
        RECT 15.65 67.002 20.15 67.408 ;
        RECT 15.4 67.252 19.9 67.658 ;
        RECT 15.15 67.502 19.65 67.908 ;
        RECT 14.9 67.752 19.4 68.158 ;
        RECT 14.65 68.002 19.15 68.408 ;
        RECT 14.4 68.252 18.9 68.658 ;
        RECT 14.15 68.502 18.65 68.908 ;
        RECT 13.9 68.752 18.4 69.158 ;
        RECT 13.65 69.002 18.15 69.408 ;
        RECT 13.4 69.252 17.9 69.658 ;
        RECT 13.15 69.502 17.65 69.908 ;
        RECT 12.9 69.752 17.4 70.158 ;
        RECT 12.65 70.002 17.15 70.408 ;
        RECT 12.4 70.252 16.9 70.658 ;
        RECT 12.15 70.502 16.65 70.908 ;
        RECT 11.9 70.752 16.4 71.158 ;
        RECT 11.65 71.002 16.15 71.408 ;
        RECT 11.4 71.252 15.9 71.658 ;
        RECT 11.15 71.502 15.65 71.908 ;
        RECT 10.9 71.752 15.4 72.158 ;
        RECT 10.65 72.002 15.15 72.408 ;
        RECT 10.4 72.252 14.9 72.658 ;
        RECT 10.15 72.502 14.65 72.908 ;
        RECT 9.9 72.752 14.4 73.158 ;
        RECT 9.65 73.002 14.15 73.408 ;
        RECT 9.4 73.252 13.9 73.658 ;
        RECT 9.15 73.502 13.65 73.908 ;
        RECT 8.9 73.752 13.4 74.158 ;
        RECT 8.65 74.002 13.15 74.408 ;
        RECT 8.4 74.252 12.9 74.658 ;
        RECT 8.15 74.502 12.65 74.908 ;
        RECT 7.9 74.752 12.4 75.158 ;
        RECT 7.65 75.002 12.15 75.408 ;
        RECT 7.4 75.252 11.9 75.658 ;
        RECT 7.15 75.502 11.65 75.908 ;
        RECT 6.9 75.752 11.4 76.158 ;
        RECT 6.65 76.002 11.15 76.408 ;
        RECT 6.4 76.252 10.9 76.658 ;
        RECT 6.15 76.502 10.65 76.908 ;
        RECT 5.9 76.752 10.4 77.158 ;
        RECT 5.65 77.002 10.15 77.408 ;
        RECT 5.4 77.252 9.9 77.658 ;
        RECT 5.15 77.502 9.65 77.908 ;
        RECT 4.9 77.752 9.4 78.158 ;
        RECT 4.9 77.752 9.15 78.408 ;
        RECT 4.9 77.752 8.9 78.658 ;
        RECT 4.9 77.752 8.65 78.908 ;
        RECT 4.9 77.752 8.4 119.5 ;
        RECT 80.057 9.8 119.5 13.3 ;
        RECT 76.55 13.182 81.213 13.378 ;
        RECT 75.55 14.182 80.057 14.46 ;
        RECT 75.8 13.932 80.307 14.331 ;
        RECT 80.05 9.803 80.057 14.46 ;
        RECT 76.05 13.682 80.557 14.081 ;
        RECT 79.8 9.932 80.05 14.588 ;
        RECT 75.3 14.432 79.8 14.838 ;
        RECT 76.3 13.432 80.807 13.831 ;
        RECT 79.55 10.182 79.8 14.838 ;
        RECT 75.05 14.682 79.55 15.088 ;
        RECT 76.55 13.182 81.057 13.581 ;
        RECT 79.3 10.432 79.55 15.088 ;
        RECT 74.8 14.932 79.3 15.338 ;
        RECT 76.8 12.932 119.5 13.3 ;
        RECT 79.05 10.682 79.3 15.338 ;
        RECT 74.55 15.182 79.05 15.588 ;
        RECT 77.05 12.682 119.5 13.3 ;
        RECT 78.8 10.932 79.05 15.588 ;
        RECT 74.3 15.432 78.8 15.838 ;
        RECT 77.3 12.432 119.5 13.3 ;
        RECT 78.55 11.182 78.8 15.838 ;
        RECT 74.05 15.682 78.55 16.088 ;
        RECT 77.55 12.182 119.5 13.3 ;
        RECT 78.3 11.432 78.55 16.088 ;
        RECT 73.8 15.932 78.3 16.338 ;
        RECT 77.8 11.932 119.5 13.3 ;
        RECT 78.05 11.682 78.3 16.338 ;
        RECT 73.55 16.182 78.05 16.588 ;
        RECT 73.3 16.432 77.8 16.838 ;
        RECT 73.05 16.682 77.55 17.088 ;
        RECT 72.8 16.932 77.3 17.338 ;
        RECT 72.55 17.182 77.05 17.588 ;
        RECT 72.3 17.432 76.8 17.838 ;
        RECT 72.05 17.682 76.55 18.088 ;
        RECT 71.8 17.932 76.3 18.338 ;
        RECT 71.55 18.182 76.05 18.588 ;
        RECT 71.3 18.432 75.8 18.838 ;
        RECT 71.05 18.682 75.55 19.088 ;
        RECT 70.8 18.932 75.3 19.338 ;
        RECT 70.55 19.182 75.05 19.588 ;
        RECT 70.3 19.432 74.8 19.838 ;
        RECT 70.05 19.682 74.55 20.088 ;
        RECT 69.8 19.932 74.3 20.338 ;
        RECT 69.55 20.182 74.05 20.588 ;
        RECT 69.3 20.432 73.8 20.838 ;
        RECT 69.05 20.682 73.55 21.088 ;
        RECT 68.8 20.932 73.3 21.338 ;
        RECT 68.55 21.182 73.05 21.588 ;
        RECT 68.3 21.432 72.8 21.838 ;
        RECT 68.05 21.682 72.55 22.088 ;
        RECT 67.8 21.932 72.3 22.338 ;
        RECT 67.55 22.182 72.05 22.588 ;
        RECT 67.3 22.432 71.8 22.838 ;
        RECT 67.05 22.682 71.55 23.088 ;
        RECT 66.8 22.932 71.3 23.338 ;
        RECT 66.55 23.182 71.05 23.588 ;
        RECT 66.3 23.432 70.8 23.838 ;
        RECT 66.05 23.682 70.55 24.088 ;
        RECT 65.8 23.932 70.3 24.338 ;
        RECT 65.55 24.182 70.05 24.588 ;
        RECT 65.3 24.432 69.8 24.838 ;
        RECT 65.05 24.682 69.55 25.088 ;
        RECT 64.8 24.932 69.3 25.338 ;
        RECT 64.55 25.182 69.05 25.588 ;
        RECT 64.3 25.432 68.8 25.838 ;
        RECT 64.05 25.682 68.55 26.088 ;
        RECT 63.8 25.932 68.3 26.338 ;
        RECT 63.55 26.182 68.05 26.588 ;
        RECT 63.3 26.432 67.8 26.838 ;
        RECT 63.05 26.682 67.55 27.088 ;
        RECT 62.8 26.932 67.3 27.338 ;
        RECT 62.55 27.182 67.05 27.588 ;
        RECT 62.3 27.432 66.8 27.838 ;
        RECT 62.05 27.682 66.55 28.088 ;
        RECT 61.8 27.932 66.3 28.338 ;
        RECT 61.55 28.182 66.05 28.588 ;
        RECT 61.3 28.432 65.8 28.838 ;
        RECT 61.05 28.682 65.55 29.088 ;
        RECT 60.8 28.932 65.3 29.338 ;
        RECT 60.55 29.182 65.05 29.588 ;
        RECT 60.3 29.432 64.8 29.838 ;
        RECT 60.05 29.682 64.55 30.088 ;
        RECT 59.8 29.932 64.3 30.338 ;
        RECT 59.55 30.182 64.05 30.588 ;
        RECT 59.3 30.432 63.8 30.838 ;
        RECT 59.05 30.682 63.55 31.088 ;
        RECT 58.8 30.932 63.3 31.338 ;
        RECT 58.55 31.182 63.05 31.588 ;
        RECT 58.3 31.432 62.8 31.838 ;
        RECT 58.05 31.682 62.55 32.088 ;
        RECT 57.8 31.932 62.3 32.338 ;
        RECT 57.55 32.182 62.05 32.588 ;
        RECT 57.3 32.432 61.8 32.838 ;
        RECT 57.05 32.682 61.55 33.088 ;
        RECT 56.8 32.932 61.3 33.338 ;
        RECT 56.55 33.182 61.05 33.588 ;
        RECT 56.3 33.432 60.8 33.838 ;
        RECT 56.05 33.682 60.55 34.088 ;
        RECT 55.8 33.932 60.3 34.338 ;
        RECT 55.55 34.182 60.05 34.588 ;
        RECT 55.3 34.432 59.8 34.838 ;
        RECT 55.05 34.682 59.55 35.088 ;
        RECT 54.8 34.932 59.3 35.338 ;
        RECT 54.55 35.182 59.05 35.588 ;
        RECT 54.3 35.432 58.8 35.838 ;
        RECT 54.05 35.682 58.55 36.088 ;
        RECT 53.8 35.932 58.3 36.338 ;
        RECT 53.55 36.182 58.05 36.588 ;
        RECT 53.3 36.432 57.8 36.838 ;
        RECT 53.05 36.682 57.55 37.088 ;
        RECT 52.8 36.932 57.3 37.338 ;
        RECT 52.55 37.182 57.05 37.588 ;
        RECT 52.3 37.432 56.8 37.838 ;
        RECT 52.05 37.682 56.55 38.088 ;
        RECT 51.8 37.932 56.3 38.338 ;
        RECT 51.55 38.182 56.05 38.588 ;
        RECT 51.3 38.432 55.8 38.838 ;
        RECT 51.05 38.682 55.55 39.088 ;
        RECT 50.8 38.932 55.3 39.338 ;
        RECT 50.55 39.182 55.05 39.588 ;
        RECT 50.3 39.432 54.8 39.838 ;
        RECT 50.05 39.682 54.55 40.088 ;
        RECT 49.8 39.932 54.3 40.338 ;
        RECT 49.55 40.182 54.05 40.588 ;
        RECT 49.3 40.432 53.8 40.838 ;
        RECT 49.05 40.682 53.55 41.088 ;
        RECT 48.8 40.932 53.3 41.338 ;
        RECT 48.55 41.182 53.05 41.588 ;
        RECT 48.3 41.432 52.8 41.838 ;
        RECT 48.05 41.682 52.55 42.088 ;
        RECT 47.8 41.932 52.3 42.338 ;
        RECT 47.55 42.182 52.05 42.588 ;
        RECT 47.3 42.432 51.8 42.838 ;
        RECT 47.05 42.682 51.55 43.088 ;
        RECT 46.8 42.932 51.3 43.338 ;
        RECT 46.55 43.182 51.05 43.588 ;
        RECT 46.3 43.432 50.8 43.838 ;
        RECT 46.05 43.682 50.55 44.088 ;
        RECT 45.8 43.932 50.3 44.338 ;
        RECT 45.55 44.182 50.05 44.588 ;
        RECT 45.3 44.432 49.8 44.838 ;
        RECT 45.05 44.682 49.55 45.088 ;
        RECT 44.8 44.932 49.3 45.338 ;
        RECT 44.55 45.182 49.05 45.588 ;
        RECT 44.3 45.432 48.8 45.838 ;
        RECT 44.05 45.682 48.55 46.088 ;
        RECT 43.8 45.932 48.3 46.338 ;
        RECT 43.55 46.182 48.05 46.588 ;
        RECT 43.3 46.432 47.8 46.838 ;
        RECT 43.05 46.682 47.55 47.088 ;
        RECT 42.8 46.932 47.3 47.338 ;
        RECT 42.55 47.182 47.05 47.588 ;
        RECT 42.3 47.432 46.8 47.838 ;
        RECT 42.05 47.682 46.55 48.088 ;
        RECT 41.8 47.932 46.3 48.338 ;
        RECT 41.55 48.182 46.05 48.588 ;
        RECT 41.3 48.432 45.8 48.838 ;
        RECT 41.05 48.682 45.55 49.088 ;
        RECT 40.8 48.932 45.3 49.338 ;
        RECT 40.55 49.182 45.05 49.588 ;
        RECT 40.3 49.432 44.8 49.838 ;
        RECT 40.05 49.682 44.55 50.088 ;
        RECT 39.8 49.932 44.3 50.338 ;
        RECT 39.55 50.182 44.05 50.588 ;
        RECT 39.3 50.432 43.8 50.838 ;
        RECT 39.05 50.682 43.55 51.088 ;
        RECT 38.8 50.932 43.3 51.338 ;
        RECT 38.55 51.182 43.05 51.588 ;
        RECT 38.3 51.432 42.8 51.838 ;
        RECT 38.05 51.682 42.55 52.088 ;
        RECT 37.8 51.932 42.3 52.338 ;
        RECT 37.55 52.182 42.05 52.588 ;
        RECT 37.3 52.432 41.8 52.838 ;
        RECT 37.05 52.682 41.55 53.088 ;
        RECT 36.8 52.932 41.3 53.338 ;
        RECT 36.55 53.182 41.05 53.588 ;
        RECT 36.3 53.432 40.8 53.838 ;
        RECT 36.05 53.682 40.55 54.088 ;
        RECT 35.8 53.932 40.3 54.338 ;
        RECT 35.55 54.182 40.05 54.588 ;
        RECT 35.3 54.432 39.8 54.838 ;
        RECT 35.05 54.682 39.55 55.088 ;
        RECT 34.8 54.932 39.3 55.338 ;
        RECT 34.55 55.182 39.05 55.588 ;
        RECT 34.3 55.432 38.8 55.838 ;
        RECT 34.05 55.682 38.55 56.088 ;
        RECT 33.8 55.932 38.3 56.338 ;
        RECT 33.55 56.182 38.05 56.588 ;
        RECT 33.3 56.432 37.8 56.838 ;
        RECT 33.05 56.682 37.55 57.088 ;
        RECT 32.8 56.932 37.3 57.338 ;
        RECT 32.55 57.182 37.05 57.588 ;
        RECT 32.3 57.432 36.8 57.838 ;
        RECT 32.05 57.682 36.55 58.088 ;
        RECT 31.8 57.932 36.3 58.338 ;
        RECT 31.55 58.182 36.05 58.588 ;
        RECT 31.3 58.432 35.8 58.838 ;
        RECT 31.05 58.682 35.55 59.088 ;
        RECT 30.8 58.932 35.3 59.338 ;
        RECT 30.55 59.182 35.05 59.588 ;
        RECT 30.3 59.432 34.8 59.838 ;
        RECT 30.05 59.682 34.55 60.088 ;
        RECT 29.8 59.932 34.3 60.338 ;
        RECT 29.55 60.182 34.05 60.588 ;
        RECT 29.3 60.432 33.8 60.838 ;
        RECT 29.05 60.682 33.55 61.088 ;
        RECT 28.8 60.932 33.3 61.338 ;
        RECT 28.55 61.182 33.05 61.588 ;
        RECT 28.3 61.432 32.8 61.838 ;
        RECT 28.05 61.682 32.55 62.088 ;
        RECT 27.8 61.932 32.3 62.338 ;
        RECT 27.55 62.182 32.05 62.588 ;
        RECT 27.3 62.432 31.8 62.838 ;
        RECT 27.05 62.682 31.55 63.088 ;
        RECT 26.8 62.932 31.3 63.338 ;
        RECT 26.55 63.182 31.05 63.588 ;
        RECT 26.3 63.432 30.8 63.838 ;
        RECT 26.05 63.682 30.55 64.088 ;
        RECT 25.8 63.932 30.3 64.338 ;
        RECT 25.55 64.182 30.05 64.588 ;
        RECT 25.3 64.432 29.8 64.838 ;
        RECT 25.05 64.682 29.55 65.088 ;
        RECT 24.8 64.932 29.3 65.338 ;
        RECT 24.55 65.182 29.05 65.588 ;
        RECT 24.3 65.432 28.8 65.838 ;
        RECT 24.05 65.682 28.55 66.088 ;
        RECT 23.8 65.932 28.3 66.338 ;
        RECT 23.55 66.182 28.05 66.588 ;
        RECT 23.3 66.432 27.8 66.838 ;
        RECT 23.05 66.682 27.55 67.088 ;
        RECT 22.8 66.932 27.3 67.338 ;
        RECT 22.55 67.182 27.05 67.588 ;
        RECT 22.3 67.432 26.8 67.838 ;
        RECT 22.05 67.682 26.55 68.088 ;
        RECT 21.8 67.932 26.3 68.338 ;
        RECT 21.55 68.182 26.05 68.588 ;
        RECT 21.3 68.432 25.8 68.838 ;
        RECT 21.05 68.682 25.55 69.088 ;
        RECT 20.8 68.932 25.3 69.338 ;
        RECT 20.55 69.182 25.05 69.588 ;
        RECT 20.3 69.432 24.8 69.838 ;
        RECT 20.05 69.682 24.55 70.088 ;
        RECT 19.8 69.932 24.3 70.338 ;
        RECT 19.55 70.182 24.05 70.588 ;
        RECT 19.3 70.432 23.8 70.838 ;
        RECT 19.05 70.682 23.55 71.088 ;
        RECT 18.8 70.932 23.3 71.338 ;
        RECT 18.55 71.182 23.05 71.588 ;
        RECT 18.3 71.432 22.8 71.838 ;
        RECT 18.05 71.682 22.55 72.088 ;
        RECT 17.8 71.932 22.3 72.338 ;
        RECT 17.55 72.182 22.05 72.588 ;
        RECT 17.3 72.432 21.8 72.838 ;
        RECT 17.05 72.682 21.55 73.088 ;
        RECT 16.8 72.932 21.3 73.338 ;
        RECT 16.55 73.182 21.05 73.588 ;
        RECT 16.3 73.432 20.8 73.838 ;
        RECT 16.05 73.682 20.55 74.088 ;
        RECT 15.8 73.932 20.3 74.338 ;
        RECT 15.55 74.182 20.05 74.588 ;
        RECT 15.3 74.432 19.8 74.838 ;
        RECT 15.05 74.682 19.55 75.088 ;
        RECT 14.8 74.932 19.3 75.338 ;
        RECT 14.55 75.182 19.05 75.588 ;
        RECT 14.3 75.432 18.8 75.838 ;
        RECT 14.05 75.682 18.55 76.088 ;
        RECT 13.8 75.932 18.3 76.338 ;
        RECT 13.55 76.182 18.05 76.588 ;
        RECT 13.3 76.432 17.8 76.838 ;
        RECT 13.05 76.682 17.55 77.088 ;
        RECT 12.8 76.932 17.3 77.338 ;
        RECT 12.55 77.182 17.05 77.588 ;
        RECT 12.3 77.432 16.8 77.838 ;
        RECT 12.05 77.682 16.55 78.088 ;
        RECT 11.8 77.932 16.3 78.338 ;
        RECT 11.55 78.182 16.05 78.588 ;
        RECT 11.3 78.432 15.8 78.838 ;
        RECT 11.05 78.682 15.55 79.088 ;
        RECT 10.8 78.932 15.3 79.338 ;
        RECT 10.55 79.182 15.05 79.588 ;
        RECT 10.3 79.432 14.8 79.838 ;
        RECT 10.05 79.682 14.55 80.088 ;
        RECT 9.8 79.932 14.3 80.338 ;
        RECT 9.8 79.932 14.05 80.588 ;
        RECT 9.8 79.932 13.8 80.838 ;
        RECT 9.8 79.932 13.55 81.088 ;
        RECT 9.8 79.932 13.3 119.5 ;
        RECT 82.777 14.7 119.5 18.2 ;
        RECT 79.2 18.152 83.933 18.278 ;
        RECT 78.45 18.902 83.027 19.231 ;
        RECT 82.7 14.738 82.777 19.395 ;
        RECT 78.2 19.152 82.7 19.558 ;
        RECT 78.7 18.652 83.277 18.981 ;
        RECT 82.45 14.902 82.7 19.558 ;
        RECT 77.95 19.402 82.45 19.808 ;
        RECT 78.95 18.402 83.527 18.731 ;
        RECT 82.2 15.152 82.45 19.808 ;
        RECT 77.7 19.652 82.2 20.058 ;
        RECT 79.2 18.152 83.777 18.481 ;
        RECT 81.95 15.402 82.2 20.058 ;
        RECT 77.45 19.902 81.95 20.308 ;
        RECT 79.45 17.902 119.5 18.2 ;
        RECT 81.7 15.652 81.95 20.308 ;
        RECT 77.2 20.152 81.7 20.558 ;
        RECT 79.7 17.652 119.5 18.2 ;
        RECT 81.45 15.902 81.7 20.558 ;
        RECT 76.95 20.402 81.45 20.808 ;
        RECT 79.95 17.402 119.5 18.2 ;
        RECT 81.2 16.152 81.45 20.808 ;
        RECT 76.7 20.652 81.2 21.058 ;
        RECT 80.2 17.152 119.5 18.2 ;
        RECT 80.95 16.402 81.2 21.058 ;
        RECT 76.45 20.902 80.95 21.308 ;
        RECT 80.45 16.902 119.5 18.2 ;
        RECT 80.7 16.652 80.95 21.308 ;
        RECT 76.2 21.152 80.7 21.558 ;
        RECT 75.95 21.402 80.45 21.808 ;
        RECT 75.7 21.652 80.2 22.058 ;
        RECT 75.45 21.902 79.95 22.308 ;
        RECT 75.2 22.152 79.7 22.558 ;
        RECT 74.95 22.402 79.45 22.808 ;
        RECT 74.7 22.652 79.2 23.058 ;
        RECT 74.45 22.902 78.95 23.308 ;
        RECT 74.2 23.152 78.7 23.558 ;
        RECT 73.95 23.402 78.45 23.808 ;
        RECT 73.7 23.652 78.2 24.058 ;
        RECT 73.45 23.902 77.95 24.308 ;
        RECT 73.2 24.152 77.7 24.558 ;
        RECT 72.95 24.402 77.45 24.808 ;
        RECT 72.7 24.652 77.2 25.058 ;
        RECT 72.45 24.902 76.95 25.308 ;
        RECT 72.2 25.152 76.7 25.558 ;
        RECT 71.95 25.402 76.45 25.808 ;
        RECT 71.7 25.652 76.2 26.058 ;
        RECT 71.45 25.902 75.95 26.308 ;
        RECT 71.2 26.152 75.7 26.558 ;
        RECT 70.95 26.402 75.45 26.808 ;
        RECT 70.7 26.652 75.2 27.058 ;
        RECT 70.45 26.902 74.95 27.308 ;
        RECT 70.2 27.152 74.7 27.558 ;
        RECT 69.95 27.402 74.45 27.808 ;
        RECT 69.7 27.652 74.2 28.058 ;
        RECT 69.45 27.902 73.95 28.308 ;
        RECT 69.2 28.152 73.7 28.558 ;
        RECT 68.95 28.402 73.45 28.808 ;
        RECT 68.7 28.652 73.2 29.058 ;
        RECT 68.45 28.902 72.95 29.308 ;
        RECT 68.2 29.152 72.7 29.558 ;
        RECT 67.95 29.402 72.45 29.808 ;
        RECT 67.7 29.652 72.2 30.058 ;
        RECT 67.45 29.902 71.95 30.308 ;
        RECT 67.2 30.152 71.7 30.558 ;
        RECT 66.95 30.402 71.45 30.808 ;
        RECT 66.7 30.652 71.2 31.058 ;
        RECT 66.45 30.902 70.95 31.308 ;
        RECT 66.2 31.152 70.7 31.558 ;
        RECT 65.95 31.402 70.45 31.808 ;
        RECT 65.7 31.652 70.2 32.058 ;
        RECT 65.45 31.902 69.95 32.308 ;
        RECT 65.2 32.152 69.7 32.558 ;
        RECT 64.95 32.402 69.45 32.808 ;
        RECT 64.7 32.652 69.2 33.058 ;
        RECT 64.45 32.902 68.95 33.308 ;
        RECT 64.2 33.152 68.7 33.558 ;
        RECT 63.95 33.402 68.45 33.808 ;
        RECT 63.7 33.652 68.2 34.058 ;
        RECT 63.45 33.902 67.95 34.308 ;
        RECT 63.2 34.152 67.7 34.558 ;
        RECT 62.95 34.402 67.45 34.808 ;
        RECT 62.7 34.652 67.2 35.058 ;
        RECT 62.45 34.902 66.95 35.308 ;
        RECT 62.2 35.152 66.7 35.558 ;
        RECT 61.95 35.402 66.45 35.808 ;
        RECT 61.7 35.652 66.2 36.058 ;
        RECT 61.45 35.902 65.95 36.308 ;
        RECT 61.2 36.152 65.7 36.558 ;
        RECT 60.95 36.402 65.45 36.808 ;
        RECT 60.7 36.652 65.2 37.058 ;
        RECT 60.45 36.902 64.95 37.308 ;
        RECT 60.2 37.152 64.7 37.558 ;
        RECT 59.95 37.402 64.45 37.808 ;
        RECT 59.7 37.652 64.2 38.058 ;
        RECT 59.45 37.902 63.95 38.308 ;
        RECT 59.2 38.152 63.7 38.558 ;
        RECT 58.95 38.402 63.45 38.808 ;
        RECT 58.7 38.652 63.2 39.058 ;
        RECT 58.45 38.902 62.95 39.308 ;
        RECT 58.2 39.152 62.7 39.558 ;
        RECT 57.95 39.402 62.45 39.808 ;
        RECT 57.7 39.652 62.2 40.058 ;
        RECT 57.45 39.902 61.95 40.308 ;
        RECT 57.2 40.152 61.7 40.558 ;
    END
  END VSSD
  OBS
    LAYER MET1 ;
      RECT 0 0 119.5 119.5 ;
    LAYER VIA1 ;
      RECT 0 0 119.5 119.5 ;
    LAYER MET2 ;
      RECT 0 0 119.5 119.5 ;
    LAYER VIA2 ;
      RECT 0 0 119.5 119.5 ;
    LAYER MET3 ;
      RECT 0 0 119.5 119.5 ;
    LAYER VIA3 ;
      RECT 0 0 119.5 119.5 ;
    LAYER MET4 ;
      RECT 0 0 119.5 119.5 ;
  END
END PCORNER

MACRO PCLAMP
  CLASS BLOCK ;
  ORIGIN 0 0 ;
  FOREIGN PCLAMP 0 0 ;
  SIZE 56.88 BY 69.2 ;
  SYMMETRY X Y R90 ;
  PIN VDDDESD
    DIRECTION INOUT ;
    USE POWER ;
    PORT
      LAYER MET4 ;
        RECT 0 15.7 4 19.2 ;
    END
    PORT
      LAYER MET4 ;
        RECT 0 30.4 56.88 33.9 ;
    END
    PORT
      LAYER MET4 ;
        RECT 0 25.5 56.88 29 ;
    END
    PORT
      LAYER MET4 ;
        RECT 0 20.6 56.88 24.1 ;
    END
    PORT
      LAYER MET4 ;
        RECT 52.88 15.7 56.88 19.2 ;
    END
    PORT
      LAYER MET4 ;
        RECT 0 10.8 56.88 14.3 ;
    END
    PORT
      LAYER MET4 ;
        RECT 0 5.9 56.88 9.4 ;
    END
  END VDDDESD
  PIN VSSDESD
    DIRECTION INOUT ;
    USE GROUND ;
    PORT
      LAYER MET4 ;
        RECT 0 35.215 4 38.715 ;
    END
    PORT
      LAYER MET4 ;
        RECT 0 59.8 56.88 63.3 ;
    END
    PORT
      LAYER MET4 ;
        RECT 0 54.9 56.88 58.4 ;
    END
    PORT
      LAYER MET4 ;
        RECT 0 49.915 56.88 53.415 ;
    END
    PORT
      LAYER MET4 ;
        RECT 0 45.015 56.88 48.515 ;
    END
    PORT
      LAYER MET4 ;
        RECT 0 40.115 56.88 43.615 ;
    END
    PORT
      LAYER MET4 ;
        RECT 52.88 35.215 56.88 38.715 ;
    END
  END VSSDESD
  OBS
    LAYER MET1 ;
      RECT 0 0 56.88 69.2 ;
    LAYER VIA1 ;
      RECT 0 0 56.88 69.2 ;
    LAYER MET2 ;
      RECT 0 0 56.88 69.2 ;
    LAYER VIA2 ;
      RECT 0 0 56.88 69.2 ;
    LAYER MET3 ;
      RECT 0 0 56.88 69.2 ;
    LAYER VIA3 ;
      RECT 0 0 56.88 69.2 ;
    LAYER MET4 ;
      RECT 0 0 56.88 69.2 ;
  END
END PCLAMP

MACRO PCLAMPC
  CLASS BLOCK ;
  ORIGIN 0 0 ;
  FOREIGN PCLAMPC 0 0 ;
  SIZE 56.88 BY 69.2 ;
  SYMMETRY X Y R90 ;
  PIN VDDESD
    DIRECTION INOUT ;
    USE POWER ;
    PORT
      LAYER MET4 ;
        RECT 0 15.7 4 19.2 ;
    END
    PORT
      LAYER MET4 ;
        RECT 0 30.4 56.88 33.9 ;
    END
    PORT
      LAYER MET4 ;
        RECT 0 25.5 56.88 29 ;
    END
    PORT
      LAYER MET4 ;
        RECT 0 20.6 56.88 24.1 ;
    END
    PORT
      LAYER MET4 ;
        RECT 52.88 15.7 56.88 19.2 ;
    END
    PORT
      LAYER MET4 ;
        RECT 0 10.8 56.88 14.3 ;
    END
    PORT
      LAYER MET4 ;
        RECT 0 5.9 56.88 9.4 ;
    END
  END VDDESD
  PIN VSSESD
    DIRECTION INOUT ;
    USE GROUND ;
    PORT
      LAYER MET4 ;
        RECT 0 35.215 4 38.715 ;
    END
    PORT
      LAYER MET4 ;
        RECT 0 59.8 56.88 63.3 ;
    END
    PORT
      LAYER MET4 ;
        RECT 0 54.9 56.88 58.4 ;
    END
    PORT
      LAYER MET4 ;
        RECT 0 49.915 56.88 53.415 ;
    END
    PORT
      LAYER MET4 ;
        RECT 0 45.015 56.88 48.515 ;
    END
    PORT
      LAYER MET4 ;
        RECT 0 40.115 56.88 43.615 ;
    END
    PORT
      LAYER MET4 ;
        RECT 52.88 35.215 56.88 38.715 ;
    END
  END VSSESD
  OBS
    LAYER MET1 ;
      RECT 0 0 56.88 69.2 ;
    LAYER VIA1 ;
      RECT 0 0 56.88 69.2 ;
    LAYER MET2 ;
      RECT 0 0 56.88 69.2 ;
    LAYER VIA2 ;
      RECT 0 0 56.88 69.2 ;
    LAYER MET3 ;
      RECT 0 0 56.88 69.2 ;
    LAYER VIA3 ;
      RECT 0 0 56.88 69.2 ;
    LAYER MET4 ;
      RECT 0 0 56.88 69.2 ;
  END
END PCLAMPC

END LIBRARY
